VERSION 5.8 ;
BUSBITCHARS "[]" ;
DIVIDERCHAR "/" ;
UNITS
    DATABASE MICRONS 1000 ;
END UNITS

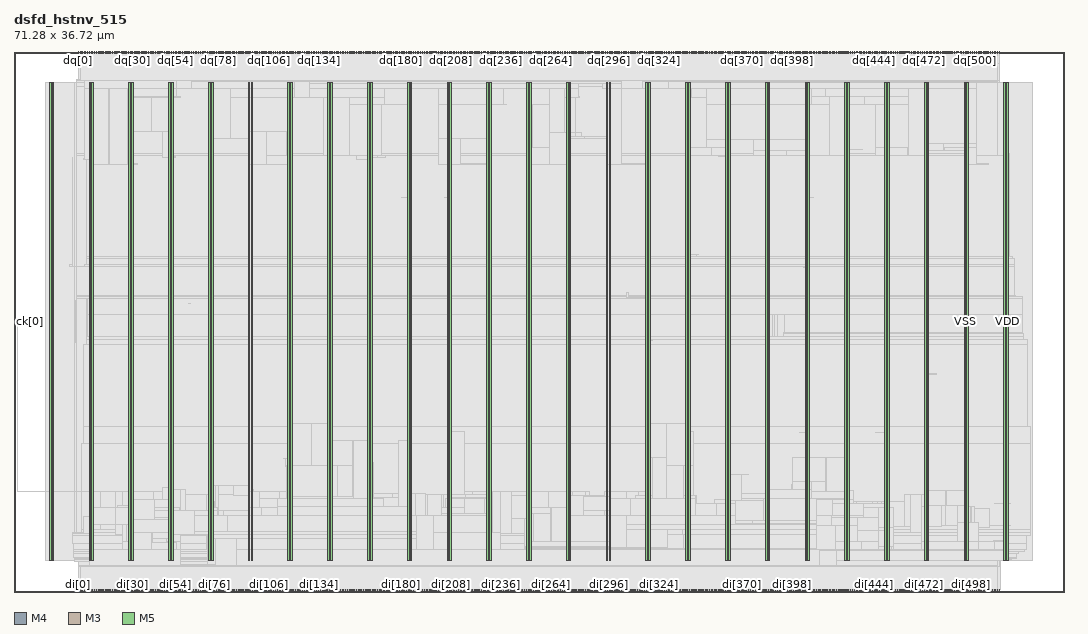
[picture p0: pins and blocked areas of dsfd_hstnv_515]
MACRO dsfd_hstnv_515
  FOREIGN dsfd_hstnv_515 0 0 ;
  CLASS BLOCK ;
  SIZE 71.28 BY 36.72 ;
  PIN ck[0]
    DIRECTION INPUT ;
    USE SIGNAL ;
    PORT
      LAYER M4 ;
        RECT  0 18.384 0.192 18.408 ;
    END
    PORT
      LAYER M4 ;
        RECT  0.156 18.384 0.275 18.408 ;
    END
  END ck[0]
  PIN di[0]
    DIRECTION INPUT ;
    USE SIGNAL ;
    PORT
      LAYER M3 ;
        RECT  4.356 0 4.374 0.144 ;
    END
  END di[0]
  PIN di[100]
    DIRECTION INPUT ;
    USE SIGNAL ;
    PORT
      LAYER M3 ;
        RECT  16.524 0 16.542 0.144 ;
    END
  END di[100]
  PIN di[101]
    DIRECTION INPUT ;
    USE SIGNAL ;
    PORT
      LAYER M5 ;
        RECT  16.656 0 16.68 0.192 ;
    END
  END di[101]
  PIN di[102]
    DIRECTION INPUT ;
    USE SIGNAL ;
    PORT
      LAYER M3 ;
        RECT  16.776 0 16.794 0.144 ;
    END
  END di[102]
  PIN di[103]
    DIRECTION INPUT ;
    USE SIGNAL ;
    PORT
      LAYER M5 ;
        RECT  16.896 0 16.92 0.192 ;
    END
  END di[103]
  PIN di[104]
    DIRECTION INPUT ;
    USE SIGNAL ;
    PORT
      LAYER M3 ;
        RECT  17.028 0 17.046 0.144 ;
    END
  END di[104]
  PIN di[105]
    DIRECTION INPUT ;
    USE SIGNAL ;
    PORT
      LAYER M5 ;
        RECT  17.136 0 17.16 0.192 ;
    END
  END di[105]
  PIN di[106]
    DIRECTION INPUT ;
    USE SIGNAL ;
    PORT
      LAYER M3 ;
        RECT  17.28 0 17.298 0.144 ;
    END
  END di[106]
  PIN di[107]
    DIRECTION INPUT ;
    USE SIGNAL ;
    PORT
      LAYER M5 ;
        RECT  17.376 0 17.4 0.192 ;
    END
  END di[107]
  PIN di[108]
    DIRECTION INPUT ;
    USE SIGNAL ;
    PORT
      LAYER M3 ;
        RECT  17.496 0 17.514 0.144 ;
    END
  END di[108]
  PIN di[109]
    DIRECTION INPUT ;
    USE SIGNAL ;
    PORT
      LAYER M5 ;
        RECT  17.616 0 17.64 0.192 ;
    END
  END di[109]
  PIN di[10]
    DIRECTION INPUT ;
    USE SIGNAL ;
    PORT
      LAYER M3 ;
        RECT  5.58 0 5.598 0.144 ;
    END
  END di[10]
  PIN di[110]
    DIRECTION INPUT ;
    USE SIGNAL ;
    PORT
      LAYER M3 ;
        RECT  17.748 0 17.766 0.144 ;
    END
  END di[110]
  PIN di[111]
    DIRECTION INPUT ;
    USE SIGNAL ;
    PORT
      LAYER M5 ;
        RECT  17.856 0 17.88 0.192 ;
    END
  END di[111]
  PIN di[112]
    DIRECTION INPUT ;
    USE SIGNAL ;
    PORT
      LAYER M3 ;
        RECT  18 0 18.018 0.144 ;
    END
  END di[112]
  PIN di[113]
    DIRECTION INPUT ;
    USE SIGNAL ;
    PORT
      LAYER M5 ;
        RECT  18.096 0 18.12 0.192 ;
    END
  END di[113]
  PIN di[114]
    DIRECTION INPUT ;
    USE SIGNAL ;
    PORT
      LAYER M3 ;
        RECT  18.252 0 18.27 0.144 ;
    END
  END di[114]
  PIN di[115]
    DIRECTION INPUT ;
    USE SIGNAL ;
    PORT
      LAYER M5 ;
        RECT  18.336 0 18.36 0.192 ;
    END
  END di[115]
  PIN di[116]
    DIRECTION INPUT ;
    USE SIGNAL ;
    PORT
      LAYER M3 ;
        RECT  18.468 0 18.486 0.144 ;
    END
  END di[116]
  PIN di[117]
    DIRECTION INPUT ;
    USE SIGNAL ;
    PORT
      LAYER M5 ;
        RECT  18.576 0 18.6 0.192 ;
    END
  END di[117]
  PIN di[118]
    DIRECTION INPUT ;
    USE SIGNAL ;
    PORT
      LAYER M3 ;
        RECT  18.72 0 18.738 0.144 ;
    END
  END di[118]
  PIN di[119]
    DIRECTION INPUT ;
    USE SIGNAL ;
    PORT
      LAYER M5 ;
        RECT  18.864 0 18.888 0.192 ;
    END
  END di[119]
  PIN di[11]
    DIRECTION INPUT ;
    USE SIGNAL ;
    PORT
      LAYER M5 ;
        RECT  5.712 0 5.736 0.192 ;
    END
  END di[11]
  PIN di[120]
    DIRECTION INPUT ;
    USE SIGNAL ;
    PORT
      LAYER M3 ;
        RECT  18.972 0 18.99 0.144 ;
    END
  END di[120]
  PIN di[121]
    DIRECTION INPUT ;
    USE SIGNAL ;
    PORT
      LAYER M5 ;
        RECT  19.104 0 19.128 0.192 ;
    END
  END di[121]
  PIN di[122]
    DIRECTION INPUT ;
    USE SIGNAL ;
    PORT
      LAYER M3 ;
        RECT  19.224 0 19.242 0.144 ;
    END
  END di[122]
  PIN di[123]
    DIRECTION INPUT ;
    USE SIGNAL ;
    PORT
      LAYER M5 ;
        RECT  19.344 0 19.368 0.192 ;
    END
  END di[123]
  PIN di[124]
    DIRECTION INPUT ;
    USE SIGNAL ;
    PORT
      LAYER M3 ;
        RECT  19.44 0 19.458 0.144 ;
    END
  END di[124]
  PIN di[125]
    DIRECTION INPUT ;
    USE SIGNAL ;
    PORT
      LAYER M5 ;
        RECT  19.584 0 19.608 0.192 ;
    END
  END di[125]
  PIN di[126]
    DIRECTION INPUT ;
    USE SIGNAL ;
    PORT
      LAYER M3 ;
        RECT  19.692 0 19.71 0.144 ;
    END
  END di[126]
  PIN di[127]
    DIRECTION INPUT ;
    USE SIGNAL ;
    PORT
      LAYER M5 ;
        RECT  19.824 0 19.848 0.192 ;
    END
  END di[127]
  PIN di[128]
    DIRECTION INPUT ;
    USE SIGNAL ;
    PORT
      LAYER M3 ;
        RECT  19.944 0 19.962 0.144 ;
    END
  END di[128]
  PIN di[129]
    DIRECTION INPUT ;
    USE SIGNAL ;
    PORT
      LAYER M5 ;
        RECT  20.064 0 20.088 0.192 ;
    END
  END di[129]
  PIN di[12]
    DIRECTION INPUT ;
    USE SIGNAL ;
    PORT
      LAYER M3 ;
        RECT  5.832 0 5.85 0.144 ;
    END
  END di[12]
  PIN di[130]
    DIRECTION INPUT ;
    USE SIGNAL ;
    PORT
      LAYER M3 ;
        RECT  20.196 0 20.214 0.144 ;
    END
  END di[130]
  PIN di[131]
    DIRECTION INPUT ;
    USE SIGNAL ;
    PORT
      LAYER M5 ;
        RECT  20.304 0 20.328 0.192 ;
    END
  END di[131]
  PIN di[132]
    DIRECTION INPUT ;
    USE SIGNAL ;
    PORT
      LAYER M3 ;
        RECT  20.412 0 20.43 0.144 ;
    END
  END di[132]
  PIN di[133]
    DIRECTION INPUT ;
    USE SIGNAL ;
    PORT
      LAYER M5 ;
        RECT  20.544 0 20.568 0.192 ;
    END
  END di[133]
  PIN di[134]
    DIRECTION INPUT ;
    USE SIGNAL ;
    PORT
      LAYER M3 ;
        RECT  20.664 0 20.682 0.144 ;
    END
  END di[134]
  PIN di[135]
    DIRECTION INPUT ;
    USE SIGNAL ;
    PORT
      LAYER M5 ;
        RECT  20.784 0 20.808 0.192 ;
    END
  END di[135]
  PIN di[136]
    DIRECTION INPUT ;
    USE SIGNAL ;
    PORT
      LAYER M3 ;
        RECT  20.916 0 20.934 0.144 ;
    END
  END di[136]
  PIN di[137]
    DIRECTION INPUT ;
    USE SIGNAL ;
    PORT
      LAYER M5 ;
        RECT  21.024 0 21.048 0.192 ;
    END
  END di[137]
  PIN di[138]
    DIRECTION INPUT ;
    USE SIGNAL ;
    PORT
      LAYER M3 ;
        RECT  21.168 0 21.186 0.144 ;
    END
  END di[138]
  PIN di[139]
    DIRECTION INPUT ;
    USE SIGNAL ;
    PORT
      LAYER M5 ;
        RECT  21.264 0 21.288 0.192 ;
    END
  END di[139]
  PIN di[13]
    DIRECTION INPUT ;
    USE SIGNAL ;
    PORT
      LAYER M5 ;
        RECT  5.952 0 5.976 0.192 ;
    END
  END di[13]
  PIN di[140]
    DIRECTION INPUT ;
    USE SIGNAL ;
    PORT
      LAYER M3 ;
        RECT  21.384 0 21.402 0.144 ;
    END
  END di[140]
  PIN di[141]
    DIRECTION INPUT ;
    USE SIGNAL ;
    PORT
      LAYER M5 ;
        RECT  21.504 0 21.528 0.192 ;
    END
  END di[141]
  PIN di[142]
    DIRECTION INPUT ;
    USE SIGNAL ;
    PORT
      LAYER M3 ;
        RECT  21.636 0 21.654 0.144 ;
    END
  END di[142]
  PIN di[143]
    DIRECTION INPUT ;
    USE SIGNAL ;
    PORT
      LAYER M5 ;
        RECT  21.744 0 21.768 0.192 ;
    END
  END di[143]
  PIN di[144]
    DIRECTION INPUT ;
    USE SIGNAL ;
    PORT
      LAYER M3 ;
        RECT  21.888 0 21.906 0.144 ;
    END
  END di[144]
  PIN di[145]
    DIRECTION INPUT ;
    USE SIGNAL ;
    PORT
      LAYER M5 ;
        RECT  21.984 0 22.008 0.192 ;
    END
  END di[145]
  PIN di[146]
    DIRECTION INPUT ;
    USE SIGNAL ;
    PORT
      LAYER M3 ;
        RECT  22.14 0 22.158 0.144 ;
    END
  END di[146]
  PIN di[147]
    DIRECTION INPUT ;
    USE SIGNAL ;
    PORT
      LAYER M5 ;
        RECT  22.272 0 22.296 0.192 ;
    END
  END di[147]
  PIN di[148]
    DIRECTION INPUT ;
    USE SIGNAL ;
    PORT
      LAYER M3 ;
        RECT  22.356 0 22.374 0.144 ;
    END
  END di[148]
  PIN di[149]
    DIRECTION INPUT ;
    USE SIGNAL ;
    PORT
      LAYER M5 ;
        RECT  22.512 0 22.536 0.192 ;
    END
  END di[149]
  PIN di[14]
    DIRECTION INPUT ;
    USE SIGNAL ;
    PORT
      LAYER M3 ;
        RECT  6.084 0 6.102 0.144 ;
    END
  END di[14]
  PIN di[150]
    DIRECTION INPUT ;
    USE SIGNAL ;
    PORT
      LAYER M3 ;
        RECT  22.608 0 22.626 0.144 ;
    END
  END di[150]
  PIN di[151]
    DIRECTION INPUT ;
    USE SIGNAL ;
    PORT
      LAYER M5 ;
        RECT  22.752 0 22.776 0.192 ;
    END
  END di[151]
  PIN di[152]
    DIRECTION INPUT ;
    USE SIGNAL ;
    PORT
      LAYER M3 ;
        RECT  22.86 0 22.878 0.144 ;
    END
  END di[152]
  PIN di[153]
    DIRECTION INPUT ;
    USE SIGNAL ;
    PORT
      LAYER M5 ;
        RECT  22.992 0 23.016 0.192 ;
    END
  END di[153]
  PIN di[154]
    DIRECTION INPUT ;
    USE SIGNAL ;
    PORT
      LAYER M3 ;
        RECT  23.112 0 23.13 0.144 ;
    END
  END di[154]
  PIN di[155]
    DIRECTION INPUT ;
    USE SIGNAL ;
    PORT
      LAYER M5 ;
        RECT  23.232 0 23.256 0.192 ;
    END
  END di[155]
  PIN di[156]
    DIRECTION INPUT ;
    USE SIGNAL ;
    PORT
      LAYER M3 ;
        RECT  23.364 0 23.382 0.144 ;
    END
  END di[156]
  PIN di[157]
    DIRECTION INPUT ;
    USE SIGNAL ;
    PORT
      LAYER M5 ;
        RECT  23.472 0 23.496 0.192 ;
    END
  END di[157]
  PIN di[158]
    DIRECTION INPUT ;
    USE SIGNAL ;
    PORT
      LAYER M3 ;
        RECT  23.58 0 23.598 0.144 ;
    END
  END di[158]
  PIN di[159]
    DIRECTION INPUT ;
    USE SIGNAL ;
    PORT
      LAYER M5 ;
        RECT  23.712 0 23.736 0.192 ;
    END
  END di[159]
  PIN di[15]
    DIRECTION INPUT ;
    USE SIGNAL ;
    PORT
      LAYER M5 ;
        RECT  6.192 0 6.216 0.192 ;
    END
  END di[15]
  PIN di[160]
    DIRECTION INPUT ;
    USE SIGNAL ;
    PORT
      LAYER M3 ;
        RECT  23.832 0 23.85 0.144 ;
    END
  END di[160]
  PIN di[161]
    DIRECTION INPUT ;
    USE SIGNAL ;
    PORT
      LAYER M5 ;
        RECT  23.952 0 23.976 0.192 ;
    END
  END di[161]
  PIN di[162]
    DIRECTION INPUT ;
    USE SIGNAL ;
    PORT
      LAYER M3 ;
        RECT  24.084 0 24.102 0.144 ;
    END
  END di[162]
  PIN di[163]
    DIRECTION INPUT ;
    USE SIGNAL ;
    PORT
      LAYER M5 ;
        RECT  24.192 0 24.216 0.192 ;
    END
  END di[163]
  PIN di[164]
    DIRECTION INPUT ;
    USE SIGNAL ;
    PORT
      LAYER M3 ;
        RECT  24.336 0 24.354 0.144 ;
    END
  END di[164]
  PIN di[165]
    DIRECTION INPUT ;
    USE SIGNAL ;
    PORT
      LAYER M5 ;
        RECT  24.432 0 24.456 0.192 ;
    END
  END di[165]
  PIN di[166]
    DIRECTION INPUT ;
    USE SIGNAL ;
    PORT
      LAYER M3 ;
        RECT  24.552 0 24.57 0.144 ;
    END
  END di[166]
  PIN di[167]
    DIRECTION INPUT ;
    USE SIGNAL ;
    PORT
      LAYER M5 ;
        RECT  24.672 0 24.696 0.192 ;
    END
  END di[167]
  PIN di[168]
    DIRECTION INPUT ;
    USE SIGNAL ;
    PORT
      LAYER M3 ;
        RECT  24.804 0 24.822 0.144 ;
    END
  END di[168]
  PIN di[169]
    DIRECTION INPUT ;
    USE SIGNAL ;
    PORT
      LAYER M5 ;
        RECT  24.912 0 24.936 0.192 ;
    END
  END di[169]
  PIN di[16]
    DIRECTION INPUT ;
    USE SIGNAL ;
    PORT
      LAYER M3 ;
        RECT  6.3 0 6.318 0.144 ;
    END
  END di[16]
  PIN di[170]
    DIRECTION INPUT ;
    USE SIGNAL ;
    PORT
      LAYER M3 ;
        RECT  25.056 0 25.074 0.144 ;
    END
  END di[170]
  PIN di[171]
    DIRECTION INPUT ;
    USE SIGNAL ;
    PORT
      LAYER M5 ;
        RECT  25.152 0 25.176 0.192 ;
    END
  END di[171]
  PIN di[172]
    DIRECTION INPUT ;
    USE SIGNAL ;
    PORT
      LAYER M3 ;
        RECT  25.308 0 25.326 0.144 ;
    END
  END di[172]
  PIN di[173]
    DIRECTION INPUT ;
    USE SIGNAL ;
    PORT
      LAYER M5 ;
        RECT  25.392 0 25.416 0.192 ;
    END
  END di[173]
  PIN di[174]
    DIRECTION INPUT ;
    USE SIGNAL ;
    PORT
      LAYER M3 ;
        RECT  25.524 0 25.542 0.144 ;
    END
  END di[174]
  PIN di[175]
    DIRECTION INPUT ;
    USE SIGNAL ;
    PORT
      LAYER M5 ;
        RECT  25.632 0 25.656 0.192 ;
    END
  END di[175]
  PIN di[176]
    DIRECTION INPUT ;
    USE SIGNAL ;
    PORT
      LAYER M3 ;
        RECT  25.776 0 25.794 0.144 ;
    END
  END di[176]
  PIN di[177]
    DIRECTION INPUT ;
    USE SIGNAL ;
    PORT
      LAYER M5 ;
        RECT  25.92 0 25.944 0.192 ;
    END
  END di[177]
  PIN di[178]
    DIRECTION INPUT ;
    USE SIGNAL ;
    PORT
      LAYER M3 ;
        RECT  26.028 0 26.046 0.144 ;
    END
  END di[178]
  PIN di[179]
    DIRECTION INPUT ;
    USE SIGNAL ;
    PORT
      LAYER M5 ;
        RECT  26.16 0 26.184 0.192 ;
    END
  END di[179]
  PIN di[17]
    DIRECTION INPUT ;
    USE SIGNAL ;
    PORT
      LAYER M5 ;
        RECT  6.432 0 6.456 0.192 ;
    END
  END di[17]
  PIN di[180]
    DIRECTION INPUT ;
    USE SIGNAL ;
    PORT
      LAYER M3 ;
        RECT  26.28 0 26.298 0.144 ;
    END
  END di[180]
  PIN di[181]
    DIRECTION INPUT ;
    USE SIGNAL ;
    PORT
      LAYER M5 ;
        RECT  26.4 0 26.424 0.192 ;
    END
  END di[181]
  PIN di[182]
    DIRECTION INPUT ;
    USE SIGNAL ;
    PORT
      LAYER M3 ;
        RECT  26.496 0 26.514 0.144 ;
    END
  END di[182]
  PIN di[183]
    DIRECTION INPUT ;
    USE SIGNAL ;
    PORT
      LAYER M5 ;
        RECT  26.64 0 26.664 0.192 ;
    END
  END di[183]
  PIN di[184]
    DIRECTION INPUT ;
    USE SIGNAL ;
    PORT
      LAYER M3 ;
        RECT  26.748 0 26.766 0.144 ;
    END
  END di[184]
  PIN di[185]
    DIRECTION INPUT ;
    USE SIGNAL ;
    PORT
      LAYER M5 ;
        RECT  26.88 0 26.904 0.192 ;
    END
  END di[185]
  PIN di[186]
    DIRECTION INPUT ;
    USE SIGNAL ;
    PORT
      LAYER M3 ;
        RECT  27 0 27.018 0.144 ;
    END
  END di[186]
  PIN di[187]
    DIRECTION INPUT ;
    USE SIGNAL ;
    PORT
      LAYER M5 ;
        RECT  27.12 0 27.144 0.192 ;
    END
  END di[187]
  PIN di[188]
    DIRECTION INPUT ;
    USE SIGNAL ;
    PORT
      LAYER M3 ;
        RECT  27.252 0 27.27 0.144 ;
    END
  END di[188]
  PIN di[189]
    DIRECTION INPUT ;
    USE SIGNAL ;
    PORT
      LAYER M5 ;
        RECT  27.36 0 27.384 0.192 ;
    END
  END di[189]
  PIN di[18]
    DIRECTION INPUT ;
    USE SIGNAL ;
    PORT
      LAYER M3 ;
        RECT  6.552 0 6.57 0.144 ;
    END
  END di[18]
  PIN di[190]
    DIRECTION INPUT ;
    USE SIGNAL ;
    PORT
      LAYER M3 ;
        RECT  27.468 0 27.486 0.144 ;
    END
  END di[190]
  PIN di[191]
    DIRECTION INPUT ;
    USE SIGNAL ;
    PORT
      LAYER M5 ;
        RECT  27.6 0 27.624 0.192 ;
    END
  END di[191]
  PIN di[192]
    DIRECTION INPUT ;
    USE SIGNAL ;
    PORT
      LAYER M3 ;
        RECT  27.72 0 27.738 0.144 ;
    END
  END di[192]
  PIN di[193]
    DIRECTION INPUT ;
    USE SIGNAL ;
    PORT
      LAYER M5 ;
        RECT  27.84 0 27.864 0.192 ;
    END
  END di[193]
  PIN di[194]
    DIRECTION INPUT ;
    USE SIGNAL ;
    PORT
      LAYER M3 ;
        RECT  27.972 0 27.99 0.144 ;
    END
  END di[194]
  PIN di[195]
    DIRECTION INPUT ;
    USE SIGNAL ;
    PORT
      LAYER M5 ;
        RECT  28.08 0 28.104 0.192 ;
    END
  END di[195]
  PIN di[196]
    DIRECTION INPUT ;
    USE SIGNAL ;
    PORT
      LAYER M3 ;
        RECT  28.224 0 28.242 0.144 ;
    END
  END di[196]
  PIN di[197]
    DIRECTION INPUT ;
    USE SIGNAL ;
    PORT
      LAYER M5 ;
        RECT  28.32 0 28.344 0.192 ;
    END
  END di[197]
  PIN di[198]
    DIRECTION INPUT ;
    USE SIGNAL ;
    PORT
      LAYER M3 ;
        RECT  28.44 0 28.458 0.144 ;
    END
  END di[198]
  PIN di[199]
    DIRECTION INPUT ;
    USE SIGNAL ;
    PORT
      LAYER M5 ;
        RECT  28.56 0 28.584 0.192 ;
    END
  END di[199]
  PIN di[19]
    DIRECTION INPUT ;
    USE SIGNAL ;
    PORT
      LAYER M5 ;
        RECT  6.672 0 6.696 0.192 ;
    END
  END di[19]
  PIN di[1]
    DIRECTION INPUT ;
    USE SIGNAL ;
    PORT
      LAYER M5 ;
        RECT  4.512 0 4.536 0.192 ;
    END
  END di[1]
  PIN di[200]
    DIRECTION INPUT ;
    USE SIGNAL ;
    PORT
      LAYER M3 ;
        RECT  28.692 0 28.71 0.144 ;
    END
  END di[200]
  PIN di[201]
    DIRECTION INPUT ;
    USE SIGNAL ;
    PORT
      LAYER M5 ;
        RECT  28.8 0 28.824 0.192 ;
    END
  END di[201]
  PIN di[202]
    DIRECTION INPUT ;
    USE SIGNAL ;
    PORT
      LAYER M3 ;
        RECT  28.944 0 28.962 0.144 ;
    END
  END di[202]
  PIN di[203]
    DIRECTION INPUT ;
    USE SIGNAL ;
    PORT
      LAYER M5 ;
        RECT  29.04 0 29.064 0.192 ;
    END
  END di[203]
  PIN di[204]
    DIRECTION INPUT ;
    USE SIGNAL ;
    PORT
      LAYER M3 ;
        RECT  29.196 0 29.214 0.144 ;
    END
  END di[204]
  PIN di[205]
    DIRECTION INPUT ;
    USE SIGNAL ;
    PORT
      LAYER M5 ;
        RECT  29.28 0 29.304 0.192 ;
    END
  END di[205]
  PIN di[206]
    DIRECTION INPUT ;
    USE SIGNAL ;
    PORT
      LAYER M3 ;
        RECT  29.412 0 29.43 0.144 ;
    END
  END di[206]
  PIN di[207]
    DIRECTION INPUT ;
    USE SIGNAL ;
    PORT
      LAYER M5 ;
        RECT  29.568 0 29.592 0.192 ;
    END
  END di[207]
  PIN di[208]
    DIRECTION INPUT ;
    USE SIGNAL ;
    PORT
      LAYER M3 ;
        RECT  29.664 0 29.682 0.144 ;
    END
  END di[208]
  PIN di[209]
    DIRECTION INPUT ;
    USE SIGNAL ;
    PORT
      LAYER M5 ;
        RECT  29.808 0 29.832 0.192 ;
    END
  END di[209]
  PIN di[20]
    DIRECTION INPUT ;
    USE SIGNAL ;
    PORT
      LAYER M3 ;
        RECT  6.804 0 6.822 0.144 ;
    END
  END di[20]
  PIN di[210]
    DIRECTION INPUT ;
    USE SIGNAL ;
    PORT
      LAYER M3 ;
        RECT  29.916 0 29.934 0.144 ;
    END
  END di[210]
  PIN di[211]
    DIRECTION INPUT ;
    USE SIGNAL ;
    PORT
      LAYER M5 ;
        RECT  30.048 0 30.072 0.192 ;
    END
  END di[211]
  PIN di[212]
    DIRECTION INPUT ;
    USE SIGNAL ;
    PORT
      LAYER M3 ;
        RECT  30.168 0 30.186 0.144 ;
    END
  END di[212]
  PIN di[213]
    DIRECTION INPUT ;
    USE SIGNAL ;
    PORT
      LAYER M5 ;
        RECT  30.288 0 30.312 0.192 ;
    END
  END di[213]
  PIN di[214]
    DIRECTION INPUT ;
    USE SIGNAL ;
    PORT
      LAYER M3 ;
        RECT  30.384 0 30.402 0.144 ;
    END
  END di[214]
  PIN di[215]
    DIRECTION INPUT ;
    USE SIGNAL ;
    PORT
      LAYER M5 ;
        RECT  30.528 0 30.552 0.192 ;
    END
  END di[215]
  PIN di[216]
    DIRECTION INPUT ;
    USE SIGNAL ;
    PORT
      LAYER M3 ;
        RECT  30.636 0 30.654 0.144 ;
    END
  END di[216]
  PIN di[217]
    DIRECTION INPUT ;
    USE SIGNAL ;
    PORT
      LAYER M5 ;
        RECT  30.768 0 30.792 0.192 ;
    END
  END di[217]
  PIN di[218]
    DIRECTION INPUT ;
    USE SIGNAL ;
    PORT
      LAYER M3 ;
        RECT  30.888 0 30.906 0.144 ;
    END
  END di[218]
  PIN di[219]
    DIRECTION INPUT ;
    USE SIGNAL ;
    PORT
      LAYER M5 ;
        RECT  31.008 0 31.032 0.192 ;
    END
  END di[219]
  PIN di[21]
    DIRECTION INPUT ;
    USE SIGNAL ;
    PORT
      LAYER M5 ;
        RECT  6.912 0 6.936 0.192 ;
    END
  END di[21]
  PIN di[220]
    DIRECTION INPUT ;
    USE SIGNAL ;
    PORT
      LAYER M3 ;
        RECT  31.14 0 31.158 0.144 ;
    END
  END di[220]
  PIN di[221]
    DIRECTION INPUT ;
    USE SIGNAL ;
    PORT
      LAYER M5 ;
        RECT  31.248 0 31.272 0.192 ;
    END
  END di[221]
  PIN di[222]
    DIRECTION INPUT ;
    USE SIGNAL ;
    PORT
      LAYER M3 ;
        RECT  31.356 0 31.374 0.144 ;
    END
  END di[222]
  PIN di[223]
    DIRECTION INPUT ;
    USE SIGNAL ;
    PORT
      LAYER M5 ;
        RECT  31.488 0 31.512 0.192 ;
    END
  END di[223]
  PIN di[224]
    DIRECTION INPUT ;
    USE SIGNAL ;
    PORT
      LAYER M3 ;
        RECT  31.608 0 31.626 0.144 ;
    END
  END di[224]
  PIN di[225]
    DIRECTION INPUT ;
    USE SIGNAL ;
    PORT
      LAYER M5 ;
        RECT  31.728 0 31.752 0.192 ;
    END
  END di[225]
  PIN di[226]
    DIRECTION INPUT ;
    USE SIGNAL ;
    PORT
      LAYER M3 ;
        RECT  31.86 0 31.878 0.144 ;
    END
  END di[226]
  PIN di[227]
    DIRECTION INPUT ;
    USE SIGNAL ;
    PORT
      LAYER M5 ;
        RECT  31.968 0 31.992 0.192 ;
    END
  END di[227]
  PIN di[228]
    DIRECTION INPUT ;
    USE SIGNAL ;
    PORT
      LAYER M3 ;
        RECT  32.112 0 32.13 0.144 ;
    END
  END di[228]
  PIN di[229]
    DIRECTION INPUT ;
    USE SIGNAL ;
    PORT
      LAYER M5 ;
        RECT  32.208 0 32.232 0.192 ;
    END
  END di[229]
  PIN di[22]
    DIRECTION INPUT ;
    USE SIGNAL ;
    PORT
      LAYER M3 ;
        RECT  7.056 0 7.074 0.144 ;
    END
  END di[22]
  PIN di[230]
    DIRECTION INPUT ;
    USE SIGNAL ;
    PORT
      LAYER M3 ;
        RECT  32.364 0 32.382 0.144 ;
    END
  END di[230]
  PIN di[231]
    DIRECTION INPUT ;
    USE SIGNAL ;
    PORT
      LAYER M5 ;
        RECT  32.448 0 32.472 0.192 ;
    END
  END di[231]
  PIN di[232]
    DIRECTION INPUT ;
    USE SIGNAL ;
    PORT
      LAYER M3 ;
        RECT  32.58 0 32.598 0.144 ;
    END
  END di[232]
  PIN di[233]
    DIRECTION INPUT ;
    USE SIGNAL ;
    PORT
      LAYER M5 ;
        RECT  32.688 0 32.712 0.192 ;
    END
  END di[233]
  PIN di[234]
    DIRECTION INPUT ;
    USE SIGNAL ;
    PORT
      LAYER M3 ;
        RECT  32.832 0 32.85 0.144 ;
    END
  END di[234]
  PIN di[235]
    DIRECTION INPUT ;
    USE SIGNAL ;
    PORT
      LAYER M5 ;
        RECT  32.976 0 33 0.192 ;
    END
  END di[235]
  PIN di[236]
    DIRECTION INPUT ;
    USE SIGNAL ;
    PORT
      LAYER M3 ;
        RECT  33.084 0 33.102 0.144 ;
    END
  END di[236]
  PIN di[237]
    DIRECTION INPUT ;
    USE SIGNAL ;
    PORT
      LAYER M5 ;
        RECT  33.216 0 33.24 0.192 ;
    END
  END di[237]
  PIN di[238]
    DIRECTION INPUT ;
    USE SIGNAL ;
    PORT
      LAYER M3 ;
        RECT  33.336 0 33.354 0.144 ;
    END
  END di[238]
  PIN di[239]
    DIRECTION INPUT ;
    USE SIGNAL ;
    PORT
      LAYER M5 ;
        RECT  33.456 0 33.48 0.192 ;
    END
  END di[239]
  PIN di[23]
    DIRECTION INPUT ;
    USE SIGNAL ;
    PORT
      LAYER M5 ;
        RECT  7.152 0 7.176 0.192 ;
    END
  END di[23]
  PIN di[240]
    DIRECTION INPUT ;
    USE SIGNAL ;
    PORT
      LAYER M3 ;
        RECT  33.552 0 33.57 0.144 ;
    END
  END di[240]
  PIN di[241]
    DIRECTION INPUT ;
    USE SIGNAL ;
    PORT
      LAYER M5 ;
        RECT  33.696 0 33.72 0.192 ;
    END
  END di[241]
  PIN di[242]
    DIRECTION INPUT ;
    USE SIGNAL ;
    PORT
      LAYER M3 ;
        RECT  33.804 0 33.822 0.144 ;
    END
  END di[242]
  PIN di[243]
    DIRECTION INPUT ;
    USE SIGNAL ;
    PORT
      LAYER M5 ;
        RECT  33.936 0 33.96 0.192 ;
    END
  END di[243]
  PIN di[244]
    DIRECTION INPUT ;
    USE SIGNAL ;
    PORT
      LAYER M3 ;
        RECT  34.056 0 34.074 0.144 ;
    END
  END di[244]
  PIN di[245]
    DIRECTION INPUT ;
    USE SIGNAL ;
    PORT
      LAYER M5 ;
        RECT  34.176 0 34.2 0.192 ;
    END
  END di[245]
  PIN di[246]
    DIRECTION INPUT ;
    USE SIGNAL ;
    PORT
      LAYER M3 ;
        RECT  34.308 0 34.326 0.144 ;
    END
  END di[246]
  PIN di[247]
    DIRECTION INPUT ;
    USE SIGNAL ;
    PORT
      LAYER M5 ;
        RECT  34.416 0 34.44 0.192 ;
    END
  END di[247]
  PIN di[248]
    DIRECTION INPUT ;
    USE SIGNAL ;
    PORT
      LAYER M3 ;
        RECT  34.524 0 34.542 0.144 ;
    END
  END di[248]
  PIN di[249]
    DIRECTION INPUT ;
    USE SIGNAL ;
    PORT
      LAYER M5 ;
        RECT  34.656 0 34.68 0.192 ;
    END
  END di[249]
  PIN di[24]
    DIRECTION INPUT ;
    USE SIGNAL ;
    PORT
      LAYER M3 ;
        RECT  7.308 0 7.326 0.144 ;
    END
  END di[24]
  PIN di[250]
    DIRECTION INPUT ;
    USE SIGNAL ;
    PORT
      LAYER M3 ;
        RECT  34.776 0 34.794 0.144 ;
    END
  END di[250]
  PIN di[251]
    DIRECTION INPUT ;
    USE SIGNAL ;
    PORT
      LAYER M5 ;
        RECT  34.896 0 34.92 0.192 ;
    END
  END di[251]
  PIN di[252]
    DIRECTION INPUT ;
    USE SIGNAL ;
    PORT
      LAYER M3 ;
        RECT  35.028 0 35.046 0.144 ;
    END
  END di[252]
  PIN di[253]
    DIRECTION INPUT ;
    USE SIGNAL ;
    PORT
      LAYER M5 ;
        RECT  35.136 0 35.16 0.192 ;
    END
  END di[253]
  PIN di[254]
    DIRECTION INPUT ;
    USE SIGNAL ;
    PORT
      LAYER M3 ;
        RECT  35.28 0 35.298 0.144 ;
    END
  END di[254]
  PIN di[255]
    DIRECTION INPUT ;
    USE SIGNAL ;
    PORT
      LAYER M5 ;
        RECT  35.376 0 35.4 0.192 ;
    END
  END di[255]
  PIN di[256]
    DIRECTION INPUT ;
    USE SIGNAL ;
    PORT
      LAYER M3 ;
        RECT  35.496 0 35.514 0.144 ;
    END
  END di[256]
  PIN di[257]
    DIRECTION INPUT ;
    USE SIGNAL ;
    PORT
      LAYER M5 ;
        RECT  35.616 0 35.64 0.192 ;
    END
  END di[257]
  PIN di[258]
    DIRECTION INPUT ;
    USE SIGNAL ;
    PORT
      LAYER M3 ;
        RECT  35.748 0 35.766 0.144 ;
    END
  END di[258]
  PIN di[259]
    DIRECTION INPUT ;
    USE SIGNAL ;
    PORT
      LAYER M5 ;
        RECT  35.856 0 35.88 0.192 ;
    END
  END di[259]
  PIN di[25]
    DIRECTION INPUT ;
    USE SIGNAL ;
    PORT
      LAYER M5 ;
        RECT  7.392 0 7.416 0.192 ;
    END
  END di[25]
  PIN di[260]
    DIRECTION INPUT ;
    USE SIGNAL ;
    PORT
      LAYER M3 ;
        RECT  36 0 36.018 0.144 ;
    END
  END di[260]
  PIN di[261]
    DIRECTION INPUT ;
    USE SIGNAL ;
    PORT
      LAYER M5 ;
        RECT  36.096 0 36.12 0.192 ;
    END
  END di[261]
  PIN di[262]
    DIRECTION INPUT ;
    USE SIGNAL ;
    PORT
      LAYER M3 ;
        RECT  36.252 0 36.27 0.144 ;
    END
  END di[262]
  PIN di[263]
    DIRECTION INPUT ;
    USE SIGNAL ;
    PORT
      LAYER M5 ;
        RECT  36.336 0 36.36 0.192 ;
    END
  END di[263]
  PIN di[264]
    DIRECTION INPUT ;
    USE SIGNAL ;
    PORT
      LAYER M3 ;
        RECT  36.468 0 36.486 0.144 ;
    END
  END di[264]
  PIN di[265]
    DIRECTION INPUT ;
    USE SIGNAL ;
    PORT
      LAYER M5 ;
        RECT  36.624 0 36.648 0.192 ;
    END
  END di[265]
  PIN di[266]
    DIRECTION INPUT ;
    USE SIGNAL ;
    PORT
      LAYER M3 ;
        RECT  36.72 0 36.738 0.144 ;
    END
  END di[266]
  PIN di[267]
    DIRECTION INPUT ;
    USE SIGNAL ;
    PORT
      LAYER M5 ;
        RECT  36.864 0 36.888 0.192 ;
    END
  END di[267]
  PIN di[268]
    DIRECTION INPUT ;
    USE SIGNAL ;
    PORT
      LAYER M3 ;
        RECT  36.972 0 36.99 0.144 ;
    END
  END di[268]
  PIN di[269]
    DIRECTION INPUT ;
    USE SIGNAL ;
    PORT
      LAYER M5 ;
        RECT  37.104 0 37.128 0.192 ;
    END
  END di[269]
  PIN di[26]
    DIRECTION INPUT ;
    USE SIGNAL ;
    PORT
      LAYER M3 ;
        RECT  7.524 0 7.542 0.144 ;
    END
  END di[26]
  PIN di[270]
    DIRECTION INPUT ;
    USE SIGNAL ;
    PORT
      LAYER M3 ;
        RECT  37.224 0 37.242 0.144 ;
    END
  END di[270]
  PIN di[271]
    DIRECTION INPUT ;
    USE SIGNAL ;
    PORT
      LAYER M5 ;
        RECT  37.344 0 37.368 0.192 ;
    END
  END di[271]
  PIN di[272]
    DIRECTION INPUT ;
    USE SIGNAL ;
    PORT
      LAYER M3 ;
        RECT  37.44 0 37.458 0.144 ;
    END
  END di[272]
  PIN di[273]
    DIRECTION INPUT ;
    USE SIGNAL ;
    PORT
      LAYER M5 ;
        RECT  37.584 0 37.608 0.192 ;
    END
  END di[273]
  PIN di[274]
    DIRECTION INPUT ;
    USE SIGNAL ;
    PORT
      LAYER M3 ;
        RECT  37.692 0 37.71 0.144 ;
    END
  END di[274]
  PIN di[275]
    DIRECTION INPUT ;
    USE SIGNAL ;
    PORT
      LAYER M5 ;
        RECT  37.824 0 37.848 0.192 ;
    END
  END di[275]
  PIN di[276]
    DIRECTION INPUT ;
    USE SIGNAL ;
    PORT
      LAYER M3 ;
        RECT  37.944 0 37.962 0.144 ;
    END
  END di[276]
  PIN di[277]
    DIRECTION INPUT ;
    USE SIGNAL ;
    PORT
      LAYER M5 ;
        RECT  38.064 0 38.088 0.192 ;
    END
  END di[277]
  PIN di[278]
    DIRECTION INPUT ;
    USE SIGNAL ;
    PORT
      LAYER M3 ;
        RECT  38.196 0 38.214 0.144 ;
    END
  END di[278]
  PIN di[279]
    DIRECTION INPUT ;
    USE SIGNAL ;
    PORT
      LAYER M5 ;
        RECT  38.304 0 38.328 0.192 ;
    END
  END di[279]
  PIN di[27]
    DIRECTION INPUT ;
    USE SIGNAL ;
    PORT
      LAYER M5 ;
        RECT  7.632 0 7.656 0.192 ;
    END
  END di[27]
  PIN di[280]
    DIRECTION INPUT ;
    USE SIGNAL ;
    PORT
      LAYER M3 ;
        RECT  38.412 0 38.43 0.144 ;
    END
  END di[280]
  PIN di[281]
    DIRECTION INPUT ;
    USE SIGNAL ;
    PORT
      LAYER M5 ;
        RECT  38.544 0 38.568 0.192 ;
    END
  END di[281]
  PIN di[282]
    DIRECTION INPUT ;
    USE SIGNAL ;
    PORT
      LAYER M3 ;
        RECT  38.664 0 38.682 0.144 ;
    END
  END di[282]
  PIN di[283]
    DIRECTION INPUT ;
    USE SIGNAL ;
    PORT
      LAYER M5 ;
        RECT  38.784 0 38.808 0.192 ;
    END
  END di[283]
  PIN di[284]
    DIRECTION INPUT ;
    USE SIGNAL ;
    PORT
      LAYER M3 ;
        RECT  38.916 0 38.934 0.144 ;
    END
  END di[284]
  PIN di[285]
    DIRECTION INPUT ;
    USE SIGNAL ;
    PORT
      LAYER M5 ;
        RECT  39.024 0 39.048 0.192 ;
    END
  END di[285]
  PIN di[286]
    DIRECTION INPUT ;
    USE SIGNAL ;
    PORT
      LAYER M3 ;
        RECT  39.168 0 39.186 0.144 ;
    END
  END di[286]
  PIN di[287]
    DIRECTION INPUT ;
    USE SIGNAL ;
    PORT
      LAYER M5 ;
        RECT  39.264 0 39.288 0.192 ;
    END
  END di[287]
  PIN di[288]
    DIRECTION INPUT ;
    USE SIGNAL ;
    PORT
      LAYER M3 ;
        RECT  39.384 0 39.402 0.144 ;
    END
  END di[288]
  PIN di[289]
    DIRECTION INPUT ;
    USE SIGNAL ;
    PORT
      LAYER M5 ;
        RECT  39.504 0 39.528 0.192 ;
    END
  END di[289]
  PIN di[28]
    DIRECTION INPUT ;
    USE SIGNAL ;
    PORT
      LAYER M3 ;
        RECT  7.776 0 7.794 0.144 ;
    END
  END di[28]
  PIN di[290]
    DIRECTION INPUT ;
    USE SIGNAL ;
    PORT
      LAYER M3 ;
        RECT  39.636 0 39.654 0.144 ;
    END
  END di[290]
  PIN di[291]
    DIRECTION INPUT ;
    USE SIGNAL ;
    PORT
      LAYER M5 ;
        RECT  39.744 0 39.768 0.192 ;
    END
  END di[291]
  PIN di[292]
    DIRECTION INPUT ;
    USE SIGNAL ;
    PORT
      LAYER M3 ;
        RECT  39.888 0 39.906 0.144 ;
    END
  END di[292]
  PIN di[293]
    DIRECTION INPUT ;
    USE SIGNAL ;
    PORT
      LAYER M5 ;
        RECT  39.984 0 40.008 0.192 ;
    END
  END di[293]
  PIN di[294]
    DIRECTION INPUT ;
    USE SIGNAL ;
    PORT
      LAYER M3 ;
        RECT  40.14 0 40.158 0.144 ;
    END
  END di[294]
  PIN di[295]
    DIRECTION INPUT ;
    USE SIGNAL ;
    PORT
      LAYER M5 ;
        RECT  40.272 0 40.296 0.192 ;
    END
  END di[295]
  PIN di[296]
    DIRECTION INPUT ;
    USE SIGNAL ;
    PORT
      LAYER M3 ;
        RECT  40.392 0 40.41 0.144 ;
    END
  END di[296]
  PIN di[297]
    DIRECTION INPUT ;
    USE SIGNAL ;
    PORT
      LAYER M5 ;
        RECT  40.512 0 40.536 0.192 ;
    END
  END di[297]
  PIN di[298]
    DIRECTION INPUT ;
    USE SIGNAL ;
    PORT
      LAYER M3 ;
        RECT  40.608 0 40.626 0.144 ;
    END
  END di[298]
  PIN di[299]
    DIRECTION INPUT ;
    USE SIGNAL ;
    PORT
      LAYER M5 ;
        RECT  40.752 0 40.776 0.192 ;
    END
  END di[299]
  PIN di[29]
    DIRECTION INPUT ;
    USE SIGNAL ;
    PORT
      LAYER M5 ;
        RECT  7.92 0 7.944 0.192 ;
    END
  END di[29]
  PIN di[2]
    DIRECTION INPUT ;
    USE SIGNAL ;
    PORT
      LAYER M3 ;
        RECT  4.608 0 4.626 0.144 ;
    END
  END di[2]
  PIN di[300]
    DIRECTION INPUT ;
    USE SIGNAL ;
    PORT
      LAYER M3 ;
        RECT  40.86 0 40.878 0.144 ;
    END
  END di[300]
  PIN di[301]
    DIRECTION INPUT ;
    USE SIGNAL ;
    PORT
      LAYER M5 ;
        RECT  40.992 0 41.016 0.192 ;
    END
  END di[301]
  PIN di[302]
    DIRECTION INPUT ;
    USE SIGNAL ;
    PORT
      LAYER M3 ;
        RECT  41.112 0 41.13 0.144 ;
    END
  END di[302]
  PIN di[303]
    DIRECTION INPUT ;
    USE SIGNAL ;
    PORT
      LAYER M5 ;
        RECT  41.232 0 41.256 0.192 ;
    END
  END di[303]
  PIN di[304]
    DIRECTION INPUT ;
    USE SIGNAL ;
    PORT
      LAYER M3 ;
        RECT  41.364 0 41.382 0.144 ;
    END
  END di[304]
  PIN di[305]
    DIRECTION INPUT ;
    USE SIGNAL ;
    PORT
      LAYER M5 ;
        RECT  41.472 0 41.496 0.192 ;
    END
  END di[305]
  PIN di[306]
    DIRECTION INPUT ;
    USE SIGNAL ;
    PORT
      LAYER M3 ;
        RECT  41.58 0 41.598 0.144 ;
    END
  END di[306]
  PIN di[307]
    DIRECTION INPUT ;
    USE SIGNAL ;
    PORT
      LAYER M5 ;
        RECT  41.712 0 41.736 0.192 ;
    END
  END di[307]
  PIN di[308]
    DIRECTION INPUT ;
    USE SIGNAL ;
    PORT
      LAYER M3 ;
        RECT  41.832 0 41.85 0.144 ;
    END
  END di[308]
  PIN di[309]
    DIRECTION INPUT ;
    USE SIGNAL ;
    PORT
      LAYER M5 ;
        RECT  41.952 0 41.976 0.192 ;
    END
  END di[309]
  PIN di[30]
    DIRECTION INPUT ;
    USE SIGNAL ;
    PORT
      LAYER M3 ;
        RECT  8.028 0 8.046 0.144 ;
    END
  END di[30]
  PIN di[310]
    DIRECTION INPUT ;
    USE SIGNAL ;
    PORT
      LAYER M3 ;
        RECT  42.084 0 42.102 0.144 ;
    END
  END di[310]
  PIN di[311]
    DIRECTION INPUT ;
    USE SIGNAL ;
    PORT
      LAYER M5 ;
        RECT  42.192 0 42.216 0.192 ;
    END
  END di[311]
  PIN di[312]
    DIRECTION INPUT ;
    USE SIGNAL ;
    PORT
      LAYER M3 ;
        RECT  42.336 0 42.354 0.144 ;
    END
  END di[312]
  PIN di[313]
    DIRECTION INPUT ;
    USE SIGNAL ;
    PORT
      LAYER M5 ;
        RECT  42.432 0 42.456 0.192 ;
    END
  END di[313]
  PIN di[314]
    DIRECTION INPUT ;
    USE SIGNAL ;
    PORT
      LAYER M3 ;
        RECT  42.552 0 42.57 0.144 ;
    END
  END di[314]
  PIN di[315]
    DIRECTION INPUT ;
    USE SIGNAL ;
    PORT
      LAYER M5 ;
        RECT  42.672 0 42.696 0.192 ;
    END
  END di[315]
  PIN di[316]
    DIRECTION INPUT ;
    USE SIGNAL ;
    PORT
      LAYER M3 ;
        RECT  42.804 0 42.822 0.144 ;
    END
  END di[316]
  PIN di[317]
    DIRECTION INPUT ;
    USE SIGNAL ;
    PORT
      LAYER M5 ;
        RECT  42.912 0 42.936 0.192 ;
    END
  END di[317]
  PIN di[318]
    DIRECTION INPUT ;
    USE SIGNAL ;
    PORT
      LAYER M3 ;
        RECT  43.056 0 43.074 0.144 ;
    END
  END di[318]
  PIN di[319]
    DIRECTION INPUT ;
    USE SIGNAL ;
    PORT
      LAYER M5 ;
        RECT  43.152 0 43.176 0.192 ;
    END
  END di[319]
  PIN di[31]
    DIRECTION INPUT ;
    USE SIGNAL ;
    PORT
      LAYER M5 ;
        RECT  8.16 0 8.184 0.192 ;
    END
  END di[31]
  PIN di[320]
    DIRECTION INPUT ;
    USE SIGNAL ;
    PORT
      LAYER M3 ;
        RECT  43.308 0 43.326 0.144 ;
    END
  END di[320]
  PIN di[321]
    DIRECTION INPUT ;
    USE SIGNAL ;
    PORT
      LAYER M5 ;
        RECT  43.392 0 43.416 0.192 ;
    END
  END di[321]
  PIN di[322]
    DIRECTION INPUT ;
    USE SIGNAL ;
    PORT
      LAYER M3 ;
        RECT  43.524 0 43.542 0.144 ;
    END
  END di[322]
  PIN di[323]
    DIRECTION INPUT ;
    USE SIGNAL ;
    PORT
      LAYER M5 ;
        RECT  43.632 0 43.656 0.192 ;
    END
  END di[323]
  PIN di[324]
    DIRECTION INPUT ;
    USE SIGNAL ;
    PORT
      LAYER M3 ;
        RECT  43.776 0 43.794 0.144 ;
    END
  END di[324]
  PIN di[325]
    DIRECTION INPUT ;
    USE SIGNAL ;
    PORT
      LAYER M5 ;
        RECT  43.92 0 43.944 0.192 ;
    END
  END di[325]
  PIN di[326]
    DIRECTION INPUT ;
    USE SIGNAL ;
    PORT
      LAYER M3 ;
        RECT  44.028 0 44.046 0.144 ;
    END
  END di[326]
  PIN di[327]
    DIRECTION INPUT ;
    USE SIGNAL ;
    PORT
      LAYER M5 ;
        RECT  44.16 0 44.184 0.192 ;
    END
  END di[327]
  PIN di[328]
    DIRECTION INPUT ;
    USE SIGNAL ;
    PORT
      LAYER M3 ;
        RECT  44.28 0 44.298 0.144 ;
    END
  END di[328]
  PIN di[329]
    DIRECTION INPUT ;
    USE SIGNAL ;
    PORT
      LAYER M5 ;
        RECT  44.4 0 44.424 0.192 ;
    END
  END di[329]
  PIN di[32]
    DIRECTION INPUT ;
    USE SIGNAL ;
    PORT
      LAYER M3 ;
        RECT  8.28 0 8.298 0.144 ;
    END
  END di[32]
  PIN di[330]
    DIRECTION INPUT ;
    USE SIGNAL ;
    PORT
      LAYER M3 ;
        RECT  44.496 0 44.514 0.144 ;
    END
  END di[330]
  PIN di[331]
    DIRECTION INPUT ;
    USE SIGNAL ;
    PORT
      LAYER M5 ;
        RECT  44.64 0 44.664 0.192 ;
    END
  END di[331]
  PIN di[332]
    DIRECTION INPUT ;
    USE SIGNAL ;
    PORT
      LAYER M3 ;
        RECT  44.748 0 44.766 0.144 ;
    END
  END di[332]
  PIN di[333]
    DIRECTION INPUT ;
    USE SIGNAL ;
    PORT
      LAYER M5 ;
        RECT  44.88 0 44.904 0.192 ;
    END
  END di[333]
  PIN di[334]
    DIRECTION INPUT ;
    USE SIGNAL ;
    PORT
      LAYER M3 ;
        RECT  45 0 45.018 0.144 ;
    END
  END di[334]
  PIN di[335]
    DIRECTION INPUT ;
    USE SIGNAL ;
    PORT
      LAYER M5 ;
        RECT  45.12 0 45.144 0.192 ;
    END
  END di[335]
  PIN di[336]
    DIRECTION INPUT ;
    USE SIGNAL ;
    PORT
      LAYER M3 ;
        RECT  45.252 0 45.27 0.144 ;
    END
  END di[336]
  PIN di[337]
    DIRECTION INPUT ;
    USE SIGNAL ;
    PORT
      LAYER M5 ;
        RECT  45.36 0 45.384 0.192 ;
    END
  END di[337]
  PIN di[338]
    DIRECTION INPUT ;
    USE SIGNAL ;
    PORT
      LAYER M3 ;
        RECT  45.468 0 45.486 0.144 ;
    END
  END di[338]
  PIN di[339]
    DIRECTION INPUT ;
    USE SIGNAL ;
    PORT
      LAYER M5 ;
        RECT  45.6 0 45.624 0.192 ;
    END
  END di[339]
  PIN di[33]
    DIRECTION INPUT ;
    USE SIGNAL ;
    PORT
      LAYER M5 ;
        RECT  8.4 0 8.424 0.192 ;
    END
  END di[33]
  PIN di[340]
    DIRECTION INPUT ;
    USE SIGNAL ;
    PORT
      LAYER M3 ;
        RECT  45.72 0 45.738 0.144 ;
    END
  END di[340]
  PIN di[341]
    DIRECTION INPUT ;
    USE SIGNAL ;
    PORT
      LAYER M5 ;
        RECT  45.84 0 45.864 0.192 ;
    END
  END di[341]
  PIN di[342]
    DIRECTION INPUT ;
    USE SIGNAL ;
    PORT
      LAYER M3 ;
        RECT  45.972 0 45.99 0.144 ;
    END
  END di[342]
  PIN di[343]
    DIRECTION INPUT ;
    USE SIGNAL ;
    PORT
      LAYER M5 ;
        RECT  46.08 0 46.104 0.192 ;
    END
  END di[343]
  PIN di[344]
    DIRECTION INPUT ;
    USE SIGNAL ;
    PORT
      LAYER M3 ;
        RECT  46.224 0 46.242 0.144 ;
    END
  END di[344]
  PIN di[345]
    DIRECTION INPUT ;
    USE SIGNAL ;
    PORT
      LAYER M5 ;
        RECT  46.32 0 46.344 0.192 ;
    END
  END di[345]
  PIN di[346]
    DIRECTION INPUT ;
    USE SIGNAL ;
    PORT
      LAYER M3 ;
        RECT  46.44 0 46.458 0.144 ;
    END
  END di[346]
  PIN di[347]
    DIRECTION INPUT ;
    USE SIGNAL ;
    PORT
      LAYER M5 ;
        RECT  46.56 0 46.584 0.192 ;
    END
  END di[347]
  PIN di[348]
    DIRECTION INPUT ;
    USE SIGNAL ;
    PORT
      LAYER M3 ;
        RECT  46.692 0 46.71 0.144 ;
    END
  END di[348]
  PIN di[349]
    DIRECTION INPUT ;
    USE SIGNAL ;
    PORT
      LAYER M5 ;
        RECT  46.8 0 46.824 0.192 ;
    END
  END di[349]
  PIN di[34]
    DIRECTION INPUT ;
    USE SIGNAL ;
    PORT
      LAYER M3 ;
        RECT  8.496 0 8.514 0.144 ;
    END
  END di[34]
  PIN di[350]
    DIRECTION INPUT ;
    USE SIGNAL ;
    PORT
      LAYER M3 ;
        RECT  46.944 0 46.962 0.144 ;
    END
  END di[350]
  PIN di[351]
    DIRECTION INPUT ;
    USE SIGNAL ;
    PORT
      LAYER M5 ;
        RECT  47.04 0 47.064 0.192 ;
    END
  END di[351]
  PIN di[352]
    DIRECTION INPUT ;
    USE SIGNAL ;
    PORT
      LAYER M3 ;
        RECT  47.196 0 47.214 0.144 ;
    END
  END di[352]
  PIN di[353]
    DIRECTION INPUT ;
    USE SIGNAL ;
    PORT
      LAYER M5 ;
        RECT  47.328 0 47.352 0.192 ;
    END
  END di[353]
  PIN di[354]
    DIRECTION INPUT ;
    USE SIGNAL ;
    PORT
      LAYER M3 ;
        RECT  47.412 0 47.43 0.144 ;
    END
  END di[354]
  PIN di[355]
    DIRECTION INPUT ;
    USE SIGNAL ;
    PORT
      LAYER M5 ;
        RECT  47.568 0 47.592 0.192 ;
    END
  END di[355]
  PIN di[356]
    DIRECTION INPUT ;
    USE SIGNAL ;
    PORT
      LAYER M3 ;
        RECT  47.664 0 47.682 0.144 ;
    END
  END di[356]
  PIN di[357]
    DIRECTION INPUT ;
    USE SIGNAL ;
    PORT
      LAYER M5 ;
        RECT  47.808 0 47.832 0.192 ;
    END
  END di[357]
  PIN di[358]
    DIRECTION INPUT ;
    USE SIGNAL ;
    PORT
      LAYER M3 ;
        RECT  47.916 0 47.934 0.144 ;
    END
  END di[358]
  PIN di[359]
    DIRECTION INPUT ;
    USE SIGNAL ;
    PORT
      LAYER M5 ;
        RECT  48.048 0 48.072 0.192 ;
    END
  END di[359]
  PIN di[35]
    DIRECTION INPUT ;
    USE SIGNAL ;
    PORT
      LAYER M5 ;
        RECT  8.64 0 8.664 0.192 ;
    END
  END di[35]
  PIN di[360]
    DIRECTION INPUT ;
    USE SIGNAL ;
    PORT
      LAYER M3 ;
        RECT  48.168 0 48.186 0.144 ;
    END
  END di[360]
  PIN di[361]
    DIRECTION INPUT ;
    USE SIGNAL ;
    PORT
      LAYER M5 ;
        RECT  48.288 0 48.312 0.192 ;
    END
  END di[361]
  PIN di[362]
    DIRECTION INPUT ;
    USE SIGNAL ;
    PORT
      LAYER M3 ;
        RECT  48.42 0 48.438 0.144 ;
    END
  END di[362]
  PIN di[363]
    DIRECTION INPUT ;
    USE SIGNAL ;
    PORT
      LAYER M5 ;
        RECT  48.528 0 48.552 0.192 ;
    END
  END di[363]
  PIN di[364]
    DIRECTION INPUT ;
    USE SIGNAL ;
    PORT
      LAYER M3 ;
        RECT  48.636 0 48.654 0.144 ;
    END
  END di[364]
  PIN di[365]
    DIRECTION INPUT ;
    USE SIGNAL ;
    PORT
      LAYER M5 ;
        RECT  48.768 0 48.792 0.192 ;
    END
  END di[365]
  PIN di[366]
    DIRECTION INPUT ;
    USE SIGNAL ;
    PORT
      LAYER M3 ;
        RECT  48.888 0 48.906 0.144 ;
    END
  END di[366]
  PIN di[367]
    DIRECTION INPUT ;
    USE SIGNAL ;
    PORT
      LAYER M5 ;
        RECT  49.008 0 49.032 0.192 ;
    END
  END di[367]
  PIN di[368]
    DIRECTION INPUT ;
    USE SIGNAL ;
    PORT
      LAYER M3 ;
        RECT  49.14 0 49.158 0.144 ;
    END
  END di[368]
  PIN di[369]
    DIRECTION INPUT ;
    USE SIGNAL ;
    PORT
      LAYER M5 ;
        RECT  49.248 0 49.272 0.192 ;
    END
  END di[369]
  PIN di[36]
    DIRECTION INPUT ;
    USE SIGNAL ;
    PORT
      LAYER M3 ;
        RECT  8.748 0 8.766 0.144 ;
    END
  END di[36]
  PIN di[370]
    DIRECTION INPUT ;
    USE SIGNAL ;
    PORT
      LAYER M3 ;
        RECT  49.392 0 49.41 0.144 ;
    END
  END di[370]
  PIN di[371]
    DIRECTION INPUT ;
    USE SIGNAL ;
    PORT
      LAYER M5 ;
        RECT  49.488 0 49.512 0.192 ;
    END
  END di[371]
  PIN di[372]
    DIRECTION INPUT ;
    USE SIGNAL ;
    PORT
      LAYER M3 ;
        RECT  49.608 0 49.626 0.144 ;
    END
  END di[372]
  PIN di[373]
    DIRECTION INPUT ;
    USE SIGNAL ;
    PORT
      LAYER M5 ;
        RECT  49.728 0 49.752 0.192 ;
    END
  END di[373]
  PIN di[374]
    DIRECTION INPUT ;
    USE SIGNAL ;
    PORT
      LAYER M3 ;
        RECT  49.86 0 49.878 0.144 ;
    END
  END di[374]
  PIN di[375]
    DIRECTION INPUT ;
    USE SIGNAL ;
    PORT
      LAYER M5 ;
        RECT  49.968 0 49.992 0.192 ;
    END
  END di[375]
  PIN di[376]
    DIRECTION INPUT ;
    USE SIGNAL ;
    PORT
      LAYER M3 ;
        RECT  50.112 0 50.13 0.144 ;
    END
  END di[376]
  PIN di[377]
    DIRECTION INPUT ;
    USE SIGNAL ;
    PORT
      LAYER M5 ;
        RECT  50.208 0 50.232 0.192 ;
    END
  END di[377]
  PIN di[378]
    DIRECTION INPUT ;
    USE SIGNAL ;
    PORT
      LAYER M3 ;
        RECT  50.364 0 50.382 0.144 ;
    END
  END di[378]
  PIN di[379]
    DIRECTION INPUT ;
    USE SIGNAL ;
    PORT
      LAYER M5 ;
        RECT  50.448 0 50.472 0.192 ;
    END
  END di[379]
  PIN di[37]
    DIRECTION INPUT ;
    USE SIGNAL ;
    PORT
      LAYER M5 ;
        RECT  8.88 0 8.904 0.192 ;
    END
  END di[37]
  PIN di[380]
    DIRECTION INPUT ;
    USE SIGNAL ;
    PORT
      LAYER M3 ;
        RECT  50.58 0 50.598 0.144 ;
    END
  END di[380]
  PIN di[381]
    DIRECTION INPUT ;
    USE SIGNAL ;
    PORT
      LAYER M5 ;
        RECT  50.688 0 50.712 0.192 ;
    END
  END di[381]
  PIN di[382]
    DIRECTION INPUT ;
    USE SIGNAL ;
    PORT
      LAYER M3 ;
        RECT  50.832 0 50.85 0.144 ;
    END
  END di[382]
  PIN di[383]
    DIRECTION INPUT ;
    USE SIGNAL ;
    PORT
      LAYER M5 ;
        RECT  50.976 0 51 0.192 ;
    END
  END di[383]
  PIN di[384]
    DIRECTION INPUT ;
    USE SIGNAL ;
    PORT
      LAYER M3 ;
        RECT  51.084 0 51.102 0.144 ;
    END
  END di[384]
  PIN di[385]
    DIRECTION INPUT ;
    USE SIGNAL ;
    PORT
      LAYER M5 ;
        RECT  51.216 0 51.24 0.192 ;
    END
  END di[385]
  PIN di[386]
    DIRECTION INPUT ;
    USE SIGNAL ;
    PORT
      LAYER M3 ;
        RECT  51.336 0 51.354 0.144 ;
    END
  END di[386]
  PIN di[387]
    DIRECTION INPUT ;
    USE SIGNAL ;
    PORT
      LAYER M5 ;
        RECT  51.456 0 51.48 0.192 ;
    END
  END di[387]
  PIN di[388]
    DIRECTION INPUT ;
    USE SIGNAL ;
    PORT
      LAYER M3 ;
        RECT  51.552 0 51.57 0.144 ;
    END
  END di[388]
  PIN di[389]
    DIRECTION INPUT ;
    USE SIGNAL ;
    PORT
      LAYER M5 ;
        RECT  51.696 0 51.72 0.192 ;
    END
  END di[389]
  PIN di[38]
    DIRECTION INPUT ;
    USE SIGNAL ;
    PORT
      LAYER M3 ;
        RECT  9 0 9.018 0.144 ;
    END
  END di[38]
  PIN di[390]
    DIRECTION INPUT ;
    USE SIGNAL ;
    PORT
      LAYER M3 ;
        RECT  51.804 0 51.822 0.144 ;
    END
  END di[390]
  PIN di[391]
    DIRECTION INPUT ;
    USE SIGNAL ;
    PORT
      LAYER M5 ;
        RECT  51.936 0 51.96 0.192 ;
    END
  END di[391]
  PIN di[392]
    DIRECTION INPUT ;
    USE SIGNAL ;
    PORT
      LAYER M3 ;
        RECT  52.056 0 52.074 0.144 ;
    END
  END di[392]
  PIN di[393]
    DIRECTION INPUT ;
    USE SIGNAL ;
    PORT
      LAYER M5 ;
        RECT  52.176 0 52.2 0.192 ;
    END
  END di[393]
  PIN di[394]
    DIRECTION INPUT ;
    USE SIGNAL ;
    PORT
      LAYER M3 ;
        RECT  52.308 0 52.326 0.144 ;
    END
  END di[394]
  PIN di[395]
    DIRECTION INPUT ;
    USE SIGNAL ;
    PORT
      LAYER M5 ;
        RECT  52.416 0 52.44 0.192 ;
    END
  END di[395]
  PIN di[396]
    DIRECTION INPUT ;
    USE SIGNAL ;
    PORT
      LAYER M3 ;
        RECT  52.524 0 52.542 0.144 ;
    END
  END di[396]
  PIN di[397]
    DIRECTION INPUT ;
    USE SIGNAL ;
    PORT
      LAYER M5 ;
        RECT  52.656 0 52.68 0.192 ;
    END
  END di[397]
  PIN di[398]
    DIRECTION INPUT ;
    USE SIGNAL ;
    PORT
      LAYER M3 ;
        RECT  52.776 0 52.794 0.144 ;
    END
  END di[398]
  PIN di[399]
    DIRECTION INPUT ;
    USE SIGNAL ;
    PORT
      LAYER M5 ;
        RECT  52.896 0 52.92 0.192 ;
    END
  END di[399]
  PIN di[39]
    DIRECTION INPUT ;
    USE SIGNAL ;
    PORT
      LAYER M5 ;
        RECT  9.12 0 9.144 0.192 ;
    END
  END di[39]
  PIN di[3]
    DIRECTION INPUT ;
    USE SIGNAL ;
    PORT
      LAYER M5 ;
        RECT  4.752 0 4.776 0.192 ;
    END
  END di[3]
  PIN di[400]
    DIRECTION INPUT ;
    USE SIGNAL ;
    PORT
      LAYER M3 ;
        RECT  53.028 0 53.046 0.144 ;
    END
  END di[400]
  PIN di[401]
    DIRECTION INPUT ;
    USE SIGNAL ;
    PORT
      LAYER M5 ;
        RECT  53.136 0 53.16 0.192 ;
    END
  END di[401]
  PIN di[402]
    DIRECTION INPUT ;
    USE SIGNAL ;
    PORT
      LAYER M3 ;
        RECT  53.28 0 53.298 0.144 ;
    END
  END di[402]
  PIN di[403]
    DIRECTION INPUT ;
    USE SIGNAL ;
    PORT
      LAYER M5 ;
        RECT  53.376 0 53.4 0.192 ;
    END
  END di[403]
  PIN di[404]
    DIRECTION INPUT ;
    USE SIGNAL ;
    PORT
      LAYER M3 ;
        RECT  53.496 0 53.514 0.144 ;
    END
  END di[404]
  PIN di[405]
    DIRECTION INPUT ;
    USE SIGNAL ;
    PORT
      LAYER M5 ;
        RECT  53.616 0 53.64 0.192 ;
    END
  END di[405]
  PIN di[406]
    DIRECTION INPUT ;
    USE SIGNAL ;
    PORT
      LAYER M3 ;
        RECT  53.748 0 53.766 0.144 ;
    END
  END di[406]
  PIN di[407]
    DIRECTION INPUT ;
    USE SIGNAL ;
    PORT
      LAYER M5 ;
        RECT  53.856 0 53.88 0.192 ;
    END
  END di[407]
  PIN di[408]
    DIRECTION INPUT ;
    USE SIGNAL ;
    PORT
      LAYER M3 ;
        RECT  54 0 54.018 0.144 ;
    END
  END di[408]
  PIN di[409]
    DIRECTION INPUT ;
    USE SIGNAL ;
    PORT
      LAYER M5 ;
        RECT  54.096 0 54.12 0.192 ;
    END
  END di[409]
  PIN di[40]
    DIRECTION INPUT ;
    USE SIGNAL ;
    PORT
      LAYER M3 ;
        RECT  9.252 0 9.27 0.144 ;
    END
  END di[40]
  PIN di[410]
    DIRECTION INPUT ;
    USE SIGNAL ;
    PORT
      LAYER M3 ;
        RECT  54.252 0 54.27 0.144 ;
    END
  END di[410]
  PIN di[411]
    DIRECTION INPUT ;
    USE SIGNAL ;
    PORT
      LAYER M5 ;
        RECT  54.336 0 54.36 0.192 ;
    END
  END di[411]
  PIN di[412]
    DIRECTION INPUT ;
    USE SIGNAL ;
    PORT
      LAYER M3 ;
        RECT  54.468 0 54.486 0.144 ;
    END
  END di[412]
  PIN di[413]
    DIRECTION INPUT ;
    USE SIGNAL ;
    PORT
      LAYER M5 ;
        RECT  54.624 0 54.648 0.192 ;
    END
  END di[413]
  PIN di[414]
    DIRECTION INPUT ;
    USE SIGNAL ;
    PORT
      LAYER M3 ;
        RECT  54.72 0 54.738 0.144 ;
    END
  END di[414]
  PIN di[415]
    DIRECTION INPUT ;
    USE SIGNAL ;
    PORT
      LAYER M5 ;
        RECT  54.864 0 54.888 0.192 ;
    END
  END di[415]
  PIN di[416]
    DIRECTION INPUT ;
    USE SIGNAL ;
    PORT
      LAYER M3 ;
        RECT  54.972 0 54.99 0.144 ;
    END
  END di[416]
  PIN di[417]
    DIRECTION INPUT ;
    USE SIGNAL ;
    PORT
      LAYER M5 ;
        RECT  55.104 0 55.128 0.192 ;
    END
  END di[417]
  PIN di[418]
    DIRECTION INPUT ;
    USE SIGNAL ;
    PORT
      LAYER M3 ;
        RECT  55.224 0 55.242 0.144 ;
    END
  END di[418]
  PIN di[419]
    DIRECTION INPUT ;
    USE SIGNAL ;
    PORT
      LAYER M5 ;
        RECT  55.344 0 55.368 0.192 ;
    END
  END di[419]
  PIN di[41]
    DIRECTION INPUT ;
    USE SIGNAL ;
    PORT
      LAYER M5 ;
        RECT  9.36 0 9.384 0.192 ;
    END
  END di[41]
  PIN di[420]
    DIRECTION INPUT ;
    USE SIGNAL ;
    PORT
      LAYER M3 ;
        RECT  55.44 0 55.458 0.144 ;
    END
  END di[420]
  PIN di[421]
    DIRECTION INPUT ;
    USE SIGNAL ;
    PORT
      LAYER M5 ;
        RECT  55.584 0 55.608 0.192 ;
    END
  END di[421]
  PIN di[422]
    DIRECTION INPUT ;
    USE SIGNAL ;
    PORT
      LAYER M3 ;
        RECT  55.692 0 55.71 0.144 ;
    END
  END di[422]
  PIN di[423]
    DIRECTION INPUT ;
    USE SIGNAL ;
    PORT
      LAYER M5 ;
        RECT  55.824 0 55.848 0.192 ;
    END
  END di[423]
  PIN di[424]
    DIRECTION INPUT ;
    USE SIGNAL ;
    PORT
      LAYER M3 ;
        RECT  55.944 0 55.962 0.144 ;
    END
  END di[424]
  PIN di[425]
    DIRECTION INPUT ;
    USE SIGNAL ;
    PORT
      LAYER M5 ;
        RECT  56.064 0 56.088 0.192 ;
    END
  END di[425]
  PIN di[426]
    DIRECTION INPUT ;
    USE SIGNAL ;
    PORT
      LAYER M3 ;
        RECT  56.196 0 56.214 0.144 ;
    END
  END di[426]
  PIN di[427]
    DIRECTION INPUT ;
    USE SIGNAL ;
    PORT
      LAYER M5 ;
        RECT  56.304 0 56.328 0.192 ;
    END
  END di[427]
  PIN di[428]
    DIRECTION INPUT ;
    USE SIGNAL ;
    PORT
      LAYER M3 ;
        RECT  56.412 0 56.43 0.144 ;
    END
  END di[428]
  PIN di[429]
    DIRECTION INPUT ;
    USE SIGNAL ;
    PORT
      LAYER M5 ;
        RECT  56.544 0 56.568 0.192 ;
    END
  END di[429]
  PIN di[42]
    DIRECTION INPUT ;
    USE SIGNAL ;
    PORT
      LAYER M3 ;
        RECT  9.468 0 9.486 0.144 ;
    END
  END di[42]
  PIN di[430]
    DIRECTION INPUT ;
    USE SIGNAL ;
    PORT
      LAYER M3 ;
        RECT  56.664 0 56.682 0.144 ;
    END
  END di[430]
  PIN di[431]
    DIRECTION INPUT ;
    USE SIGNAL ;
    PORT
      LAYER M5 ;
        RECT  56.784 0 56.808 0.192 ;
    END
  END di[431]
  PIN di[432]
    DIRECTION INPUT ;
    USE SIGNAL ;
    PORT
      LAYER M3 ;
        RECT  56.916 0 56.934 0.144 ;
    END
  END di[432]
  PIN di[433]
    DIRECTION INPUT ;
    USE SIGNAL ;
    PORT
      LAYER M5 ;
        RECT  57.024 0 57.048 0.192 ;
    END
  END di[433]
  PIN di[434]
    DIRECTION INPUT ;
    USE SIGNAL ;
    PORT
      LAYER M3 ;
        RECT  57.168 0 57.186 0.144 ;
    END
  END di[434]
  PIN di[435]
    DIRECTION INPUT ;
    USE SIGNAL ;
    PORT
      LAYER M5 ;
        RECT  57.264 0 57.288 0.192 ;
    END
  END di[435]
  PIN di[436]
    DIRECTION INPUT ;
    USE SIGNAL ;
    PORT
      LAYER M3 ;
        RECT  57.42 0 57.438 0.144 ;
    END
  END di[436]
  PIN di[437]
    DIRECTION INPUT ;
    USE SIGNAL ;
    PORT
      LAYER M5 ;
        RECT  57.504 0 57.528 0.192 ;
    END
  END di[437]
  PIN di[438]
    DIRECTION INPUT ;
    USE SIGNAL ;
    PORT
      LAYER M3 ;
        RECT  57.636 0 57.654 0.144 ;
    END
  END di[438]
  PIN di[439]
    DIRECTION INPUT ;
    USE SIGNAL ;
    PORT
      LAYER M5 ;
        RECT  57.744 0 57.768 0.192 ;
    END
  END di[439]
  PIN di[43]
    DIRECTION INPUT ;
    USE SIGNAL ;
    PORT
      LAYER M5 ;
        RECT  9.6 0 9.624 0.192 ;
    END
  END di[43]
  PIN di[440]
    DIRECTION INPUT ;
    USE SIGNAL ;
    PORT
      LAYER M3 ;
        RECT  57.888 0 57.906 0.144 ;
    END
  END di[440]
  PIN di[441]
    DIRECTION INPUT ;
    USE SIGNAL ;
    PORT
      LAYER M5 ;
        RECT  58.032 0 58.056 0.192 ;
    END
  END di[441]
  PIN di[442]
    DIRECTION INPUT ;
    USE SIGNAL ;
    PORT
      LAYER M3 ;
        RECT  58.14 0 58.158 0.144 ;
    END
  END di[442]
  PIN di[443]
    DIRECTION INPUT ;
    USE SIGNAL ;
    PORT
      LAYER M5 ;
        RECT  58.272 0 58.296 0.192 ;
    END
  END di[443]
  PIN di[444]
    DIRECTION INPUT ;
    USE SIGNAL ;
    PORT
      LAYER M3 ;
        RECT  58.392 0 58.41 0.144 ;
    END
  END di[444]
  PIN di[445]
    DIRECTION INPUT ;
    USE SIGNAL ;
    PORT
      LAYER M5 ;
        RECT  58.512 0 58.536 0.192 ;
    END
  END di[445]
  PIN di[446]
    DIRECTION INPUT ;
    USE SIGNAL ;
    PORT
      LAYER M3 ;
        RECT  58.608 0 58.626 0.144 ;
    END
  END di[446]
  PIN di[447]
    DIRECTION INPUT ;
    USE SIGNAL ;
    PORT
      LAYER M5 ;
        RECT  58.752 0 58.776 0.192 ;
    END
  END di[447]
  PIN di[448]
    DIRECTION INPUT ;
    USE SIGNAL ;
    PORT
      LAYER M3 ;
        RECT  58.86 0 58.878 0.144 ;
    END
  END di[448]
  PIN di[449]
    DIRECTION INPUT ;
    USE SIGNAL ;
    PORT
      LAYER M5 ;
        RECT  58.992 0 59.016 0.192 ;
    END
  END di[449]
  PIN di[44]
    DIRECTION INPUT ;
    USE SIGNAL ;
    PORT
      LAYER M3 ;
        RECT  9.72 0 9.738 0.144 ;
    END
  END di[44]
  PIN di[450]
    DIRECTION INPUT ;
    USE SIGNAL ;
    PORT
      LAYER M3 ;
        RECT  59.112 0 59.13 0.144 ;
    END
  END di[450]
  PIN di[451]
    DIRECTION INPUT ;
    USE SIGNAL ;
    PORT
      LAYER M5 ;
        RECT  59.232 0 59.256 0.192 ;
    END
  END di[451]
  PIN di[452]
    DIRECTION INPUT ;
    USE SIGNAL ;
    PORT
      LAYER M3 ;
        RECT  59.364 0 59.382 0.144 ;
    END
  END di[452]
  PIN di[453]
    DIRECTION INPUT ;
    USE SIGNAL ;
    PORT
      LAYER M5 ;
        RECT  59.472 0 59.496 0.192 ;
    END
  END di[453]
  PIN di[454]
    DIRECTION INPUT ;
    USE SIGNAL ;
    PORT
      LAYER M3 ;
        RECT  59.58 0 59.598 0.144 ;
    END
  END di[454]
  PIN di[455]
    DIRECTION INPUT ;
    USE SIGNAL ;
    PORT
      LAYER M5 ;
        RECT  59.712 0 59.736 0.192 ;
    END
  END di[455]
  PIN di[456]
    DIRECTION INPUT ;
    USE SIGNAL ;
    PORT
      LAYER M3 ;
        RECT  59.832 0 59.85 0.144 ;
    END
  END di[456]
  PIN di[457]
    DIRECTION INPUT ;
    USE SIGNAL ;
    PORT
      LAYER M5 ;
        RECT  59.952 0 59.976 0.192 ;
    END
  END di[457]
  PIN di[458]
    DIRECTION INPUT ;
    USE SIGNAL ;
    PORT
      LAYER M3 ;
        RECT  60.084 0 60.102 0.144 ;
    END
  END di[458]
  PIN di[459]
    DIRECTION INPUT ;
    USE SIGNAL ;
    PORT
      LAYER M5 ;
        RECT  60.192 0 60.216 0.192 ;
    END
  END di[459]
  PIN di[45]
    DIRECTION INPUT ;
    USE SIGNAL ;
    PORT
      LAYER M5 ;
        RECT  9.84 0 9.864 0.192 ;
    END
  END di[45]
  PIN di[460]
    DIRECTION INPUT ;
    USE SIGNAL ;
    PORT
      LAYER M3 ;
        RECT  60.336 0 60.354 0.144 ;
    END
  END di[460]
  PIN di[461]
    DIRECTION INPUT ;
    USE SIGNAL ;
    PORT
      LAYER M5 ;
        RECT  60.432 0 60.456 0.192 ;
    END
  END di[461]
  PIN di[462]
    DIRECTION INPUT ;
    USE SIGNAL ;
    PORT
      LAYER M3 ;
        RECT  60.552 0 60.57 0.144 ;
    END
  END di[462]
  PIN di[463]
    DIRECTION INPUT ;
    USE SIGNAL ;
    PORT
      LAYER M5 ;
        RECT  60.672 0 60.696 0.192 ;
    END
  END di[463]
  PIN di[464]
    DIRECTION INPUT ;
    USE SIGNAL ;
    PORT
      LAYER M3 ;
        RECT  60.804 0 60.822 0.144 ;
    END
  END di[464]
  PIN di[465]
    DIRECTION INPUT ;
    USE SIGNAL ;
    PORT
      LAYER M5 ;
        RECT  60.912 0 60.936 0.192 ;
    END
  END di[465]
  PIN di[466]
    DIRECTION INPUT ;
    USE SIGNAL ;
    PORT
      LAYER M3 ;
        RECT  61.056 0 61.074 0.144 ;
    END
  END di[466]
  PIN di[467]
    DIRECTION INPUT ;
    USE SIGNAL ;
    PORT
      LAYER M5 ;
        RECT  61.152 0 61.176 0.192 ;
    END
  END di[467]
  PIN di[468]
    DIRECTION INPUT ;
    USE SIGNAL ;
    PORT
      LAYER M3 ;
        RECT  61.308 0 61.326 0.144 ;
    END
  END di[468]
  PIN di[469]
    DIRECTION INPUT ;
    USE SIGNAL ;
    PORT
      LAYER M5 ;
        RECT  61.392 0 61.416 0.192 ;
    END
  END di[469]
  PIN di[46]
    DIRECTION INPUT ;
    USE SIGNAL ;
    PORT
      LAYER M3 ;
        RECT  9.972 0 9.99 0.144 ;
    END
  END di[46]
  PIN di[470]
    DIRECTION INPUT ;
    USE SIGNAL ;
    PORT
      LAYER M3 ;
        RECT  61.524 0 61.542 0.144 ;
    END
  END di[470]
  PIN di[471]
    DIRECTION INPUT ;
    USE SIGNAL ;
    PORT
      LAYER M5 ;
        RECT  61.68 0 61.704 0.192 ;
    END
  END di[471]
  PIN di[472]
    DIRECTION INPUT ;
    USE SIGNAL ;
    PORT
      LAYER M3 ;
        RECT  61.776 0 61.794 0.144 ;
    END
  END di[472]
  PIN di[473]
    DIRECTION INPUT ;
    USE SIGNAL ;
    PORT
      LAYER M5 ;
        RECT  61.92 0 61.944 0.192 ;
    END
  END di[473]
  PIN di[474]
    DIRECTION INPUT ;
    USE SIGNAL ;
    PORT
      LAYER M3 ;
        RECT  62.028 0 62.046 0.144 ;
    END
  END di[474]
  PIN di[475]
    DIRECTION INPUT ;
    USE SIGNAL ;
    PORT
      LAYER M5 ;
        RECT  62.16 0 62.184 0.192 ;
    END
  END di[475]
  PIN di[476]
    DIRECTION INPUT ;
    USE SIGNAL ;
    PORT
      LAYER M3 ;
        RECT  62.28 0 62.298 0.144 ;
    END
  END di[476]
  PIN di[477]
    DIRECTION INPUT ;
    USE SIGNAL ;
    PORT
      LAYER M5 ;
        RECT  62.4 0 62.424 0.192 ;
    END
  END di[477]
  PIN di[478]
    DIRECTION INPUT ;
    USE SIGNAL ;
    PORT
      LAYER M3 ;
        RECT  62.496 0 62.514 0.144 ;
    END
  END di[478]
  PIN di[479]
    DIRECTION INPUT ;
    USE SIGNAL ;
    PORT
      LAYER M5 ;
        RECT  62.64 0 62.664 0.192 ;
    END
  END di[479]
  PIN di[47]
    DIRECTION INPUT ;
    USE SIGNAL ;
    PORT
      LAYER M5 ;
        RECT  10.08 0 10.104 0.192 ;
    END
  END di[47]
  PIN di[480]
    DIRECTION INPUT ;
    USE SIGNAL ;
    PORT
      LAYER M3 ;
        RECT  62.748 0 62.766 0.144 ;
    END
  END di[480]
  PIN di[481]
    DIRECTION INPUT ;
    USE SIGNAL ;
    PORT
      LAYER M5 ;
        RECT  62.88 0 62.904 0.192 ;
    END
  END di[481]
  PIN di[482]
    DIRECTION INPUT ;
    USE SIGNAL ;
    PORT
      LAYER M3 ;
        RECT  63 0 63.018 0.144 ;
    END
  END di[482]
  PIN di[483]
    DIRECTION INPUT ;
    USE SIGNAL ;
    PORT
      LAYER M5 ;
        RECT  63.12 0 63.144 0.192 ;
    END
  END di[483]
  PIN di[484]
    DIRECTION INPUT ;
    USE SIGNAL ;
    PORT
      LAYER M3 ;
        RECT  63.252 0 63.27 0.144 ;
    END
  END di[484]
  PIN di[485]
    DIRECTION INPUT ;
    USE SIGNAL ;
    PORT
      LAYER M5 ;
        RECT  63.36 0 63.384 0.192 ;
    END
  END di[485]
  PIN di[486]
    DIRECTION INPUT ;
    USE SIGNAL ;
    PORT
      LAYER M3 ;
        RECT  63.468 0 63.486 0.144 ;
    END
  END di[486]
  PIN di[487]
    DIRECTION INPUT ;
    USE SIGNAL ;
    PORT
      LAYER M5 ;
        RECT  63.6 0 63.624 0.192 ;
    END
  END di[487]
  PIN di[488]
    DIRECTION INPUT ;
    USE SIGNAL ;
    PORT
      LAYER M3 ;
        RECT  63.72 0 63.738 0.144 ;
    END
  END di[488]
  PIN di[489]
    DIRECTION INPUT ;
    USE SIGNAL ;
    PORT
      LAYER M5 ;
        RECT  63.84 0 63.864 0.192 ;
    END
  END di[489]
  PIN di[48]
    DIRECTION INPUT ;
    USE SIGNAL ;
    PORT
      LAYER M3 ;
        RECT  10.224 0 10.242 0.144 ;
    END
  END di[48]
  PIN di[490]
    DIRECTION INPUT ;
    USE SIGNAL ;
    PORT
      LAYER M3 ;
        RECT  63.972 0 63.99 0.144 ;
    END
  END di[490]
  PIN di[491]
    DIRECTION INPUT ;
    USE SIGNAL ;
    PORT
      LAYER M5 ;
        RECT  64.08 0 64.104 0.192 ;
    END
  END di[491]
  PIN di[492]
    DIRECTION INPUT ;
    USE SIGNAL ;
    PORT
      LAYER M3 ;
        RECT  64.224 0 64.242 0.144 ;
    END
  END di[492]
  PIN di[493]
    DIRECTION INPUT ;
    USE SIGNAL ;
    PORT
      LAYER M5 ;
        RECT  64.32 0 64.344 0.192 ;
    END
  END di[493]
  PIN di[494]
    DIRECTION INPUT ;
    USE SIGNAL ;
    PORT
      LAYER M3 ;
        RECT  64.44 0 64.458 0.144 ;
    END
  END di[494]
  PIN di[495]
    DIRECTION INPUT ;
    USE SIGNAL ;
    PORT
      LAYER M5 ;
        RECT  64.56 0 64.584 0.192 ;
    END
  END di[495]
  PIN di[496]
    DIRECTION INPUT ;
    USE SIGNAL ;
    PORT
      LAYER M3 ;
        RECT  64.692 0 64.71 0.144 ;
    END
  END di[496]
  PIN di[497]
    DIRECTION INPUT ;
    USE SIGNAL ;
    PORT
      LAYER M5 ;
        RECT  64.8 0 64.824 0.192 ;
    END
  END di[497]
  PIN di[498]
    DIRECTION INPUT ;
    USE SIGNAL ;
    PORT
      LAYER M3 ;
        RECT  64.944 0 64.962 0.144 ;
    END
  END di[498]
  PIN di[499]
    DIRECTION INPUT ;
    USE SIGNAL ;
    PORT
      LAYER M5 ;
        RECT  65.04 0 65.064 0.192 ;
    END
  END di[499]
  PIN di[49]
    DIRECTION INPUT ;
    USE SIGNAL ;
    PORT
      LAYER M5 ;
        RECT  10.32 0 10.344 0.192 ;
    END
  END di[49]
  PIN di[4]
    DIRECTION INPUT ;
    USE SIGNAL ;
    PORT
      LAYER M3 ;
        RECT  4.86 0 4.878 0.144 ;
    END
  END di[4]
  PIN di[500]
    DIRECTION INPUT ;
    USE SIGNAL ;
    PORT
      LAYER M3 ;
        RECT  65.196 0 65.214 0.144 ;
    END
  END di[500]
  PIN di[501]
    DIRECTION INPUT ;
    USE SIGNAL ;
    PORT
      LAYER M5 ;
        RECT  65.328 0 65.352 0.192 ;
    END
  END di[501]
  PIN di[502]
    DIRECTION INPUT ;
    USE SIGNAL ;
    PORT
      LAYER M3 ;
        RECT  65.448 0 65.466 0.144 ;
    END
  END di[502]
  PIN di[503]
    DIRECTION INPUT ;
    USE SIGNAL ;
    PORT
      LAYER M5 ;
        RECT  65.568 0 65.592 0.192 ;
    END
  END di[503]
  PIN di[504]
    DIRECTION INPUT ;
    USE SIGNAL ;
    PORT
      LAYER M3 ;
        RECT  65.664 0 65.682 0.144 ;
    END
  END di[504]
  PIN di[505]
    DIRECTION INPUT ;
    USE SIGNAL ;
    PORT
      LAYER M5 ;
        RECT  65.808 0 65.832 0.192 ;
    END
  END di[505]
  PIN di[506]
    DIRECTION INPUT ;
    USE SIGNAL ;
    PORT
      LAYER M3 ;
        RECT  65.916 0 65.934 0.144 ;
    END
  END di[506]
  PIN di[507]
    DIRECTION INPUT ;
    USE SIGNAL ;
    PORT
      LAYER M5 ;
        RECT  66.048 0 66.072 0.192 ;
    END
  END di[507]
  PIN di[508]
    DIRECTION INPUT ;
    USE SIGNAL ;
    PORT
      LAYER M3 ;
        RECT  66.168 0 66.186 0.144 ;
    END
  END di[508]
  PIN di[509]
    DIRECTION INPUT ;
    USE SIGNAL ;
    PORT
      LAYER M5 ;
        RECT  66.288 0 66.312 0.192 ;
    END
  END di[509]
  PIN di[50]
    DIRECTION INPUT ;
    USE SIGNAL ;
    PORT
      LAYER M3 ;
        RECT  10.44 0 10.458 0.144 ;
    END
  END di[50]
  PIN di[510]
    DIRECTION INPUT ;
    USE SIGNAL ;
    PORT
      LAYER M3 ;
        RECT  66.42 0 66.438 0.144 ;
    END
  END di[510]
  PIN di[511]
    DIRECTION INPUT ;
    USE SIGNAL ;
    PORT
      LAYER M5 ;
        RECT  66.528 0 66.552 0.192 ;
    END
  END di[511]
  PIN di[512]
    DIRECTION INPUT ;
    USE SIGNAL ;
    PORT
      LAYER M3 ;
        RECT  66.636 0 66.654 0.144 ;
    END
  END di[512]
  PIN di[513]
    DIRECTION INPUT ;
    USE SIGNAL ;
    PORT
      LAYER M5 ;
        RECT  66.768 0 66.792 0.192 ;
    END
  END di[513]
  PIN di[514]
    DIRECTION INPUT ;
    USE SIGNAL ;
    PORT
      LAYER M3 ;
        RECT  66.888 0 66.906 0.144 ;
    END
  END di[514]
  PIN di[51]
    DIRECTION INPUT ;
    USE SIGNAL ;
    PORT
      LAYER M5 ;
        RECT  10.56 0 10.584 0.192 ;
    END
  END di[51]
  PIN di[52]
    DIRECTION INPUT ;
    USE SIGNAL ;
    PORT
      LAYER M3 ;
        RECT  10.692 0 10.71 0.144 ;
    END
  END di[52]
  PIN di[53]
    DIRECTION INPUT ;
    USE SIGNAL ;
    PORT
      LAYER M5 ;
        RECT  10.8 0 10.824 0.192 ;
    END
  END di[53]
  PIN di[54]
    DIRECTION INPUT ;
    USE SIGNAL ;
    PORT
      LAYER M3 ;
        RECT  10.944 0 10.962 0.144 ;
    END
  END di[54]
  PIN di[55]
    DIRECTION INPUT ;
    USE SIGNAL ;
    PORT
      LAYER M5 ;
        RECT  11.04 0 11.064 0.192 ;
    END
  END di[55]
  PIN di[56]
    DIRECTION INPUT ;
    USE SIGNAL ;
    PORT
      LAYER M3 ;
        RECT  11.196 0 11.214 0.144 ;
    END
  END di[56]
  PIN di[57]
    DIRECTION INPUT ;
    USE SIGNAL ;
    PORT
      LAYER M5 ;
        RECT  11.28 0 11.304 0.192 ;
    END
  END di[57]
  PIN di[58]
    DIRECTION INPUT ;
    USE SIGNAL ;
    PORT
      LAYER M3 ;
        RECT  11.412 0 11.43 0.144 ;
    END
  END di[58]
  PIN di[59]
    DIRECTION INPUT ;
    USE SIGNAL ;
    PORT
      LAYER M5 ;
        RECT  11.568 0 11.592 0.192 ;
    END
  END di[59]
  PIN di[5]
    DIRECTION INPUT ;
    USE SIGNAL ;
    PORT
      LAYER M5 ;
        RECT  4.992 0 5.016 0.192 ;
    END
  END di[5]
  PIN di[60]
    DIRECTION INPUT ;
    USE SIGNAL ;
    PORT
      LAYER M3 ;
        RECT  11.664 0 11.682 0.144 ;
    END
  END di[60]
  PIN di[61]
    DIRECTION INPUT ;
    USE SIGNAL ;
    PORT
      LAYER M5 ;
        RECT  11.808 0 11.832 0.192 ;
    END
  END di[61]
  PIN di[62]
    DIRECTION INPUT ;
    USE SIGNAL ;
    PORT
      LAYER M3 ;
        RECT  11.916 0 11.934 0.144 ;
    END
  END di[62]
  PIN di[63]
    DIRECTION INPUT ;
    USE SIGNAL ;
    PORT
      LAYER M5 ;
        RECT  12.048 0 12.072 0.192 ;
    END
  END di[63]
  PIN di[64]
    DIRECTION INPUT ;
    USE SIGNAL ;
    PORT
      LAYER M3 ;
        RECT  12.168 0 12.186 0.144 ;
    END
  END di[64]
  PIN di[65]
    DIRECTION INPUT ;
    USE SIGNAL ;
    PORT
      LAYER M5 ;
        RECT  12.288 0 12.312 0.192 ;
    END
  END di[65]
  PIN di[66]
    DIRECTION INPUT ;
    USE SIGNAL ;
    PORT
      LAYER M3 ;
        RECT  12.384 0 12.402 0.144 ;
    END
  END di[66]
  PIN di[67]
    DIRECTION INPUT ;
    USE SIGNAL ;
    PORT
      LAYER M5 ;
        RECT  12.528 0 12.552 0.192 ;
    END
  END di[67]
  PIN di[68]
    DIRECTION INPUT ;
    USE SIGNAL ;
    PORT
      LAYER M3 ;
        RECT  12.636 0 12.654 0.144 ;
    END
  END di[68]
  PIN di[69]
    DIRECTION INPUT ;
    USE SIGNAL ;
    PORT
      LAYER M5 ;
        RECT  12.768 0 12.792 0.192 ;
    END
  END di[69]
  PIN di[6]
    DIRECTION INPUT ;
    USE SIGNAL ;
    PORT
      LAYER M3 ;
        RECT  5.112 0 5.13 0.144 ;
    END
  END di[6]
  PIN di[70]
    DIRECTION INPUT ;
    USE SIGNAL ;
    PORT
      LAYER M3 ;
        RECT  12.888 0 12.906 0.144 ;
    END
  END di[70]
  PIN di[71]
    DIRECTION INPUT ;
    USE SIGNAL ;
    PORT
      LAYER M5 ;
        RECT  13.008 0 13.032 0.192 ;
    END
  END di[71]
  PIN di[72]
    DIRECTION INPUT ;
    USE SIGNAL ;
    PORT
      LAYER M3 ;
        RECT  13.14 0 13.158 0.144 ;
    END
  END di[72]
  PIN di[73]
    DIRECTION INPUT ;
    USE SIGNAL ;
    PORT
      LAYER M5 ;
        RECT  13.248 0 13.272 0.192 ;
    END
  END di[73]
  PIN di[74]
    DIRECTION INPUT ;
    USE SIGNAL ;
    PORT
      LAYER M3 ;
        RECT  13.356 0 13.374 0.144 ;
    END
  END di[74]
  PIN di[75]
    DIRECTION INPUT ;
    USE SIGNAL ;
    PORT
      LAYER M5 ;
        RECT  13.488 0 13.512 0.192 ;
    END
  END di[75]
  PIN di[76]
    DIRECTION INPUT ;
    USE SIGNAL ;
    PORT
      LAYER M3 ;
        RECT  13.608 0 13.626 0.144 ;
    END
  END di[76]
  PIN di[77]
    DIRECTION INPUT ;
    USE SIGNAL ;
    PORT
      LAYER M5 ;
        RECT  13.728 0 13.752 0.192 ;
    END
  END di[77]
  PIN di[78]
    DIRECTION INPUT ;
    USE SIGNAL ;
    PORT
      LAYER M3 ;
        RECT  13.86 0 13.878 0.144 ;
    END
  END di[78]
  PIN di[79]
    DIRECTION INPUT ;
    USE SIGNAL ;
    PORT
      LAYER M5 ;
        RECT  13.968 0 13.992 0.192 ;
    END
  END di[79]
  PIN di[7]
    DIRECTION INPUT ;
    USE SIGNAL ;
    PORT
      LAYER M5 ;
        RECT  5.232 0 5.256 0.192 ;
    END
  END di[7]
  PIN di[80]
    DIRECTION INPUT ;
    USE SIGNAL ;
    PORT
      LAYER M3 ;
        RECT  14.112 0 14.13 0.144 ;
    END
  END di[80]
  PIN di[81]
    DIRECTION INPUT ;
    USE SIGNAL ;
    PORT
      LAYER M5 ;
        RECT  14.208 0 14.232 0.192 ;
    END
  END di[81]
  PIN di[82]
    DIRECTION INPUT ;
    USE SIGNAL ;
    PORT
      LAYER M3 ;
        RECT  14.328 0 14.346 0.144 ;
    END
  END di[82]
  PIN di[83]
    DIRECTION INPUT ;
    USE SIGNAL ;
    PORT
      LAYER M5 ;
        RECT  14.448 0 14.472 0.192 ;
    END
  END di[83]
  PIN di[84]
    DIRECTION INPUT ;
    USE SIGNAL ;
    PORT
      LAYER M3 ;
        RECT  14.58 0 14.598 0.144 ;
    END
  END di[84]
  PIN di[85]
    DIRECTION INPUT ;
    USE SIGNAL ;
    PORT
      LAYER M5 ;
        RECT  14.688 0 14.712 0.192 ;
    END
  END di[85]
  PIN di[86]
    DIRECTION INPUT ;
    USE SIGNAL ;
    PORT
      LAYER M3 ;
        RECT  14.832 0 14.85 0.144 ;
    END
  END di[86]
  PIN di[87]
    DIRECTION INPUT ;
    USE SIGNAL ;
    PORT
      LAYER M5 ;
        RECT  14.928 0 14.952 0.192 ;
    END
  END di[87]
  PIN di[88]
    DIRECTION INPUT ;
    USE SIGNAL ;
    PORT
      LAYER M3 ;
        RECT  15.084 0 15.102 0.144 ;
    END
  END di[88]
  PIN di[89]
    DIRECTION INPUT ;
    USE SIGNAL ;
    PORT
      LAYER M5 ;
        RECT  15.216 0 15.24 0.192 ;
    END
  END di[89]
  PIN di[8]
    DIRECTION INPUT ;
    USE SIGNAL ;
    PORT
      LAYER M3 ;
        RECT  5.328 0 5.346 0.144 ;
    END
  END di[8]
  PIN di[90]
    DIRECTION INPUT ;
    USE SIGNAL ;
    PORT
      LAYER M3 ;
        RECT  15.336 0 15.354 0.144 ;
    END
  END di[90]
  PIN di[91]
    DIRECTION INPUT ;
    USE SIGNAL ;
    PORT
      LAYER M5 ;
        RECT  15.456 0 15.48 0.192 ;
    END
  END di[91]
  PIN di[92]
    DIRECTION INPUT ;
    USE SIGNAL ;
    PORT
      LAYER M3 ;
        RECT  15.552 0 15.57 0.144 ;
    END
  END di[92]
  PIN di[93]
    DIRECTION INPUT ;
    USE SIGNAL ;
    PORT
      LAYER M5 ;
        RECT  15.696 0 15.72 0.192 ;
    END
  END di[93]
  PIN di[94]
    DIRECTION INPUT ;
    USE SIGNAL ;
    PORT
      LAYER M3 ;
        RECT  15.804 0 15.822 0.144 ;
    END
  END di[94]
  PIN di[95]
    DIRECTION INPUT ;
    USE SIGNAL ;
    PORT
      LAYER M5 ;
        RECT  15.936 0 15.96 0.192 ;
    END
  END di[95]
  PIN di[96]
    DIRECTION INPUT ;
    USE SIGNAL ;
    PORT
      LAYER M3 ;
        RECT  16.056 0 16.074 0.144 ;
    END
  END di[96]
  PIN di[97]
    DIRECTION INPUT ;
    USE SIGNAL ;
    PORT
      LAYER M5 ;
        RECT  16.176 0 16.2 0.192 ;
    END
  END di[97]
  PIN di[98]
    DIRECTION INPUT ;
    USE SIGNAL ;
    PORT
      LAYER M3 ;
        RECT  16.308 0 16.326 0.144 ;
    END
  END di[98]
  PIN di[99]
    DIRECTION INPUT ;
    USE SIGNAL ;
    PORT
      LAYER M5 ;
        RECT  16.416 0 16.44 0.192 ;
    END
  END di[99]
  PIN di[9]
    DIRECTION INPUT ;
    USE SIGNAL ;
    PORT
      LAYER M5 ;
        RECT  5.472 0 5.496 0.192 ;
    END
  END di[9]
  PIN dq[0]
    DIRECTION OUTPUT ;
    USE SIGNAL ;
    PORT
      LAYER M3 ;
        RECT  4.356 36.576 4.374 36.72 ;
    END
  END dq[0]
  PIN dq[100]
    DIRECTION OUTPUT ;
    USE SIGNAL ;
    PORT
      LAYER M3 ;
        RECT  16.524 36.576 16.542 36.72 ;
    END
  END dq[100]
  PIN dq[101]
    DIRECTION OUTPUT ;
    USE SIGNAL ;
    PORT
      LAYER M5 ;
        RECT  16.656 36.528 16.68 36.72 ;
    END
  END dq[101]
  PIN dq[102]
    DIRECTION OUTPUT ;
    USE SIGNAL ;
    PORT
      LAYER M3 ;
        RECT  16.776 36.576 16.794 36.72 ;
    END
  END dq[102]
  PIN dq[103]
    DIRECTION OUTPUT ;
    USE SIGNAL ;
    PORT
      LAYER M5 ;
        RECT  16.896 36.528 16.92 36.72 ;
    END
  END dq[103]
  PIN dq[104]
    DIRECTION OUTPUT ;
    USE SIGNAL ;
    PORT
      LAYER M3 ;
        RECT  17.028 36.576 17.046 36.72 ;
    END
  END dq[104]
  PIN dq[105]
    DIRECTION OUTPUT ;
    USE SIGNAL ;
    PORT
      LAYER M5 ;
        RECT  17.136 36.528 17.16 36.72 ;
    END
  END dq[105]
  PIN dq[106]
    DIRECTION OUTPUT ;
    USE SIGNAL ;
    PORT
      LAYER M3 ;
        RECT  17.28 36.576 17.298 36.72 ;
    END
  END dq[106]
  PIN dq[107]
    DIRECTION OUTPUT ;
    USE SIGNAL ;
    PORT
      LAYER M5 ;
        RECT  17.376 36.528 17.4 36.72 ;
    END
  END dq[107]
  PIN dq[108]
    DIRECTION OUTPUT ;
    USE SIGNAL ;
    PORT
      LAYER M3 ;
        RECT  17.496 36.576 17.514 36.72 ;
    END
  END dq[108]
  PIN dq[109]
    DIRECTION OUTPUT ;
    USE SIGNAL ;
    PORT
      LAYER M5 ;
        RECT  17.616 36.528 17.64 36.72 ;
    END
  END dq[109]
  PIN dq[10]
    DIRECTION OUTPUT ;
    USE SIGNAL ;
    PORT
      LAYER M3 ;
        RECT  5.58 36.576 5.598 36.72 ;
    END
  END dq[10]
  PIN dq[110]
    DIRECTION OUTPUT ;
    USE SIGNAL ;
    PORT
      LAYER M3 ;
        RECT  17.748 36.576 17.766 36.72 ;
    END
  END dq[110]
  PIN dq[111]
    DIRECTION OUTPUT ;
    USE SIGNAL ;
    PORT
      LAYER M5 ;
        RECT  17.856 36.528 17.88 36.72 ;
    END
  END dq[111]
  PIN dq[112]
    DIRECTION OUTPUT ;
    USE SIGNAL ;
    PORT
      LAYER M3 ;
        RECT  18 36.576 18.018 36.72 ;
    END
  END dq[112]
  PIN dq[113]
    DIRECTION OUTPUT ;
    USE SIGNAL ;
    PORT
      LAYER M5 ;
        RECT  18.096 36.528 18.12 36.72 ;
    END
  END dq[113]
  PIN dq[114]
    DIRECTION OUTPUT ;
    USE SIGNAL ;
    PORT
      LAYER M3 ;
        RECT  18.252 36.576 18.27 36.72 ;
    END
  END dq[114]
  PIN dq[115]
    DIRECTION OUTPUT ;
    USE SIGNAL ;
    PORT
      LAYER M5 ;
        RECT  18.336 36.528 18.36 36.72 ;
    END
  END dq[115]
  PIN dq[116]
    DIRECTION OUTPUT ;
    USE SIGNAL ;
    PORT
      LAYER M3 ;
        RECT  18.468 36.576 18.486 36.72 ;
    END
  END dq[116]
  PIN dq[117]
    DIRECTION OUTPUT ;
    USE SIGNAL ;
    PORT
      LAYER M5 ;
        RECT  18.576 36.528 18.6 36.72 ;
    END
  END dq[117]
  PIN dq[118]
    DIRECTION OUTPUT ;
    USE SIGNAL ;
    PORT
      LAYER M3 ;
        RECT  18.72 36.576 18.738 36.72 ;
    END
    PORT
      LAYER M3 ;
        RECT  18.648 36.588 18.774 36.653 ;
    END
  END dq[118]
  PIN dq[119]
    DIRECTION OUTPUT ;
    USE SIGNAL ;
    PORT
      LAYER M5 ;
        RECT  18.864 36.528 18.888 36.72 ;
    END
  END dq[119]
  PIN dq[11]
    DIRECTION OUTPUT ;
    USE SIGNAL ;
    PORT
      LAYER M5 ;
        RECT  5.712 36.528 5.736 36.72 ;
    END
  END dq[11]
  PIN dq[120]
    DIRECTION OUTPUT ;
    USE SIGNAL ;
    PORT
      LAYER M3 ;
        RECT  18.972 36.576 18.99 36.72 ;
    END
  END dq[120]
  PIN dq[121]
    DIRECTION OUTPUT ;
    USE SIGNAL ;
    PORT
      LAYER M5 ;
        RECT  19.104 36.528 19.128 36.72 ;
    END
  END dq[121]
  PIN dq[122]
    DIRECTION OUTPUT ;
    USE SIGNAL ;
    PORT
      LAYER M3 ;
        RECT  19.224 36.576 19.242 36.72 ;
    END
  END dq[122]
  PIN dq[123]
    DIRECTION OUTPUT ;
    USE SIGNAL ;
    PORT
      LAYER M5 ;
        RECT  19.344 36.528 19.368 36.72 ;
    END
  END dq[123]
  PIN dq[124]
    DIRECTION OUTPUT ;
    USE SIGNAL ;
    PORT
      LAYER M3 ;
        RECT  19.44 36.576 19.458 36.72 ;
    END
  END dq[124]
  PIN dq[125]
    DIRECTION OUTPUT ;
    USE SIGNAL ;
    PORT
      LAYER M5 ;
        RECT  19.584 36.528 19.608 36.72 ;
    END
  END dq[125]
  PIN dq[126]
    DIRECTION OUTPUT ;
    USE SIGNAL ;
    PORT
      LAYER M3 ;
        RECT  19.692 36.576 19.71 36.72 ;
    END
  END dq[126]
  PIN dq[127]
    DIRECTION OUTPUT ;
    USE SIGNAL ;
    PORT
      LAYER M5 ;
        RECT  19.824 36.528 19.848 36.72 ;
    END
  END dq[127]
  PIN dq[128]
    DIRECTION OUTPUT ;
    USE SIGNAL ;
    PORT
      LAYER M3 ;
        RECT  19.944 36.576 19.962 36.72 ;
    END
  END dq[128]
  PIN dq[129]
    DIRECTION OUTPUT ;
    USE SIGNAL ;
    PORT
      LAYER M5 ;
        RECT  20.064 36.528 20.088 36.72 ;
    END
  END dq[129]
  PIN dq[12]
    DIRECTION OUTPUT ;
    USE SIGNAL ;
    PORT
      LAYER M3 ;
        RECT  5.832 36.576 5.85 36.72 ;
    END
  END dq[12]
  PIN dq[130]
    DIRECTION OUTPUT ;
    USE SIGNAL ;
    PORT
      LAYER M3 ;
        RECT  20.196 36.576 20.214 36.72 ;
    END
  END dq[130]
  PIN dq[131]
    DIRECTION OUTPUT ;
    USE SIGNAL ;
    PORT
      LAYER M5 ;
        RECT  20.304 36.528 20.328 36.72 ;
    END
  END dq[131]
  PIN dq[132]
    DIRECTION OUTPUT ;
    USE SIGNAL ;
    PORT
      LAYER M3 ;
        RECT  20.412 36.576 20.43 36.72 ;
    END
  END dq[132]
  PIN dq[133]
    DIRECTION OUTPUT ;
    USE SIGNAL ;
    PORT
      LAYER M5 ;
        RECT  20.544 36.528 20.568 36.72 ;
    END
  END dq[133]
  PIN dq[134]
    DIRECTION OUTPUT ;
    USE SIGNAL ;
    PORT
      LAYER M3 ;
        RECT  20.664 36.576 20.682 36.72 ;
    END
  END dq[134]
  PIN dq[135]
    DIRECTION OUTPUT ;
    USE SIGNAL ;
    PORT
      LAYER M5 ;
        RECT  20.784 36.528 20.808 36.72 ;
    END
  END dq[135]
  PIN dq[136]
    DIRECTION OUTPUT ;
    USE SIGNAL ;
    PORT
      LAYER M3 ;
        RECT  20.916 36.576 20.934 36.72 ;
    END
  END dq[136]
  PIN dq[137]
    DIRECTION OUTPUT ;
    USE SIGNAL ;
    PORT
      LAYER M5 ;
        RECT  21.024 36.528 21.048 36.72 ;
    END
  END dq[137]
  PIN dq[138]
    DIRECTION OUTPUT ;
    USE SIGNAL ;
    PORT
      LAYER M3 ;
        RECT  21.168 36.576 21.186 36.72 ;
    END
  END dq[138]
  PIN dq[139]
    DIRECTION OUTPUT ;
    USE SIGNAL ;
    PORT
      LAYER M5 ;
        RECT  21.264 36.528 21.288 36.72 ;
    END
  END dq[139]
  PIN dq[13]
    DIRECTION OUTPUT ;
    USE SIGNAL ;
    PORT
      LAYER M5 ;
        RECT  5.952 36.528 5.976 36.72 ;
    END
  END dq[13]
  PIN dq[140]
    DIRECTION OUTPUT ;
    USE SIGNAL ;
    PORT
      LAYER M3 ;
        RECT  21.384 36.576 21.402 36.72 ;
    END
  END dq[140]
  PIN dq[141]
    DIRECTION OUTPUT ;
    USE SIGNAL ;
    PORT
      LAYER M5 ;
        RECT  21.504 36.528 21.528 36.72 ;
    END
  END dq[141]
  PIN dq[142]
    DIRECTION OUTPUT ;
    USE SIGNAL ;
    PORT
      LAYER M3 ;
        RECT  21.636 36.576 21.654 36.72 ;
    END
  END dq[142]
  PIN dq[143]
    DIRECTION OUTPUT ;
    USE SIGNAL ;
    PORT
      LAYER M5 ;
        RECT  21.744 36.528 21.768 36.72 ;
    END
  END dq[143]
  PIN dq[144]
    DIRECTION OUTPUT ;
    USE SIGNAL ;
    PORT
      LAYER M3 ;
        RECT  21.888 36.576 21.906 36.72 ;
    END
  END dq[144]
  PIN dq[145]
    DIRECTION OUTPUT ;
    USE SIGNAL ;
    PORT
      LAYER M5 ;
        RECT  21.984 36.528 22.008 36.72 ;
    END
  END dq[145]
  PIN dq[146]
    DIRECTION OUTPUT ;
    USE SIGNAL ;
    PORT
      LAYER M3 ;
        RECT  22.14 36.576 22.158 36.72 ;
    END
  END dq[146]
  PIN dq[147]
    DIRECTION OUTPUT ;
    USE SIGNAL ;
    PORT
      LAYER M5 ;
        RECT  22.272 36.528 22.296 36.72 ;
    END
  END dq[147]
  PIN dq[148]
    DIRECTION OUTPUT ;
    USE SIGNAL ;
    PORT
      LAYER M3 ;
        RECT  22.356 36.576 22.374 36.72 ;
    END
  END dq[148]
  PIN dq[149]
    DIRECTION OUTPUT ;
    USE SIGNAL ;
    PORT
      LAYER M5 ;
        RECT  22.512 36.528 22.536 36.72 ;
    END
  END dq[149]
  PIN dq[14]
    DIRECTION OUTPUT ;
    USE SIGNAL ;
    PORT
      LAYER M3 ;
        RECT  6.084 36.576 6.102 36.72 ;
    END
  END dq[14]
  PIN dq[150]
    DIRECTION OUTPUT ;
    USE SIGNAL ;
    PORT
      LAYER M3 ;
        RECT  22.608 36.576 22.626 36.72 ;
    END
  END dq[150]
  PIN dq[151]
    DIRECTION OUTPUT ;
    USE SIGNAL ;
    PORT
      LAYER M5 ;
        RECT  22.752 36.528 22.776 36.72 ;
    END
  END dq[151]
  PIN dq[152]
    DIRECTION OUTPUT ;
    USE SIGNAL ;
    PORT
      LAYER M3 ;
        RECT  22.86 36.576 22.878 36.72 ;
    END
  END dq[152]
  PIN dq[153]
    DIRECTION OUTPUT ;
    USE SIGNAL ;
    PORT
      LAYER M5 ;
        RECT  22.992 36.528 23.016 36.72 ;
    END
  END dq[153]
  PIN dq[154]
    DIRECTION OUTPUT ;
    USE SIGNAL ;
    PORT
      LAYER M3 ;
        RECT  23.112 36.576 23.13 36.72 ;
    END
  END dq[154]
  PIN dq[155]
    DIRECTION OUTPUT ;
    USE SIGNAL ;
    PORT
      LAYER M5 ;
        RECT  23.232 36.528 23.256 36.72 ;
    END
  END dq[155]
  PIN dq[156]
    DIRECTION OUTPUT ;
    USE SIGNAL ;
    PORT
      LAYER M3 ;
        RECT  23.364 36.576 23.382 36.72 ;
    END
  END dq[156]
  PIN dq[157]
    DIRECTION OUTPUT ;
    USE SIGNAL ;
    PORT
      LAYER M5 ;
        RECT  23.472 36.528 23.496 36.72 ;
    END
  END dq[157]
  PIN dq[158]
    DIRECTION OUTPUT ;
    USE SIGNAL ;
    PORT
      LAYER M3 ;
        RECT  23.58 36.576 23.598 36.72 ;
    END
  END dq[158]
  PIN dq[159]
    DIRECTION OUTPUT ;
    USE SIGNAL ;
    PORT
      LAYER M5 ;
        RECT  23.712 36.528 23.736 36.72 ;
    END
  END dq[159]
  PIN dq[15]
    DIRECTION OUTPUT ;
    USE SIGNAL ;
    PORT
      LAYER M5 ;
        RECT  6.192 36.528 6.216 36.72 ;
    END
  END dq[15]
  PIN dq[160]
    DIRECTION OUTPUT ;
    USE SIGNAL ;
    PORT
      LAYER M3 ;
        RECT  23.832 36.576 23.85 36.72 ;
    END
  END dq[160]
  PIN dq[161]
    DIRECTION OUTPUT ;
    USE SIGNAL ;
    PORT
      LAYER M5 ;
        RECT  23.952 36.528 23.976 36.72 ;
    END
  END dq[161]
  PIN dq[162]
    DIRECTION OUTPUT ;
    USE SIGNAL ;
    PORT
      LAYER M3 ;
        RECT  24.084 36.576 24.102 36.72 ;
    END
  END dq[162]
  PIN dq[163]
    DIRECTION OUTPUT ;
    USE SIGNAL ;
    PORT
      LAYER M5 ;
        RECT  24.192 36.528 24.216 36.72 ;
    END
  END dq[163]
  PIN dq[164]
    DIRECTION OUTPUT ;
    USE SIGNAL ;
    PORT
      LAYER M3 ;
        RECT  24.336 36.576 24.354 36.72 ;
    END
  END dq[164]
  PIN dq[165]
    DIRECTION OUTPUT ;
    USE SIGNAL ;
    PORT
      LAYER M5 ;
        RECT  24.432 36.528 24.456 36.72 ;
    END
  END dq[165]
  PIN dq[166]
    DIRECTION OUTPUT ;
    USE SIGNAL ;
    PORT
      LAYER M3 ;
        RECT  24.552 36.576 24.57 36.72 ;
    END
  END dq[166]
  PIN dq[167]
    DIRECTION OUTPUT ;
    USE SIGNAL ;
    PORT
      LAYER M5 ;
        RECT  24.672 36.528 24.696 36.72 ;
    END
  END dq[167]
  PIN dq[168]
    DIRECTION OUTPUT ;
    USE SIGNAL ;
    PORT
      LAYER M3 ;
        RECT  24.804 36.576 24.822 36.72 ;
    END
  END dq[168]
  PIN dq[169]
    DIRECTION OUTPUT ;
    USE SIGNAL ;
    PORT
      LAYER M5 ;
        RECT  24.912 36.528 24.936 36.72 ;
    END
  END dq[169]
  PIN dq[16]
    DIRECTION OUTPUT ;
    USE SIGNAL ;
    PORT
      LAYER M3 ;
        RECT  6.3 36.576 6.318 36.72 ;
    END
  END dq[16]
  PIN dq[170]
    DIRECTION OUTPUT ;
    USE SIGNAL ;
    PORT
      LAYER M3 ;
        RECT  25.056 36.576 25.074 36.72 ;
    END
  END dq[170]
  PIN dq[171]
    DIRECTION OUTPUT ;
    USE SIGNAL ;
    PORT
      LAYER M5 ;
        RECT  25.152 36.528 25.176 36.72 ;
    END
  END dq[171]
  PIN dq[172]
    DIRECTION OUTPUT ;
    USE SIGNAL ;
    PORT
      LAYER M3 ;
        RECT  25.308 36.576 25.326 36.72 ;
    END
  END dq[172]
  PIN dq[173]
    DIRECTION OUTPUT ;
    USE SIGNAL ;
    PORT
      LAYER M5 ;
        RECT  25.392 36.528 25.416 36.72 ;
    END
  END dq[173]
  PIN dq[174]
    DIRECTION OUTPUT ;
    USE SIGNAL ;
    PORT
      LAYER M3 ;
        RECT  25.524 36.576 25.542 36.72 ;
    END
  END dq[174]
  PIN dq[175]
    DIRECTION OUTPUT ;
    USE SIGNAL ;
    PORT
      LAYER M5 ;
        RECT  25.632 36.528 25.656 36.72 ;
    END
  END dq[175]
  PIN dq[176]
    DIRECTION OUTPUT ;
    USE SIGNAL ;
    PORT
      LAYER M3 ;
        RECT  25.776 36.576 25.794 36.72 ;
    END
  END dq[176]
  PIN dq[177]
    DIRECTION OUTPUT ;
    USE SIGNAL ;
    PORT
      LAYER M5 ;
        RECT  25.92 36.528 25.944 36.72 ;
    END
  END dq[177]
  PIN dq[178]
    DIRECTION OUTPUT ;
    USE SIGNAL ;
    PORT
      LAYER M3 ;
        RECT  26.028 36.576 26.046 36.72 ;
    END
  END dq[178]
  PIN dq[179]
    DIRECTION OUTPUT ;
    USE SIGNAL ;
    PORT
      LAYER M5 ;
        RECT  26.16 36.528 26.184 36.72 ;
    END
  END dq[179]
  PIN dq[17]
    DIRECTION OUTPUT ;
    USE SIGNAL ;
    PORT
      LAYER M5 ;
        RECT  6.432 36.528 6.456 36.72 ;
    END
  END dq[17]
  PIN dq[180]
    DIRECTION OUTPUT ;
    USE SIGNAL ;
    PORT
      LAYER M3 ;
        RECT  26.28 36.576 26.298 36.72 ;
    END
  END dq[180]
  PIN dq[181]
    DIRECTION OUTPUT ;
    USE SIGNAL ;
    PORT
      LAYER M5 ;
        RECT  26.4 36.528 26.424 36.72 ;
    END
  END dq[181]
  PIN dq[182]
    DIRECTION OUTPUT ;
    USE SIGNAL ;
    PORT
      LAYER M3 ;
        RECT  26.496 36.576 26.514 36.72 ;
    END
  END dq[182]
  PIN dq[183]
    DIRECTION OUTPUT ;
    USE SIGNAL ;
    PORT
      LAYER M5 ;
        RECT  26.64 36.528 26.664 36.72 ;
    END
  END dq[183]
  PIN dq[184]
    DIRECTION OUTPUT ;
    USE SIGNAL ;
    PORT
      LAYER M3 ;
        RECT  26.748 36.576 26.766 36.72 ;
    END
  END dq[184]
  PIN dq[185]
    DIRECTION OUTPUT ;
    USE SIGNAL ;
    PORT
      LAYER M5 ;
        RECT  26.88 36.528 26.904 36.72 ;
    END
  END dq[185]
  PIN dq[186]
    DIRECTION OUTPUT ;
    USE SIGNAL ;
    PORT
      LAYER M3 ;
        RECT  27 36.576 27.018 36.72 ;
    END
  END dq[186]
  PIN dq[187]
    DIRECTION OUTPUT ;
    USE SIGNAL ;
    PORT
      LAYER M5 ;
        RECT  27.12 36.528 27.144 36.72 ;
    END
  END dq[187]
  PIN dq[188]
    DIRECTION OUTPUT ;
    USE SIGNAL ;
    PORT
      LAYER M3 ;
        RECT  27.252 36.576 27.27 36.72 ;
    END
  END dq[188]
  PIN dq[189]
    DIRECTION OUTPUT ;
    USE SIGNAL ;
    PORT
      LAYER M5 ;
        RECT  27.36 36.528 27.384 36.72 ;
    END
  END dq[189]
  PIN dq[18]
    DIRECTION OUTPUT ;
    USE SIGNAL ;
    PORT
      LAYER M3 ;
        RECT  6.552 36.576 6.57 36.72 ;
    END
  END dq[18]
  PIN dq[190]
    DIRECTION OUTPUT ;
    USE SIGNAL ;
    PORT
      LAYER M3 ;
        RECT  27.468 36.576 27.486 36.72 ;
    END
  END dq[190]
  PIN dq[191]
    DIRECTION OUTPUT ;
    USE SIGNAL ;
    PORT
      LAYER M5 ;
        RECT  27.6 36.528 27.624 36.72 ;
    END
  END dq[191]
  PIN dq[192]
    DIRECTION OUTPUT ;
    USE SIGNAL ;
    PORT
      LAYER M3 ;
        RECT  27.72 36.576 27.738 36.72 ;
    END
  END dq[192]
  PIN dq[193]
    DIRECTION OUTPUT ;
    USE SIGNAL ;
    PORT
      LAYER M5 ;
        RECT  27.84 36.528 27.864 36.72 ;
    END
  END dq[193]
  PIN dq[194]
    DIRECTION OUTPUT ;
    USE SIGNAL ;
    PORT
      LAYER M3 ;
        RECT  27.972 36.576 27.99 36.72 ;
    END
  END dq[194]
  PIN dq[195]
    DIRECTION OUTPUT ;
    USE SIGNAL ;
    PORT
      LAYER M5 ;
        RECT  28.08 36.528 28.104 36.72 ;
    END
  END dq[195]
  PIN dq[196]
    DIRECTION OUTPUT ;
    USE SIGNAL ;
    PORT
      LAYER M3 ;
        RECT  28.224 36.576 28.242 36.72 ;
    END
  END dq[196]
  PIN dq[197]
    DIRECTION OUTPUT ;
    USE SIGNAL ;
    PORT
      LAYER M5 ;
        RECT  28.32 36.528 28.344 36.72 ;
    END
  END dq[197]
  PIN dq[198]
    DIRECTION OUTPUT ;
    USE SIGNAL ;
    PORT
      LAYER M3 ;
        RECT  28.44 36.576 28.458 36.72 ;
    END
  END dq[198]
  PIN dq[199]
    DIRECTION OUTPUT ;
    USE SIGNAL ;
    PORT
      LAYER M5 ;
        RECT  28.56 36.528 28.584 36.72 ;
    END
  END dq[199]
  PIN dq[19]
    DIRECTION OUTPUT ;
    USE SIGNAL ;
    PORT
      LAYER M5 ;
        RECT  6.672 36.528 6.696 36.72 ;
    END
  END dq[19]
  PIN dq[1]
    DIRECTION OUTPUT ;
    USE SIGNAL ;
    PORT
      LAYER M5 ;
        RECT  4.512 36.528 4.536 36.72 ;
    END
  END dq[1]
  PIN dq[200]
    DIRECTION OUTPUT ;
    USE SIGNAL ;
    PORT
      LAYER M3 ;
        RECT  28.692 36.576 28.71 36.72 ;
    END
  END dq[200]
  PIN dq[201]
    DIRECTION OUTPUT ;
    USE SIGNAL ;
    PORT
      LAYER M5 ;
        RECT  28.8 36.528 28.824 36.72 ;
    END
  END dq[201]
  PIN dq[202]
    DIRECTION OUTPUT ;
    USE SIGNAL ;
    PORT
      LAYER M3 ;
        RECT  28.944 36.576 28.962 36.72 ;
    END
  END dq[202]
  PIN dq[203]
    DIRECTION OUTPUT ;
    USE SIGNAL ;
    PORT
      LAYER M5 ;
        RECT  29.04 36.528 29.064 36.72 ;
    END
  END dq[203]
  PIN dq[204]
    DIRECTION OUTPUT ;
    USE SIGNAL ;
    PORT
      LAYER M3 ;
        RECT  29.196 36.576 29.214 36.72 ;
    END
  END dq[204]
  PIN dq[205]
    DIRECTION OUTPUT ;
    USE SIGNAL ;
    PORT
      LAYER M5 ;
        RECT  29.28 36.528 29.304 36.72 ;
    END
  END dq[205]
  PIN dq[206]
    DIRECTION OUTPUT ;
    USE SIGNAL ;
    PORT
      LAYER M3 ;
        RECT  29.412 36.576 29.43 36.72 ;
    END
  END dq[206]
  PIN dq[207]
    DIRECTION OUTPUT ;
    USE SIGNAL ;
    PORT
      LAYER M5 ;
        RECT  29.568 36.528 29.592 36.72 ;
    END
  END dq[207]
  PIN dq[208]
    DIRECTION OUTPUT ;
    USE SIGNAL ;
    PORT
      LAYER M3 ;
        RECT  29.664 36.576 29.682 36.72 ;
    END
  END dq[208]
  PIN dq[209]
    DIRECTION OUTPUT ;
    USE SIGNAL ;
    PORT
      LAYER M5 ;
        RECT  29.808 36.528 29.832 36.72 ;
    END
  END dq[209]
  PIN dq[20]
    DIRECTION OUTPUT ;
    USE SIGNAL ;
    PORT
      LAYER M3 ;
        RECT  6.804 36.576 6.822 36.72 ;
    END
  END dq[20]
  PIN dq[210]
    DIRECTION OUTPUT ;
    USE SIGNAL ;
    PORT
      LAYER M3 ;
        RECT  29.916 36.576 29.934 36.72 ;
    END
  END dq[210]
  PIN dq[211]
    DIRECTION OUTPUT ;
    USE SIGNAL ;
    PORT
      LAYER M5 ;
        RECT  30.048 36.528 30.072 36.72 ;
    END
  END dq[211]
  PIN dq[212]
    DIRECTION OUTPUT ;
    USE SIGNAL ;
    PORT
      LAYER M3 ;
        RECT  30.168 36.576 30.186 36.72 ;
    END
  END dq[212]
  PIN dq[213]
    DIRECTION OUTPUT ;
    USE SIGNAL ;
    PORT
      LAYER M5 ;
        RECT  30.288 36.528 30.312 36.72 ;
    END
  END dq[213]
  PIN dq[214]
    DIRECTION OUTPUT ;
    USE SIGNAL ;
    PORT
      LAYER M3 ;
        RECT  30.384 36.576 30.402 36.72 ;
    END
  END dq[214]
  PIN dq[215]
    DIRECTION OUTPUT ;
    USE SIGNAL ;
    PORT
      LAYER M5 ;
        RECT  30.528 36.528 30.552 36.72 ;
    END
  END dq[215]
  PIN dq[216]
    DIRECTION OUTPUT ;
    USE SIGNAL ;
    PORT
      LAYER M3 ;
        RECT  30.636 36.576 30.654 36.72 ;
    END
  END dq[216]
  PIN dq[217]
    DIRECTION OUTPUT ;
    USE SIGNAL ;
    PORT
      LAYER M5 ;
        RECT  30.768 36.528 30.792 36.72 ;
    END
  END dq[217]
  PIN dq[218]
    DIRECTION OUTPUT ;
    USE SIGNAL ;
    PORT
      LAYER M3 ;
        RECT  30.888 36.576 30.906 36.72 ;
    END
  END dq[218]
  PIN dq[219]
    DIRECTION OUTPUT ;
    USE SIGNAL ;
    PORT
      LAYER M5 ;
        RECT  31.008 36.528 31.032 36.72 ;
    END
  END dq[219]
  PIN dq[21]
    DIRECTION OUTPUT ;
    USE SIGNAL ;
    PORT
      LAYER M5 ;
        RECT  6.912 36.528 6.936 36.72 ;
    END
  END dq[21]
  PIN dq[220]
    DIRECTION OUTPUT ;
    USE SIGNAL ;
    PORT
      LAYER M3 ;
        RECT  31.14 36.576 31.158 36.72 ;
    END
  END dq[220]
  PIN dq[221]
    DIRECTION OUTPUT ;
    USE SIGNAL ;
    PORT
      LAYER M5 ;
        RECT  31.248 36.528 31.272 36.72 ;
    END
  END dq[221]
  PIN dq[222]
    DIRECTION OUTPUT ;
    USE SIGNAL ;
    PORT
      LAYER M3 ;
        RECT  31.356 36.576 31.374 36.72 ;
    END
  END dq[222]
  PIN dq[223]
    DIRECTION OUTPUT ;
    USE SIGNAL ;
    PORT
      LAYER M5 ;
        RECT  31.488 36.528 31.512 36.72 ;
    END
  END dq[223]
  PIN dq[224]
    DIRECTION OUTPUT ;
    USE SIGNAL ;
    PORT
      LAYER M3 ;
        RECT  31.608 36.576 31.626 36.72 ;
    END
  END dq[224]
  PIN dq[225]
    DIRECTION OUTPUT ;
    USE SIGNAL ;
    PORT
      LAYER M5 ;
        RECT  31.728 36.528 31.752 36.72 ;
    END
  END dq[225]
  PIN dq[226]
    DIRECTION OUTPUT ;
    USE SIGNAL ;
    PORT
      LAYER M3 ;
        RECT  31.86 36.576 31.878 36.72 ;
    END
  END dq[226]
  PIN dq[227]
    DIRECTION OUTPUT ;
    USE SIGNAL ;
    PORT
      LAYER M5 ;
        RECT  31.968 36.528 31.992 36.72 ;
    END
  END dq[227]
  PIN dq[228]
    DIRECTION OUTPUT ;
    USE SIGNAL ;
    PORT
      LAYER M3 ;
        RECT  32.112 36.576 32.13 36.72 ;
    END
  END dq[228]
  PIN dq[229]
    DIRECTION OUTPUT ;
    USE SIGNAL ;
    PORT
      LAYER M5 ;
        RECT  32.208 36.528 32.232 36.72 ;
    END
  END dq[229]
  PIN dq[22]
    DIRECTION OUTPUT ;
    USE SIGNAL ;
    PORT
      LAYER M3 ;
        RECT  7.056 36.576 7.074 36.72 ;
    END
  END dq[22]
  PIN dq[230]
    DIRECTION OUTPUT ;
    USE SIGNAL ;
    PORT
      LAYER M3 ;
        RECT  32.364 36.576 32.382 36.72 ;
    END
  END dq[230]
  PIN dq[231]
    DIRECTION OUTPUT ;
    USE SIGNAL ;
    PORT
      LAYER M5 ;
        RECT  32.448 36.528 32.472 36.72 ;
    END
  END dq[231]
  PIN dq[232]
    DIRECTION OUTPUT ;
    USE SIGNAL ;
    PORT
      LAYER M3 ;
        RECT  32.58 36.576 32.598 36.72 ;
    END
  END dq[232]
  PIN dq[233]
    DIRECTION OUTPUT ;
    USE SIGNAL ;
    PORT
      LAYER M5 ;
        RECT  32.688 36.528 32.712 36.72 ;
    END
  END dq[233]
  PIN dq[234]
    DIRECTION OUTPUT ;
    USE SIGNAL ;
    PORT
      LAYER M3 ;
        RECT  32.832 36.576 32.85 36.72 ;
    END
  END dq[234]
  PIN dq[235]
    DIRECTION OUTPUT ;
    USE SIGNAL ;
    PORT
      LAYER M5 ;
        RECT  32.976 36.528 33 36.72 ;
    END
  END dq[235]
  PIN dq[236]
    DIRECTION OUTPUT ;
    USE SIGNAL ;
    PORT
      LAYER M3 ;
        RECT  33.084 36.576 33.102 36.72 ;
    END
  END dq[236]
  PIN dq[237]
    DIRECTION OUTPUT ;
    USE SIGNAL ;
    PORT
      LAYER M5 ;
        RECT  33.216 36.528 33.24 36.72 ;
    END
  END dq[237]
  PIN dq[238]
    DIRECTION OUTPUT ;
    USE SIGNAL ;
    PORT
      LAYER M3 ;
        RECT  33.336 36.576 33.354 36.72 ;
    END
  END dq[238]
  PIN dq[239]
    DIRECTION OUTPUT ;
    USE SIGNAL ;
    PORT
      LAYER M5 ;
        RECT  33.456 36.528 33.48 36.72 ;
    END
  END dq[239]
  PIN dq[23]
    DIRECTION OUTPUT ;
    USE SIGNAL ;
    PORT
      LAYER M5 ;
        RECT  7.152 36.528 7.176 36.72 ;
    END
  END dq[23]
  PIN dq[240]
    DIRECTION OUTPUT ;
    USE SIGNAL ;
    PORT
      LAYER M3 ;
        RECT  33.552 36.576 33.57 36.72 ;
    END
  END dq[240]
  PIN dq[241]
    DIRECTION OUTPUT ;
    USE SIGNAL ;
    PORT
      LAYER M5 ;
        RECT  33.696 36.528 33.72 36.72 ;
    END
  END dq[241]
  PIN dq[242]
    DIRECTION OUTPUT ;
    USE SIGNAL ;
    PORT
      LAYER M3 ;
        RECT  33.804 36.576 33.822 36.72 ;
    END
  END dq[242]
  PIN dq[243]
    DIRECTION OUTPUT ;
    USE SIGNAL ;
    PORT
      LAYER M5 ;
        RECT  33.936 36.528 33.96 36.72 ;
    END
  END dq[243]
  PIN dq[244]
    DIRECTION OUTPUT ;
    USE SIGNAL ;
    PORT
      LAYER M3 ;
        RECT  34.056 36.576 34.074 36.72 ;
    END
  END dq[244]
  PIN dq[245]
    DIRECTION OUTPUT ;
    USE SIGNAL ;
    PORT
      LAYER M5 ;
        RECT  34.176 36.528 34.2 36.72 ;
    END
  END dq[245]
  PIN dq[246]
    DIRECTION OUTPUT ;
    USE SIGNAL ;
    PORT
      LAYER M3 ;
        RECT  34.308 36.576 34.326 36.72 ;
    END
  END dq[246]
  PIN dq[247]
    DIRECTION OUTPUT ;
    USE SIGNAL ;
    PORT
      LAYER M5 ;
        RECT  34.416 36.528 34.44 36.72 ;
    END
  END dq[247]
  PIN dq[248]
    DIRECTION OUTPUT ;
    USE SIGNAL ;
    PORT
      LAYER M3 ;
        RECT  34.524 36.576 34.542 36.72 ;
    END
  END dq[248]
  PIN dq[249]
    DIRECTION OUTPUT ;
    USE SIGNAL ;
    PORT
      LAYER M5 ;
        RECT  34.656 36.528 34.68 36.72 ;
    END
  END dq[249]
  PIN dq[24]
    DIRECTION OUTPUT ;
    USE SIGNAL ;
    PORT
      LAYER M3 ;
        RECT  7.308 36.576 7.326 36.72 ;
    END
  END dq[24]
  PIN dq[250]
    DIRECTION OUTPUT ;
    USE SIGNAL ;
    PORT
      LAYER M3 ;
        RECT  34.776 36.576 34.794 36.72 ;
    END
  END dq[250]
  PIN dq[251]
    DIRECTION OUTPUT ;
    USE SIGNAL ;
    PORT
      LAYER M5 ;
        RECT  34.896 36.528 34.92 36.72 ;
    END
  END dq[251]
  PIN dq[252]
    DIRECTION OUTPUT ;
    USE SIGNAL ;
    PORT
      LAYER M3 ;
        RECT  35.028 36.576 35.046 36.72 ;
    END
  END dq[252]
  PIN dq[253]
    DIRECTION OUTPUT ;
    USE SIGNAL ;
    PORT
      LAYER M5 ;
        RECT  35.136 36.528 35.16 36.72 ;
    END
  END dq[253]
  PIN dq[254]
    DIRECTION OUTPUT ;
    USE SIGNAL ;
    PORT
      LAYER M3 ;
        RECT  35.28 36.576 35.298 36.72 ;
    END
  END dq[254]
  PIN dq[255]
    DIRECTION OUTPUT ;
    USE SIGNAL ;
    PORT
      LAYER M5 ;
        RECT  35.376 36.528 35.4 36.72 ;
    END
  END dq[255]
  PIN dq[256]
    DIRECTION OUTPUT ;
    USE SIGNAL ;
    PORT
      LAYER M3 ;
        RECT  35.496 36.576 35.514 36.72 ;
    END
  END dq[256]
  PIN dq[257]
    DIRECTION OUTPUT ;
    USE SIGNAL ;
    PORT
      LAYER M5 ;
        RECT  35.616 36.528 35.64 36.72 ;
    END
  END dq[257]
  PIN dq[258]
    DIRECTION OUTPUT ;
    USE SIGNAL ;
    PORT
      LAYER M3 ;
        RECT  35.748 36.576 35.766 36.72 ;
    END
  END dq[258]
  PIN dq[259]
    DIRECTION OUTPUT ;
    USE SIGNAL ;
    PORT
      LAYER M5 ;
        RECT  35.856 36.528 35.88 36.72 ;
    END
  END dq[259]
  PIN dq[25]
    DIRECTION OUTPUT ;
    USE SIGNAL ;
    PORT
      LAYER M5 ;
        RECT  7.392 36.528 7.416 36.72 ;
    END
  END dq[25]
  PIN dq[260]
    DIRECTION OUTPUT ;
    USE SIGNAL ;
    PORT
      LAYER M3 ;
        RECT  36 36.576 36.018 36.72 ;
    END
  END dq[260]
  PIN dq[261]
    DIRECTION OUTPUT ;
    USE SIGNAL ;
    PORT
      LAYER M5 ;
        RECT  36.096 36.528 36.12 36.72 ;
    END
  END dq[261]
  PIN dq[262]
    DIRECTION OUTPUT ;
    USE SIGNAL ;
    PORT
      LAYER M3 ;
        RECT  36.252 36.576 36.27 36.72 ;
    END
  END dq[262]
  PIN dq[263]
    DIRECTION OUTPUT ;
    USE SIGNAL ;
    PORT
      LAYER M5 ;
        RECT  36.336 36.528 36.36 36.72 ;
    END
  END dq[263]
  PIN dq[264]
    DIRECTION OUTPUT ;
    USE SIGNAL ;
    PORT
      LAYER M3 ;
        RECT  36.468 36.576 36.486 36.72 ;
    END
  END dq[264]
  PIN dq[265]
    DIRECTION OUTPUT ;
    USE SIGNAL ;
    PORT
      LAYER M5 ;
        RECT  36.624 36.528 36.648 36.72 ;
    END
  END dq[265]
  PIN dq[266]
    DIRECTION OUTPUT ;
    USE SIGNAL ;
    PORT
      LAYER M3 ;
        RECT  36.72 36.576 36.738 36.72 ;
    END
  END dq[266]
  PIN dq[267]
    DIRECTION OUTPUT ;
    USE SIGNAL ;
    PORT
      LAYER M5 ;
        RECT  36.864 36.528 36.888 36.72 ;
    END
  END dq[267]
  PIN dq[268]
    DIRECTION OUTPUT ;
    USE SIGNAL ;
    PORT
      LAYER M3 ;
        RECT  36.972 36.576 36.99 36.72 ;
    END
  END dq[268]
  PIN dq[269]
    DIRECTION OUTPUT ;
    USE SIGNAL ;
    PORT
      LAYER M5 ;
        RECT  37.104 36.528 37.128 36.72 ;
    END
  END dq[269]
  PIN dq[26]
    DIRECTION OUTPUT ;
    USE SIGNAL ;
    PORT
      LAYER M3 ;
        RECT  7.524 36.576 7.542 36.72 ;
    END
  END dq[26]
  PIN dq[270]
    DIRECTION OUTPUT ;
    USE SIGNAL ;
    PORT
      LAYER M3 ;
        RECT  37.224 36.576 37.242 36.72 ;
    END
  END dq[270]
  PIN dq[271]
    DIRECTION OUTPUT ;
    USE SIGNAL ;
    PORT
      LAYER M5 ;
        RECT  37.344 36.528 37.368 36.72 ;
    END
  END dq[271]
  PIN dq[272]
    DIRECTION OUTPUT ;
    USE SIGNAL ;
    PORT
      LAYER M3 ;
        RECT  37.44 36.576 37.458 36.72 ;
    END
  END dq[272]
  PIN dq[273]
    DIRECTION OUTPUT ;
    USE SIGNAL ;
    PORT
      LAYER M5 ;
        RECT  37.584 36.528 37.608 36.72 ;
    END
  END dq[273]
  PIN dq[274]
    DIRECTION OUTPUT ;
    USE SIGNAL ;
    PORT
      LAYER M3 ;
        RECT  37.692 36.576 37.71 36.72 ;
    END
  END dq[274]
  PIN dq[275]
    DIRECTION OUTPUT ;
    USE SIGNAL ;
    PORT
      LAYER M5 ;
        RECT  37.824 36.528 37.848 36.72 ;
    END
  END dq[275]
  PIN dq[276]
    DIRECTION OUTPUT ;
    USE SIGNAL ;
    PORT
      LAYER M3 ;
        RECT  37.944 36.576 37.962 36.72 ;
    END
  END dq[276]
  PIN dq[277]
    DIRECTION OUTPUT ;
    USE SIGNAL ;
    PORT
      LAYER M5 ;
        RECT  38.064 36.528 38.088 36.72 ;
    END
  END dq[277]
  PIN dq[278]
    DIRECTION OUTPUT ;
    USE SIGNAL ;
    PORT
      LAYER M3 ;
        RECT  38.196 36.576 38.214 36.72 ;
    END
  END dq[278]
  PIN dq[279]
    DIRECTION OUTPUT ;
    USE SIGNAL ;
    PORT
      LAYER M5 ;
        RECT  38.304 36.528 38.328 36.72 ;
    END
  END dq[279]
  PIN dq[27]
    DIRECTION OUTPUT ;
    USE SIGNAL ;
    PORT
      LAYER M5 ;
        RECT  7.632 36.528 7.656 36.72 ;
    END
  END dq[27]
  PIN dq[280]
    DIRECTION OUTPUT ;
    USE SIGNAL ;
    PORT
      LAYER M3 ;
        RECT  38.412 36.576 38.43 36.72 ;
    END
  END dq[280]
  PIN dq[281]
    DIRECTION OUTPUT ;
    USE SIGNAL ;
    PORT
      LAYER M5 ;
        RECT  38.544 36.528 38.568 36.72 ;
    END
  END dq[281]
  PIN dq[282]
    DIRECTION OUTPUT ;
    USE SIGNAL ;
    PORT
      LAYER M3 ;
        RECT  38.664 36.576 38.682 36.72 ;
    END
  END dq[282]
  PIN dq[283]
    DIRECTION OUTPUT ;
    USE SIGNAL ;
    PORT
      LAYER M5 ;
        RECT  38.784 36.528 38.808 36.72 ;
    END
  END dq[283]
  PIN dq[284]
    DIRECTION OUTPUT ;
    USE SIGNAL ;
    PORT
      LAYER M3 ;
        RECT  38.916 36.576 38.934 36.72 ;
    END
  END dq[284]
  PIN dq[285]
    DIRECTION OUTPUT ;
    USE SIGNAL ;
    PORT
      LAYER M5 ;
        RECT  39.024 36.528 39.048 36.72 ;
    END
  END dq[285]
  PIN dq[286]
    DIRECTION OUTPUT ;
    USE SIGNAL ;
    PORT
      LAYER M3 ;
        RECT  39.168 36.576 39.186 36.72 ;
    END
  END dq[286]
  PIN dq[287]
    DIRECTION OUTPUT ;
    USE SIGNAL ;
    PORT
      LAYER M5 ;
        RECT  39.264 36.528 39.288 36.72 ;
    END
  END dq[287]
  PIN dq[288]
    DIRECTION OUTPUT ;
    USE SIGNAL ;
    PORT
      LAYER M3 ;
        RECT  39.384 36.576 39.402 36.72 ;
    END
  END dq[288]
  PIN dq[289]
    DIRECTION OUTPUT ;
    USE SIGNAL ;
    PORT
      LAYER M5 ;
        RECT  39.504 36.528 39.528 36.72 ;
    END
  END dq[289]
  PIN dq[28]
    DIRECTION OUTPUT ;
    USE SIGNAL ;
    PORT
      LAYER M3 ;
        RECT  7.776 36.576 7.794 36.72 ;
    END
  END dq[28]
  PIN dq[290]
    DIRECTION OUTPUT ;
    USE SIGNAL ;
    PORT
      LAYER M3 ;
        RECT  39.636 36.576 39.654 36.72 ;
    END
  END dq[290]
  PIN dq[291]
    DIRECTION OUTPUT ;
    USE SIGNAL ;
    PORT
      LAYER M5 ;
        RECT  39.744 36.528 39.768 36.72 ;
    END
  END dq[291]
  PIN dq[292]
    DIRECTION OUTPUT ;
    USE SIGNAL ;
    PORT
      LAYER M3 ;
        RECT  39.888 36.576 39.906 36.72 ;
    END
  END dq[292]
  PIN dq[293]
    DIRECTION OUTPUT ;
    USE SIGNAL ;
    PORT
      LAYER M5 ;
        RECT  39.984 36.528 40.008 36.72 ;
    END
  END dq[293]
  PIN dq[294]
    DIRECTION OUTPUT ;
    USE SIGNAL ;
    PORT
      LAYER M3 ;
        RECT  40.14 36.576 40.158 36.72 ;
    END
  END dq[294]
  PIN dq[295]
    DIRECTION OUTPUT ;
    USE SIGNAL ;
    PORT
      LAYER M5 ;
        RECT  40.272 36.528 40.296 36.72 ;
    END
  END dq[295]
  PIN dq[296]
    DIRECTION OUTPUT ;
    USE SIGNAL ;
    PORT
      LAYER M3 ;
        RECT  40.392 36.576 40.41 36.72 ;
    END
  END dq[296]
  PIN dq[297]
    DIRECTION OUTPUT ;
    USE SIGNAL ;
    PORT
      LAYER M5 ;
        RECT  40.512 36.528 40.536 36.72 ;
    END
  END dq[297]
  PIN dq[298]
    DIRECTION OUTPUT ;
    USE SIGNAL ;
    PORT
      LAYER M3 ;
        RECT  40.608 36.576 40.626 36.72 ;
    END
  END dq[298]
  PIN dq[299]
    DIRECTION OUTPUT ;
    USE SIGNAL ;
    PORT
      LAYER M5 ;
        RECT  40.752 36.528 40.776 36.72 ;
    END
  END dq[299]
  PIN dq[29]
    DIRECTION OUTPUT ;
    USE SIGNAL ;
    PORT
      LAYER M5 ;
        RECT  7.92 36.528 7.944 36.72 ;
    END
  END dq[29]
  PIN dq[2]
    DIRECTION OUTPUT ;
    USE SIGNAL ;
    PORT
      LAYER M3 ;
        RECT  4.608 36.576 4.626 36.72 ;
    END
  END dq[2]
  PIN dq[300]
    DIRECTION OUTPUT ;
    USE SIGNAL ;
    PORT
      LAYER M3 ;
        RECT  40.86 36.576 40.878 36.72 ;
    END
  END dq[300]
  PIN dq[301]
    DIRECTION OUTPUT ;
    USE SIGNAL ;
    PORT
      LAYER M5 ;
        RECT  40.992 36.528 41.016 36.72 ;
    END
  END dq[301]
  PIN dq[302]
    DIRECTION OUTPUT ;
    USE SIGNAL ;
    PORT
      LAYER M3 ;
        RECT  41.112 36.576 41.13 36.72 ;
    END
  END dq[302]
  PIN dq[303]
    DIRECTION OUTPUT ;
    USE SIGNAL ;
    PORT
      LAYER M5 ;
        RECT  41.232 36.528 41.256 36.72 ;
    END
  END dq[303]
  PIN dq[304]
    DIRECTION OUTPUT ;
    USE SIGNAL ;
    PORT
      LAYER M3 ;
        RECT  41.364 36.576 41.382 36.72 ;
    END
  END dq[304]
  PIN dq[305]
    DIRECTION OUTPUT ;
    USE SIGNAL ;
    PORT
      LAYER M5 ;
        RECT  41.472 36.528 41.496 36.72 ;
    END
  END dq[305]
  PIN dq[306]
    DIRECTION OUTPUT ;
    USE SIGNAL ;
    PORT
      LAYER M3 ;
        RECT  41.58 36.576 41.598 36.72 ;
    END
  END dq[306]
  PIN dq[307]
    DIRECTION OUTPUT ;
    USE SIGNAL ;
    PORT
      LAYER M5 ;
        RECT  41.712 36.528 41.736 36.72 ;
    END
  END dq[307]
  PIN dq[308]
    DIRECTION OUTPUT ;
    USE SIGNAL ;
    PORT
      LAYER M3 ;
        RECT  41.832 36.576 41.85 36.72 ;
    END
  END dq[308]
  PIN dq[309]
    DIRECTION OUTPUT ;
    USE SIGNAL ;
    PORT
      LAYER M5 ;
        RECT  41.952 36.528 41.976 36.72 ;
    END
  END dq[309]
  PIN dq[30]
    DIRECTION OUTPUT ;
    USE SIGNAL ;
    PORT
      LAYER M3 ;
        RECT  8.028 36.576 8.046 36.72 ;
    END
  END dq[30]
  PIN dq[310]
    DIRECTION OUTPUT ;
    USE SIGNAL ;
    PORT
      LAYER M3 ;
        RECT  42.084 36.576 42.102 36.72 ;
    END
  END dq[310]
  PIN dq[311]
    DIRECTION OUTPUT ;
    USE SIGNAL ;
    PORT
      LAYER M5 ;
        RECT  42.192 36.528 42.216 36.72 ;
    END
  END dq[311]
  PIN dq[312]
    DIRECTION OUTPUT ;
    USE SIGNAL ;
    PORT
      LAYER M3 ;
        RECT  42.336 36.576 42.354 36.72 ;
    END
  END dq[312]
  PIN dq[313]
    DIRECTION OUTPUT ;
    USE SIGNAL ;
    PORT
      LAYER M5 ;
        RECT  42.432 36.528 42.456 36.72 ;
    END
  END dq[313]
  PIN dq[314]
    DIRECTION OUTPUT ;
    USE SIGNAL ;
    PORT
      LAYER M3 ;
        RECT  42.552 36.576 42.57 36.72 ;
    END
  END dq[314]
  PIN dq[315]
    DIRECTION OUTPUT ;
    USE SIGNAL ;
    PORT
      LAYER M5 ;
        RECT  42.672 36.528 42.696 36.72 ;
    END
  END dq[315]
  PIN dq[316]
    DIRECTION OUTPUT ;
    USE SIGNAL ;
    PORT
      LAYER M3 ;
        RECT  42.804 36.576 42.822 36.72 ;
    END
  END dq[316]
  PIN dq[317]
    DIRECTION OUTPUT ;
    USE SIGNAL ;
    PORT
      LAYER M5 ;
        RECT  42.912 36.528 42.936 36.72 ;
    END
  END dq[317]
  PIN dq[318]
    DIRECTION OUTPUT ;
    USE SIGNAL ;
    PORT
      LAYER M3 ;
        RECT  43.056 36.576 43.074 36.72 ;
    END
  END dq[318]
  PIN dq[319]
    DIRECTION OUTPUT ;
    USE SIGNAL ;
    PORT
      LAYER M5 ;
        RECT  43.152 36.528 43.176 36.72 ;
    END
  END dq[319]
  PIN dq[31]
    DIRECTION OUTPUT ;
    USE SIGNAL ;
    PORT
      LAYER M5 ;
        RECT  8.16 36.528 8.184 36.72 ;
    END
  END dq[31]
  PIN dq[320]
    DIRECTION OUTPUT ;
    USE SIGNAL ;
    PORT
      LAYER M3 ;
        RECT  43.308 36.576 43.326 36.72 ;
    END
  END dq[320]
  PIN dq[321]
    DIRECTION OUTPUT ;
    USE SIGNAL ;
    PORT
      LAYER M5 ;
        RECT  43.392 36.528 43.416 36.72 ;
    END
  END dq[321]
  PIN dq[322]
    DIRECTION OUTPUT ;
    USE SIGNAL ;
    PORT
      LAYER M3 ;
        RECT  43.524 36.576 43.542 36.72 ;
    END
  END dq[322]
  PIN dq[323]
    DIRECTION OUTPUT ;
    USE SIGNAL ;
    PORT
      LAYER M5 ;
        RECT  43.632 36.528 43.656 36.72 ;
    END
  END dq[323]
  PIN dq[324]
    DIRECTION OUTPUT ;
    USE SIGNAL ;
    PORT
      LAYER M3 ;
        RECT  43.776 36.576 43.794 36.72 ;
    END
  END dq[324]
  PIN dq[325]
    DIRECTION OUTPUT ;
    USE SIGNAL ;
    PORT
      LAYER M5 ;
        RECT  43.92 36.528 43.944 36.72 ;
    END
  END dq[325]
  PIN dq[326]
    DIRECTION OUTPUT ;
    USE SIGNAL ;
    PORT
      LAYER M3 ;
        RECT  44.028 36.576 44.046 36.72 ;
    END
  END dq[326]
  PIN dq[327]
    DIRECTION OUTPUT ;
    USE SIGNAL ;
    PORT
      LAYER M5 ;
        RECT  44.16 36.528 44.184 36.72 ;
    END
  END dq[327]
  PIN dq[328]
    DIRECTION OUTPUT ;
    USE SIGNAL ;
    PORT
      LAYER M3 ;
        RECT  44.28 36.576 44.298 36.72 ;
    END
  END dq[328]
  PIN dq[329]
    DIRECTION OUTPUT ;
    USE SIGNAL ;
    PORT
      LAYER M5 ;
        RECT  44.4 36.528 44.424 36.72 ;
    END
  END dq[329]
  PIN dq[32]
    DIRECTION OUTPUT ;
    USE SIGNAL ;
    PORT
      LAYER M3 ;
        RECT  8.28 36.576 8.298 36.72 ;
    END
  END dq[32]
  PIN dq[330]
    DIRECTION OUTPUT ;
    USE SIGNAL ;
    PORT
      LAYER M3 ;
        RECT  44.496 36.576 44.514 36.72 ;
    END
  END dq[330]
  PIN dq[331]
    DIRECTION OUTPUT ;
    USE SIGNAL ;
    PORT
      LAYER M5 ;
        RECT  44.64 36.528 44.664 36.72 ;
    END
  END dq[331]
  PIN dq[332]
    DIRECTION OUTPUT ;
    USE SIGNAL ;
    PORT
      LAYER M3 ;
        RECT  44.748 36.576 44.766 36.72 ;
    END
  END dq[332]
  PIN dq[333]
    DIRECTION OUTPUT ;
    USE SIGNAL ;
    PORT
      LAYER M5 ;
        RECT  44.88 36.528 44.904 36.72 ;
    END
  END dq[333]
  PIN dq[334]
    DIRECTION OUTPUT ;
    USE SIGNAL ;
    PORT
      LAYER M3 ;
        RECT  45 36.576 45.018 36.72 ;
    END
  END dq[334]
  PIN dq[335]
    DIRECTION OUTPUT ;
    USE SIGNAL ;
    PORT
      LAYER M5 ;
        RECT  45.12 36.528 45.144 36.72 ;
    END
  END dq[335]
  PIN dq[336]
    DIRECTION OUTPUT ;
    USE SIGNAL ;
    PORT
      LAYER M3 ;
        RECT  45.252 36.576 45.27 36.72 ;
    END
  END dq[336]
  PIN dq[337]
    DIRECTION OUTPUT ;
    USE SIGNAL ;
    PORT
      LAYER M5 ;
        RECT  45.36 36.528 45.384 36.72 ;
    END
  END dq[337]
  PIN dq[338]
    DIRECTION OUTPUT ;
    USE SIGNAL ;
    PORT
      LAYER M3 ;
        RECT  45.468 36.576 45.486 36.72 ;
    END
  END dq[338]
  PIN dq[339]
    DIRECTION OUTPUT ;
    USE SIGNAL ;
    PORT
      LAYER M5 ;
        RECT  45.6 36.528 45.624 36.72 ;
    END
  END dq[339]
  PIN dq[33]
    DIRECTION OUTPUT ;
    USE SIGNAL ;
    PORT
      LAYER M5 ;
        RECT  8.4 36.528 8.424 36.72 ;
    END
  END dq[33]
  PIN dq[340]
    DIRECTION OUTPUT ;
    USE SIGNAL ;
    PORT
      LAYER M3 ;
        RECT  45.72 36.576 45.738 36.72 ;
    END
  END dq[340]
  PIN dq[341]
    DIRECTION OUTPUT ;
    USE SIGNAL ;
    PORT
      LAYER M5 ;
        RECT  45.84 36.528 45.864 36.72 ;
    END
  END dq[341]
  PIN dq[342]
    DIRECTION OUTPUT ;
    USE SIGNAL ;
    PORT
      LAYER M3 ;
        RECT  45.972 36.576 45.99 36.72 ;
    END
  END dq[342]
  PIN dq[343]
    DIRECTION OUTPUT ;
    USE SIGNAL ;
    PORT
      LAYER M5 ;
        RECT  46.08 36.528 46.104 36.72 ;
    END
  END dq[343]
  PIN dq[344]
    DIRECTION OUTPUT ;
    USE SIGNAL ;
    PORT
      LAYER M3 ;
        RECT  46.224 36.576 46.242 36.72 ;
    END
  END dq[344]
  PIN dq[345]
    DIRECTION OUTPUT ;
    USE SIGNAL ;
    PORT
      LAYER M5 ;
        RECT  46.32 36.528 46.344 36.72 ;
    END
  END dq[345]
  PIN dq[346]
    DIRECTION OUTPUT ;
    USE SIGNAL ;
    PORT
      LAYER M3 ;
        RECT  46.44 36.576 46.458 36.72 ;
    END
  END dq[346]
  PIN dq[347]
    DIRECTION OUTPUT ;
    USE SIGNAL ;
    PORT
      LAYER M5 ;
        RECT  46.56 36.528 46.584 36.72 ;
    END
  END dq[347]
  PIN dq[348]
    DIRECTION OUTPUT ;
    USE SIGNAL ;
    PORT
      LAYER M3 ;
        RECT  46.692 36.576 46.71 36.72 ;
    END
  END dq[348]
  PIN dq[349]
    DIRECTION OUTPUT ;
    USE SIGNAL ;
    PORT
      LAYER M5 ;
        RECT  46.8 36.528 46.824 36.72 ;
    END
  END dq[349]
  PIN dq[34]
    DIRECTION OUTPUT ;
    USE SIGNAL ;
    PORT
      LAYER M3 ;
        RECT  8.496 36.576 8.514 36.72 ;
    END
  END dq[34]
  PIN dq[350]
    DIRECTION OUTPUT ;
    USE SIGNAL ;
    PORT
      LAYER M3 ;
        RECT  46.944 36.576 46.962 36.72 ;
    END
  END dq[350]
  PIN dq[351]
    DIRECTION OUTPUT ;
    USE SIGNAL ;
    PORT
      LAYER M5 ;
        RECT  47.04 36.528 47.064 36.72 ;
    END
  END dq[351]
  PIN dq[352]
    DIRECTION OUTPUT ;
    USE SIGNAL ;
    PORT
      LAYER M3 ;
        RECT  47.196 36.576 47.214 36.72 ;
    END
  END dq[352]
  PIN dq[353]
    DIRECTION OUTPUT ;
    USE SIGNAL ;
    PORT
      LAYER M5 ;
        RECT  47.328 36.528 47.352 36.72 ;
    END
  END dq[353]
  PIN dq[354]
    DIRECTION OUTPUT ;
    USE SIGNAL ;
    PORT
      LAYER M3 ;
        RECT  47.412 36.576 47.43 36.72 ;
    END
  END dq[354]
  PIN dq[355]
    DIRECTION OUTPUT ;
    USE SIGNAL ;
    PORT
      LAYER M5 ;
        RECT  47.568 36.528 47.592 36.72 ;
    END
  END dq[355]
  PIN dq[356]
    DIRECTION OUTPUT ;
    USE SIGNAL ;
    PORT
      LAYER M3 ;
        RECT  47.664 36.576 47.682 36.72 ;
    END
  END dq[356]
  PIN dq[357]
    DIRECTION OUTPUT ;
    USE SIGNAL ;
    PORT
      LAYER M5 ;
        RECT  47.808 36.528 47.832 36.72 ;
    END
  END dq[357]
  PIN dq[358]
    DIRECTION OUTPUT ;
    USE SIGNAL ;
    PORT
      LAYER M3 ;
        RECT  47.916 36.576 47.934 36.72 ;
    END
  END dq[358]
  PIN dq[359]
    DIRECTION OUTPUT ;
    USE SIGNAL ;
    PORT
      LAYER M5 ;
        RECT  48.048 36.528 48.072 36.72 ;
    END
  END dq[359]
  PIN dq[35]
    DIRECTION OUTPUT ;
    USE SIGNAL ;
    PORT
      LAYER M5 ;
        RECT  8.64 36.528 8.664 36.72 ;
    END
  END dq[35]
  PIN dq[360]
    DIRECTION OUTPUT ;
    USE SIGNAL ;
    PORT
      LAYER M3 ;
        RECT  48.168 36.576 48.186 36.72 ;
    END
  END dq[360]
  PIN dq[361]
    DIRECTION OUTPUT ;
    USE SIGNAL ;
    PORT
      LAYER M5 ;
        RECT  48.288 36.528 48.312 36.72 ;
    END
  END dq[361]
  PIN dq[362]
    DIRECTION OUTPUT ;
    USE SIGNAL ;
    PORT
      LAYER M3 ;
        RECT  48.42 36.576 48.438 36.72 ;
    END
  END dq[362]
  PIN dq[363]
    DIRECTION OUTPUT ;
    USE SIGNAL ;
    PORT
      LAYER M5 ;
        RECT  48.528 36.528 48.552 36.72 ;
    END
  END dq[363]
  PIN dq[364]
    DIRECTION OUTPUT ;
    USE SIGNAL ;
    PORT
      LAYER M3 ;
        RECT  48.636 36.576 48.654 36.72 ;
    END
  END dq[364]
  PIN dq[365]
    DIRECTION OUTPUT ;
    USE SIGNAL ;
    PORT
      LAYER M5 ;
        RECT  48.768 36.528 48.792 36.72 ;
    END
  END dq[365]
  PIN dq[366]
    DIRECTION OUTPUT ;
    USE SIGNAL ;
    PORT
      LAYER M3 ;
        RECT  48.888 36.576 48.906 36.72 ;
    END
  END dq[366]
  PIN dq[367]
    DIRECTION OUTPUT ;
    USE SIGNAL ;
    PORT
      LAYER M5 ;
        RECT  49.008 36.528 49.032 36.72 ;
    END
  END dq[367]
  PIN dq[368]
    DIRECTION OUTPUT ;
    USE SIGNAL ;
    PORT
      LAYER M3 ;
        RECT  49.14 36.576 49.158 36.72 ;
    END
  END dq[368]
  PIN dq[369]
    DIRECTION OUTPUT ;
    USE SIGNAL ;
    PORT
      LAYER M5 ;
        RECT  49.248 36.528 49.272 36.72 ;
    END
  END dq[369]
  PIN dq[36]
    DIRECTION OUTPUT ;
    USE SIGNAL ;
    PORT
      LAYER M3 ;
        RECT  8.748 36.576 8.766 36.72 ;
    END
  END dq[36]
  PIN dq[370]
    DIRECTION OUTPUT ;
    USE SIGNAL ;
    PORT
      LAYER M3 ;
        RECT  49.392 36.576 49.41 36.72 ;
    END
  END dq[370]
  PIN dq[371]
    DIRECTION OUTPUT ;
    USE SIGNAL ;
    PORT
      LAYER M5 ;
        RECT  49.488 36.528 49.512 36.72 ;
    END
  END dq[371]
  PIN dq[372]
    DIRECTION OUTPUT ;
    USE SIGNAL ;
    PORT
      LAYER M3 ;
        RECT  49.608 36.576 49.626 36.72 ;
    END
  END dq[372]
  PIN dq[373]
    DIRECTION OUTPUT ;
    USE SIGNAL ;
    PORT
      LAYER M5 ;
        RECT  49.728 36.528 49.752 36.72 ;
    END
  END dq[373]
  PIN dq[374]
    DIRECTION OUTPUT ;
    USE SIGNAL ;
    PORT
      LAYER M3 ;
        RECT  49.86 36.576 49.878 36.72 ;
    END
  END dq[374]
  PIN dq[375]
    DIRECTION OUTPUT ;
    USE SIGNAL ;
    PORT
      LAYER M5 ;
        RECT  49.968 36.528 49.992 36.72 ;
    END
  END dq[375]
  PIN dq[376]
    DIRECTION OUTPUT ;
    USE SIGNAL ;
    PORT
      LAYER M3 ;
        RECT  50.112 36.576 50.13 36.72 ;
    END
  END dq[376]
  PIN dq[377]
    DIRECTION OUTPUT ;
    USE SIGNAL ;
    PORT
      LAYER M5 ;
        RECT  50.208 36.528 50.232 36.72 ;
    END
  END dq[377]
  PIN dq[378]
    DIRECTION OUTPUT ;
    USE SIGNAL ;
    PORT
      LAYER M3 ;
        RECT  50.364 36.576 50.382 36.72 ;
    END
  END dq[378]
  PIN dq[379]
    DIRECTION OUTPUT ;
    USE SIGNAL ;
    PORT
      LAYER M5 ;
        RECT  50.448 36.528 50.472 36.72 ;
    END
  END dq[379]
  PIN dq[37]
    DIRECTION OUTPUT ;
    USE SIGNAL ;
    PORT
      LAYER M5 ;
        RECT  8.88 36.528 8.904 36.72 ;
    END
  END dq[37]
  PIN dq[380]
    DIRECTION OUTPUT ;
    USE SIGNAL ;
    PORT
      LAYER M3 ;
        RECT  50.58 36.576 50.598 36.72 ;
    END
  END dq[380]
  PIN dq[381]
    DIRECTION OUTPUT ;
    USE SIGNAL ;
    PORT
      LAYER M5 ;
        RECT  50.688 36.528 50.712 36.72 ;
    END
  END dq[381]
  PIN dq[382]
    DIRECTION OUTPUT ;
    USE SIGNAL ;
    PORT
      LAYER M3 ;
        RECT  50.832 36.576 50.85 36.72 ;
    END
  END dq[382]
  PIN dq[383]
    DIRECTION OUTPUT ;
    USE SIGNAL ;
    PORT
      LAYER M5 ;
        RECT  50.976 36.528 51 36.72 ;
    END
  END dq[383]
  PIN dq[384]
    DIRECTION OUTPUT ;
    USE SIGNAL ;
    PORT
      LAYER M3 ;
        RECT  51.084 36.576 51.102 36.72 ;
    END
  END dq[384]
  PIN dq[385]
    DIRECTION OUTPUT ;
    USE SIGNAL ;
    PORT
      LAYER M5 ;
        RECT  51.216 36.528 51.24 36.72 ;
    END
  END dq[385]
  PIN dq[386]
    DIRECTION OUTPUT ;
    USE SIGNAL ;
    PORT
      LAYER M3 ;
        RECT  51.336 36.576 51.354 36.72 ;
    END
  END dq[386]
  PIN dq[387]
    DIRECTION OUTPUT ;
    USE SIGNAL ;
    PORT
      LAYER M5 ;
        RECT  51.456 36.528 51.48 36.72 ;
    END
  END dq[387]
  PIN dq[388]
    DIRECTION OUTPUT ;
    USE SIGNAL ;
    PORT
      LAYER M3 ;
        RECT  51.552 36.576 51.57 36.72 ;
    END
  END dq[388]
  PIN dq[389]
    DIRECTION OUTPUT ;
    USE SIGNAL ;
    PORT
      LAYER M5 ;
        RECT  51.696 36.528 51.72 36.72 ;
    END
  END dq[389]
  PIN dq[38]
    DIRECTION OUTPUT ;
    USE SIGNAL ;
    PORT
      LAYER M3 ;
        RECT  9 36.576 9.018 36.72 ;
    END
  END dq[38]
  PIN dq[390]
    DIRECTION OUTPUT ;
    USE SIGNAL ;
    PORT
      LAYER M3 ;
        RECT  51.804 36.576 51.822 36.72 ;
    END
  END dq[390]
  PIN dq[391]
    DIRECTION OUTPUT ;
    USE SIGNAL ;
    PORT
      LAYER M5 ;
        RECT  51.936 36.528 51.96 36.72 ;
    END
  END dq[391]
  PIN dq[392]
    DIRECTION OUTPUT ;
    USE SIGNAL ;
    PORT
      LAYER M3 ;
        RECT  52.056 36.576 52.074 36.72 ;
    END
  END dq[392]
  PIN dq[393]
    DIRECTION OUTPUT ;
    USE SIGNAL ;
    PORT
      LAYER M5 ;
        RECT  52.176 36.528 52.2 36.72 ;
    END
  END dq[393]
  PIN dq[394]
    DIRECTION OUTPUT ;
    USE SIGNAL ;
    PORT
      LAYER M3 ;
        RECT  52.308 36.576 52.326 36.72 ;
    END
  END dq[394]
  PIN dq[395]
    DIRECTION OUTPUT ;
    USE SIGNAL ;
    PORT
      LAYER M5 ;
        RECT  52.416 36.528 52.44 36.72 ;
    END
  END dq[395]
  PIN dq[396]
    DIRECTION OUTPUT ;
    USE SIGNAL ;
    PORT
      LAYER M3 ;
        RECT  52.524 36.576 52.542 36.72 ;
    END
  END dq[396]
  PIN dq[397]
    DIRECTION OUTPUT ;
    USE SIGNAL ;
    PORT
      LAYER M5 ;
        RECT  52.656 36.528 52.68 36.72 ;
    END
  END dq[397]
  PIN dq[398]
    DIRECTION OUTPUT ;
    USE SIGNAL ;
    PORT
      LAYER M3 ;
        RECT  52.776 36.576 52.794 36.72 ;
    END
  END dq[398]
  PIN dq[399]
    DIRECTION OUTPUT ;
    USE SIGNAL ;
    PORT
      LAYER M5 ;
        RECT  52.896 36.528 52.92 36.72 ;
    END
  END dq[399]
  PIN dq[39]
    DIRECTION OUTPUT ;
    USE SIGNAL ;
    PORT
      LAYER M5 ;
        RECT  9.12 36.528 9.144 36.72 ;
    END
  END dq[39]
  PIN dq[3]
    DIRECTION OUTPUT ;
    USE SIGNAL ;
    PORT
      LAYER M5 ;
        RECT  4.752 36.528 4.776 36.72 ;
    END
  END dq[3]
  PIN dq[400]
    DIRECTION OUTPUT ;
    USE SIGNAL ;
    PORT
      LAYER M3 ;
        RECT  53.028 36.576 53.046 36.72 ;
    END
  END dq[400]
  PIN dq[401]
    DIRECTION OUTPUT ;
    USE SIGNAL ;
    PORT
      LAYER M5 ;
        RECT  53.136 36.528 53.16 36.72 ;
    END
  END dq[401]
  PIN dq[402]
    DIRECTION OUTPUT ;
    USE SIGNAL ;
    PORT
      LAYER M3 ;
        RECT  53.28 36.576 53.298 36.72 ;
    END
  END dq[402]
  PIN dq[403]
    DIRECTION OUTPUT ;
    USE SIGNAL ;
    PORT
      LAYER M5 ;
        RECT  53.376 36.528 53.4 36.72 ;
    END
  END dq[403]
  PIN dq[404]
    DIRECTION OUTPUT ;
    USE SIGNAL ;
    PORT
      LAYER M3 ;
        RECT  53.496 36.576 53.514 36.72 ;
    END
  END dq[404]
  PIN dq[405]
    DIRECTION OUTPUT ;
    USE SIGNAL ;
    PORT
      LAYER M5 ;
        RECT  53.616 36.528 53.64 36.72 ;
    END
  END dq[405]
  PIN dq[406]
    DIRECTION OUTPUT ;
    USE SIGNAL ;
    PORT
      LAYER M3 ;
        RECT  53.748 36.576 53.766 36.72 ;
    END
  END dq[406]
  PIN dq[407]
    DIRECTION OUTPUT ;
    USE SIGNAL ;
    PORT
      LAYER M5 ;
        RECT  53.856 36.528 53.88 36.72 ;
    END
  END dq[407]
  PIN dq[408]
    DIRECTION OUTPUT ;
    USE SIGNAL ;
    PORT
      LAYER M3 ;
        RECT  54 36.576 54.018 36.72 ;
    END
  END dq[408]
  PIN dq[409]
    DIRECTION OUTPUT ;
    USE SIGNAL ;
    PORT
      LAYER M5 ;
        RECT  54.096 36.528 54.12 36.72 ;
    END
  END dq[409]
  PIN dq[40]
    DIRECTION OUTPUT ;
    USE SIGNAL ;
    PORT
      LAYER M3 ;
        RECT  9.252 36.576 9.27 36.72 ;
    END
  END dq[40]
  PIN dq[410]
    DIRECTION OUTPUT ;
    USE SIGNAL ;
    PORT
      LAYER M3 ;
        RECT  54.252 36.576 54.27 36.72 ;
    END
  END dq[410]
  PIN dq[411]
    DIRECTION OUTPUT ;
    USE SIGNAL ;
    PORT
      LAYER M5 ;
        RECT  54.336 36.528 54.36 36.72 ;
    END
  END dq[411]
  PIN dq[412]
    DIRECTION OUTPUT ;
    USE SIGNAL ;
    PORT
      LAYER M3 ;
        RECT  54.468 36.576 54.486 36.72 ;
    END
  END dq[412]
  PIN dq[413]
    DIRECTION OUTPUT ;
    USE SIGNAL ;
    PORT
      LAYER M5 ;
        RECT  54.624 36.528 54.648 36.72 ;
    END
  END dq[413]
  PIN dq[414]
    DIRECTION OUTPUT ;
    USE SIGNAL ;
    PORT
      LAYER M3 ;
        RECT  54.72 36.576 54.738 36.72 ;
    END
  END dq[414]
  PIN dq[415]
    DIRECTION OUTPUT ;
    USE SIGNAL ;
    PORT
      LAYER M5 ;
        RECT  54.864 36.528 54.888 36.72 ;
    END
  END dq[415]
  PIN dq[416]
    DIRECTION OUTPUT ;
    USE SIGNAL ;
    PORT
      LAYER M3 ;
        RECT  54.972 36.576 54.99 36.72 ;
    END
  END dq[416]
  PIN dq[417]
    DIRECTION OUTPUT ;
    USE SIGNAL ;
    PORT
      LAYER M5 ;
        RECT  55.104 36.528 55.128 36.72 ;
    END
  END dq[417]
  PIN dq[418]
    DIRECTION OUTPUT ;
    USE SIGNAL ;
    PORT
      LAYER M3 ;
        RECT  55.224 36.576 55.242 36.72 ;
    END
  END dq[418]
  PIN dq[419]
    DIRECTION OUTPUT ;
    USE SIGNAL ;
    PORT
      LAYER M5 ;
        RECT  55.344 36.528 55.368 36.72 ;
    END
  END dq[419]
  PIN dq[41]
    DIRECTION OUTPUT ;
    USE SIGNAL ;
    PORT
      LAYER M5 ;
        RECT  9.36 36.528 9.384 36.72 ;
    END
  END dq[41]
  PIN dq[420]
    DIRECTION OUTPUT ;
    USE SIGNAL ;
    PORT
      LAYER M3 ;
        RECT  55.44 36.576 55.458 36.72 ;
    END
  END dq[420]
  PIN dq[421]
    DIRECTION OUTPUT ;
    USE SIGNAL ;
    PORT
      LAYER M5 ;
        RECT  55.584 36.528 55.608 36.72 ;
    END
  END dq[421]
  PIN dq[422]
    DIRECTION OUTPUT ;
    USE SIGNAL ;
    PORT
      LAYER M3 ;
        RECT  55.692 36.576 55.71 36.72 ;
    END
  END dq[422]
  PIN dq[423]
    DIRECTION OUTPUT ;
    USE SIGNAL ;
    PORT
      LAYER M5 ;
        RECT  55.824 36.528 55.848 36.72 ;
    END
  END dq[423]
  PIN dq[424]
    DIRECTION OUTPUT ;
    USE SIGNAL ;
    PORT
      LAYER M3 ;
        RECT  55.944 36.576 55.962 36.72 ;
    END
  END dq[424]
  PIN dq[425]
    DIRECTION OUTPUT ;
    USE SIGNAL ;
    PORT
      LAYER M5 ;
        RECT  56.064 36.528 56.088 36.72 ;
    END
  END dq[425]
  PIN dq[426]
    DIRECTION OUTPUT ;
    USE SIGNAL ;
    PORT
      LAYER M3 ;
        RECT  56.196 36.576 56.214 36.72 ;
    END
  END dq[426]
  PIN dq[427]
    DIRECTION OUTPUT ;
    USE SIGNAL ;
    PORT
      LAYER M5 ;
        RECT  56.304 36.528 56.328 36.72 ;
    END
  END dq[427]
  PIN dq[428]
    DIRECTION OUTPUT ;
    USE SIGNAL ;
    PORT
      LAYER M3 ;
        RECT  56.412 36.576 56.43 36.72 ;
    END
  END dq[428]
  PIN dq[429]
    DIRECTION OUTPUT ;
    USE SIGNAL ;
    PORT
      LAYER M5 ;
        RECT  56.544 36.528 56.568 36.72 ;
    END
  END dq[429]
  PIN dq[42]
    DIRECTION OUTPUT ;
    USE SIGNAL ;
    PORT
      LAYER M3 ;
        RECT  9.468 36.576 9.486 36.72 ;
    END
  END dq[42]
  PIN dq[430]
    DIRECTION OUTPUT ;
    USE SIGNAL ;
    PORT
      LAYER M3 ;
        RECT  56.664 36.576 56.682 36.72 ;
    END
  END dq[430]
  PIN dq[431]
    DIRECTION OUTPUT ;
    USE SIGNAL ;
    PORT
      LAYER M5 ;
        RECT  56.784 36.528 56.808 36.72 ;
    END
  END dq[431]
  PIN dq[432]
    DIRECTION OUTPUT ;
    USE SIGNAL ;
    PORT
      LAYER M3 ;
        RECT  56.916 36.576 56.934 36.72 ;
    END
  END dq[432]
  PIN dq[433]
    DIRECTION OUTPUT ;
    USE SIGNAL ;
    PORT
      LAYER M5 ;
        RECT  57.024 36.528 57.048 36.72 ;
    END
  END dq[433]
  PIN dq[434]
    DIRECTION OUTPUT ;
    USE SIGNAL ;
    PORT
      LAYER M3 ;
        RECT  57.168 36.576 57.186 36.72 ;
    END
  END dq[434]
  PIN dq[435]
    DIRECTION OUTPUT ;
    USE SIGNAL ;
    PORT
      LAYER M5 ;
        RECT  57.264 36.528 57.288 36.72 ;
    END
  END dq[435]
  PIN dq[436]
    DIRECTION OUTPUT ;
    USE SIGNAL ;
    PORT
      LAYER M3 ;
        RECT  57.42 36.576 57.438 36.72 ;
    END
  END dq[436]
  PIN dq[437]
    DIRECTION OUTPUT ;
    USE SIGNAL ;
    PORT
      LAYER M5 ;
        RECT  57.504 36.528 57.528 36.72 ;
    END
  END dq[437]
  PIN dq[438]
    DIRECTION OUTPUT ;
    USE SIGNAL ;
    PORT
      LAYER M3 ;
        RECT  57.636 36.576 57.654 36.72 ;
    END
  END dq[438]
  PIN dq[439]
    DIRECTION OUTPUT ;
    USE SIGNAL ;
    PORT
      LAYER M5 ;
        RECT  57.744 36.528 57.768 36.72 ;
    END
  END dq[439]
  PIN dq[43]
    DIRECTION OUTPUT ;
    USE SIGNAL ;
    PORT
      LAYER M5 ;
        RECT  9.6 36.528 9.624 36.72 ;
    END
  END dq[43]
  PIN dq[440]
    DIRECTION OUTPUT ;
    USE SIGNAL ;
    PORT
      LAYER M3 ;
        RECT  57.888 36.576 57.906 36.72 ;
    END
  END dq[440]
  PIN dq[441]
    DIRECTION OUTPUT ;
    USE SIGNAL ;
    PORT
      LAYER M5 ;
        RECT  58.032 36.528 58.056 36.72 ;
    END
  END dq[441]
  PIN dq[442]
    DIRECTION OUTPUT ;
    USE SIGNAL ;
    PORT
      LAYER M3 ;
        RECT  58.14 36.576 58.158 36.72 ;
    END
  END dq[442]
  PIN dq[443]
    DIRECTION OUTPUT ;
    USE SIGNAL ;
    PORT
      LAYER M5 ;
        RECT  58.272 36.528 58.296 36.72 ;
    END
  END dq[443]
  PIN dq[444]
    DIRECTION OUTPUT ;
    USE SIGNAL ;
    PORT
      LAYER M3 ;
        RECT  58.392 36.576 58.41 36.72 ;
    END
  END dq[444]
  PIN dq[445]
    DIRECTION OUTPUT ;
    USE SIGNAL ;
    PORT
      LAYER M5 ;
        RECT  58.512 36.528 58.536 36.72 ;
    END
  END dq[445]
  PIN dq[446]
    DIRECTION OUTPUT ;
    USE SIGNAL ;
    PORT
      LAYER M3 ;
        RECT  58.608 36.576 58.626 36.72 ;
    END
  END dq[446]
  PIN dq[447]
    DIRECTION OUTPUT ;
    USE SIGNAL ;
    PORT
      LAYER M5 ;
        RECT  58.752 36.528 58.776 36.72 ;
    END
  END dq[447]
  PIN dq[448]
    DIRECTION OUTPUT ;
    USE SIGNAL ;
    PORT
      LAYER M3 ;
        RECT  58.86 36.576 58.878 36.72 ;
    END
  END dq[448]
  PIN dq[449]
    DIRECTION OUTPUT ;
    USE SIGNAL ;
    PORT
      LAYER M5 ;
        RECT  58.992 36.528 59.016 36.72 ;
    END
  END dq[449]
  PIN dq[44]
    DIRECTION OUTPUT ;
    USE SIGNAL ;
    PORT
      LAYER M3 ;
        RECT  9.72 36.576 9.738 36.72 ;
    END
  END dq[44]
  PIN dq[450]
    DIRECTION OUTPUT ;
    USE SIGNAL ;
    PORT
      LAYER M3 ;
        RECT  59.112 36.576 59.13 36.72 ;
    END
  END dq[450]
  PIN dq[451]
    DIRECTION OUTPUT ;
    USE SIGNAL ;
    PORT
      LAYER M5 ;
        RECT  59.232 36.528 59.256 36.72 ;
    END
  END dq[451]
  PIN dq[452]
    DIRECTION OUTPUT ;
    USE SIGNAL ;
    PORT
      LAYER M3 ;
        RECT  59.364 36.576 59.382 36.72 ;
    END
  END dq[452]
  PIN dq[453]
    DIRECTION OUTPUT ;
    USE SIGNAL ;
    PORT
      LAYER M5 ;
        RECT  59.472 36.528 59.496 36.72 ;
    END
  END dq[453]
  PIN dq[454]
    DIRECTION OUTPUT ;
    USE SIGNAL ;
    PORT
      LAYER M3 ;
        RECT  59.58 36.576 59.598 36.72 ;
    END
  END dq[454]
  PIN dq[455]
    DIRECTION OUTPUT ;
    USE SIGNAL ;
    PORT
      LAYER M5 ;
        RECT  59.712 36.528 59.736 36.72 ;
    END
  END dq[455]
  PIN dq[456]
    DIRECTION OUTPUT ;
    USE SIGNAL ;
    PORT
      LAYER M3 ;
        RECT  59.832 36.576 59.85 36.72 ;
    END
  END dq[456]
  PIN dq[457]
    DIRECTION OUTPUT ;
    USE SIGNAL ;
    PORT
      LAYER M5 ;
        RECT  59.952 36.528 59.976 36.72 ;
    END
  END dq[457]
  PIN dq[458]
    DIRECTION OUTPUT ;
    USE SIGNAL ;
    PORT
      LAYER M3 ;
        RECT  60.084 36.576 60.102 36.72 ;
    END
  END dq[458]
  PIN dq[459]
    DIRECTION OUTPUT ;
    USE SIGNAL ;
    PORT
      LAYER M5 ;
        RECT  60.192 36.528 60.216 36.72 ;
    END
  END dq[459]
  PIN dq[45]
    DIRECTION OUTPUT ;
    USE SIGNAL ;
    PORT
      LAYER M5 ;
        RECT  9.84 36.528 9.864 36.72 ;
    END
  END dq[45]
  PIN dq[460]
    DIRECTION OUTPUT ;
    USE SIGNAL ;
    PORT
      LAYER M3 ;
        RECT  60.336 36.576 60.354 36.72 ;
    END
  END dq[460]
  PIN dq[461]
    DIRECTION OUTPUT ;
    USE SIGNAL ;
    PORT
      LAYER M5 ;
        RECT  60.432 36.528 60.456 36.72 ;
    END
  END dq[461]
  PIN dq[462]
    DIRECTION OUTPUT ;
    USE SIGNAL ;
    PORT
      LAYER M3 ;
        RECT  60.552 36.576 60.57 36.72 ;
    END
  END dq[462]
  PIN dq[463]
    DIRECTION OUTPUT ;
    USE SIGNAL ;
    PORT
      LAYER M5 ;
        RECT  60.672 36.528 60.696 36.72 ;
    END
  END dq[463]
  PIN dq[464]
    DIRECTION OUTPUT ;
    USE SIGNAL ;
    PORT
      LAYER M3 ;
        RECT  60.804 36.576 60.822 36.72 ;
    END
  END dq[464]
  PIN dq[465]
    DIRECTION OUTPUT ;
    USE SIGNAL ;
    PORT
      LAYER M5 ;
        RECT  60.912 36.528 60.936 36.72 ;
    END
  END dq[465]
  PIN dq[466]
    DIRECTION OUTPUT ;
    USE SIGNAL ;
    PORT
      LAYER M3 ;
        RECT  61.056 36.576 61.074 36.72 ;
    END
  END dq[466]
  PIN dq[467]
    DIRECTION OUTPUT ;
    USE SIGNAL ;
    PORT
      LAYER M5 ;
        RECT  61.152 36.528 61.176 36.72 ;
    END
  END dq[467]
  PIN dq[468]
    DIRECTION OUTPUT ;
    USE SIGNAL ;
    PORT
      LAYER M3 ;
        RECT  61.308 36.576 61.326 36.72 ;
    END
  END dq[468]
  PIN dq[469]
    DIRECTION OUTPUT ;
    USE SIGNAL ;
    PORT
      LAYER M5 ;
        RECT  61.392 36.528 61.416 36.72 ;
    END
  END dq[469]
  PIN dq[46]
    DIRECTION OUTPUT ;
    USE SIGNAL ;
    PORT
      LAYER M3 ;
        RECT  9.972 36.576 9.99 36.72 ;
    END
  END dq[46]
  PIN dq[470]
    DIRECTION OUTPUT ;
    USE SIGNAL ;
    PORT
      LAYER M3 ;
        RECT  61.524 36.576 61.542 36.72 ;
    END
  END dq[470]
  PIN dq[471]
    DIRECTION OUTPUT ;
    USE SIGNAL ;
    PORT
      LAYER M5 ;
        RECT  61.68 36.528 61.704 36.72 ;
    END
  END dq[471]
  PIN dq[472]
    DIRECTION OUTPUT ;
    USE SIGNAL ;
    PORT
      LAYER M3 ;
        RECT  61.776 36.576 61.794 36.72 ;
    END
  END dq[472]
  PIN dq[473]
    DIRECTION OUTPUT ;
    USE SIGNAL ;
    PORT
      LAYER M5 ;
        RECT  61.92 36.528 61.944 36.72 ;
    END
  END dq[473]
  PIN dq[474]
    DIRECTION OUTPUT ;
    USE SIGNAL ;
    PORT
      LAYER M3 ;
        RECT  62.028 36.576 62.046 36.72 ;
    END
  END dq[474]
  PIN dq[475]
    DIRECTION OUTPUT ;
    USE SIGNAL ;
    PORT
      LAYER M5 ;
        RECT  62.16 36.528 62.184 36.72 ;
    END
  END dq[475]
  PIN dq[476]
    DIRECTION OUTPUT ;
    USE SIGNAL ;
    PORT
      LAYER M3 ;
        RECT  62.28 36.576 62.298 36.72 ;
    END
  END dq[476]
  PIN dq[477]
    DIRECTION OUTPUT ;
    USE SIGNAL ;
    PORT
      LAYER M5 ;
        RECT  62.4 36.528 62.424 36.72 ;
    END
  END dq[477]
  PIN dq[478]
    DIRECTION OUTPUT ;
    USE SIGNAL ;
    PORT
      LAYER M3 ;
        RECT  62.496 36.576 62.514 36.72 ;
    END
  END dq[478]
  PIN dq[479]
    DIRECTION OUTPUT ;
    USE SIGNAL ;
    PORT
      LAYER M5 ;
        RECT  62.64 36.528 62.664 36.72 ;
    END
  END dq[479]
  PIN dq[47]
    DIRECTION OUTPUT ;
    USE SIGNAL ;
    PORT
      LAYER M5 ;
        RECT  10.08 36.528 10.104 36.72 ;
    END
  END dq[47]
  PIN dq[480]
    DIRECTION OUTPUT ;
    USE SIGNAL ;
    PORT
      LAYER M3 ;
        RECT  62.748 36.576 62.766 36.72 ;
    END
  END dq[480]
  PIN dq[481]
    DIRECTION OUTPUT ;
    USE SIGNAL ;
    PORT
      LAYER M5 ;
        RECT  62.88 36.528 62.904 36.72 ;
    END
  END dq[481]
  PIN dq[482]
    DIRECTION OUTPUT ;
    USE SIGNAL ;
    PORT
      LAYER M3 ;
        RECT  63 36.576 63.018 36.72 ;
    END
  END dq[482]
  PIN dq[483]
    DIRECTION OUTPUT ;
    USE SIGNAL ;
    PORT
      LAYER M5 ;
        RECT  63.12 36.528 63.144 36.72 ;
    END
  END dq[483]
  PIN dq[484]
    DIRECTION OUTPUT ;
    USE SIGNAL ;
    PORT
      LAYER M3 ;
        RECT  63.252 36.576 63.27 36.72 ;
    END
  END dq[484]
  PIN dq[485]
    DIRECTION OUTPUT ;
    USE SIGNAL ;
    PORT
      LAYER M5 ;
        RECT  63.36 36.528 63.384 36.72 ;
    END
  END dq[485]
  PIN dq[486]
    DIRECTION OUTPUT ;
    USE SIGNAL ;
    PORT
      LAYER M3 ;
        RECT  63.468 36.576 63.486 36.72 ;
    END
  END dq[486]
  PIN dq[487]
    DIRECTION OUTPUT ;
    USE SIGNAL ;
    PORT
      LAYER M5 ;
        RECT  63.6 36.528 63.624 36.72 ;
    END
  END dq[487]
  PIN dq[488]
    DIRECTION OUTPUT ;
    USE SIGNAL ;
    PORT
      LAYER M3 ;
        RECT  63.72 36.576 63.738 36.72 ;
    END
  END dq[488]
  PIN dq[489]
    DIRECTION OUTPUT ;
    USE SIGNAL ;
    PORT
      LAYER M5 ;
        RECT  63.84 36.528 63.864 36.72 ;
    END
  END dq[489]
  PIN dq[48]
    DIRECTION OUTPUT ;
    USE SIGNAL ;
    PORT
      LAYER M3 ;
        RECT  10.224 36.576 10.242 36.72 ;
    END
  END dq[48]
  PIN dq[490]
    DIRECTION OUTPUT ;
    USE SIGNAL ;
    PORT
      LAYER M3 ;
        RECT  63.972 36.576 63.99 36.72 ;
    END
  END dq[490]
  PIN dq[491]
    DIRECTION OUTPUT ;
    USE SIGNAL ;
    PORT
      LAYER M5 ;
        RECT  64.08 36.528 64.104 36.72 ;
    END
  END dq[491]
  PIN dq[492]
    DIRECTION OUTPUT ;
    USE SIGNAL ;
    PORT
      LAYER M3 ;
        RECT  64.224 36.576 64.242 36.72 ;
    END
  END dq[492]
  PIN dq[493]
    DIRECTION OUTPUT ;
    USE SIGNAL ;
    PORT
      LAYER M5 ;
        RECT  64.32 36.528 64.344 36.72 ;
    END
  END dq[493]
  PIN dq[494]
    DIRECTION OUTPUT ;
    USE SIGNAL ;
    PORT
      LAYER M3 ;
        RECT  64.44 36.576 64.458 36.72 ;
    END
  END dq[494]
  PIN dq[495]
    DIRECTION OUTPUT ;
    USE SIGNAL ;
    PORT
      LAYER M5 ;
        RECT  64.56 36.528 64.584 36.72 ;
    END
  END dq[495]
  PIN dq[496]
    DIRECTION OUTPUT ;
    USE SIGNAL ;
    PORT
      LAYER M3 ;
        RECT  64.692 36.576 64.71 36.72 ;
    END
  END dq[496]
  PIN dq[497]
    DIRECTION OUTPUT ;
    USE SIGNAL ;
    PORT
      LAYER M5 ;
        RECT  64.8 36.528 64.824 36.72 ;
    END
  END dq[497]
  PIN dq[498]
    DIRECTION OUTPUT ;
    USE SIGNAL ;
    PORT
      LAYER M3 ;
        RECT  64.944 36.576 64.962 36.72 ;
    END
  END dq[498]
  PIN dq[499]
    DIRECTION OUTPUT ;
    USE SIGNAL ;
    PORT
      LAYER M5 ;
        RECT  65.04 36.528 65.064 36.72 ;
    END
  END dq[499]
  PIN dq[49]
    DIRECTION OUTPUT ;
    USE SIGNAL ;
    PORT
      LAYER M5 ;
        RECT  10.32 36.528 10.344 36.72 ;
    END
  END dq[49]
  PIN dq[4]
    DIRECTION OUTPUT ;
    USE SIGNAL ;
    PORT
      LAYER M3 ;
        RECT  4.86 36.576 4.878 36.72 ;
    END
  END dq[4]
  PIN dq[500]
    DIRECTION OUTPUT ;
    USE SIGNAL ;
    PORT
      LAYER M3 ;
        RECT  65.196 36.576 65.214 36.72 ;
    END
  END dq[500]
  PIN dq[501]
    DIRECTION OUTPUT ;
    USE SIGNAL ;
    PORT
      LAYER M5 ;
        RECT  65.328 36.528 65.352 36.72 ;
    END
  END dq[501]
  PIN dq[502]
    DIRECTION OUTPUT ;
    USE SIGNAL ;
    PORT
      LAYER M3 ;
        RECT  65.448 36.576 65.466 36.72 ;
    END
  END dq[502]
  PIN dq[503]
    DIRECTION OUTPUT ;
    USE SIGNAL ;
    PORT
      LAYER M5 ;
        RECT  65.568 36.528 65.592 36.72 ;
    END
  END dq[503]
  PIN dq[504]
    DIRECTION OUTPUT ;
    USE SIGNAL ;
    PORT
      LAYER M3 ;
        RECT  65.664 36.576 65.682 36.72 ;
    END
  END dq[504]
  PIN dq[505]
    DIRECTION OUTPUT ;
    USE SIGNAL ;
    PORT
      LAYER M5 ;
        RECT  65.808 36.528 65.832 36.72 ;
    END
  END dq[505]
  PIN dq[506]
    DIRECTION OUTPUT ;
    USE SIGNAL ;
    PORT
      LAYER M3 ;
        RECT  65.916 36.576 65.934 36.72 ;
    END
  END dq[506]
  PIN dq[507]
    DIRECTION OUTPUT ;
    USE SIGNAL ;
    PORT
      LAYER M5 ;
        RECT  66.048 36.528 66.072 36.72 ;
    END
  END dq[507]
  PIN dq[508]
    DIRECTION OUTPUT ;
    USE SIGNAL ;
    PORT
      LAYER M3 ;
        RECT  66.168 36.576 66.186 36.72 ;
    END
  END dq[508]
  PIN dq[509]
    DIRECTION OUTPUT ;
    USE SIGNAL ;
    PORT
      LAYER M5 ;
        RECT  66.288 36.528 66.312 36.72 ;
    END
  END dq[509]
  PIN dq[50]
    DIRECTION OUTPUT ;
    USE SIGNAL ;
    PORT
      LAYER M3 ;
        RECT  10.44 36.576 10.458 36.72 ;
    END
  END dq[50]
  PIN dq[510]
    DIRECTION OUTPUT ;
    USE SIGNAL ;
    PORT
      LAYER M3 ;
        RECT  66.42 36.576 66.438 36.72 ;
    END
  END dq[510]
  PIN dq[511]
    DIRECTION OUTPUT ;
    USE SIGNAL ;
    PORT
      LAYER M5 ;
        RECT  66.528 36.528 66.552 36.72 ;
    END
  END dq[511]
  PIN dq[512]
    DIRECTION OUTPUT ;
    USE SIGNAL ;
    PORT
      LAYER M3 ;
        RECT  66.636 36.576 66.654 36.72 ;
    END
  END dq[512]
  PIN dq[513]
    DIRECTION OUTPUT ;
    USE SIGNAL ;
    PORT
      LAYER M5 ;
        RECT  66.768 36.528 66.792 36.72 ;
    END
  END dq[513]
  PIN dq[514]
    DIRECTION OUTPUT ;
    USE SIGNAL ;
    PORT
      LAYER M3 ;
        RECT  66.888 36.576 66.906 36.72 ;
    END
  END dq[514]
  PIN dq[51]
    DIRECTION OUTPUT ;
    USE SIGNAL ;
    PORT
      LAYER M5 ;
        RECT  10.56 36.528 10.584 36.72 ;
    END
  END dq[51]
  PIN dq[52]
    DIRECTION OUTPUT ;
    USE SIGNAL ;
    PORT
      LAYER M3 ;
        RECT  10.692 36.576 10.71 36.72 ;
    END
  END dq[52]
  PIN dq[53]
    DIRECTION OUTPUT ;
    USE SIGNAL ;
    PORT
      LAYER M5 ;
        RECT  10.8 36.528 10.824 36.72 ;
    END
  END dq[53]
  PIN dq[54]
    DIRECTION OUTPUT ;
    USE SIGNAL ;
    PORT
      LAYER M3 ;
        RECT  10.944 36.576 10.962 36.72 ;
    END
  END dq[54]
  PIN dq[55]
    DIRECTION OUTPUT ;
    USE SIGNAL ;
    PORT
      LAYER M5 ;
        RECT  11.04 36.528 11.064 36.72 ;
    END
  END dq[55]
  PIN dq[56]
    DIRECTION OUTPUT ;
    USE SIGNAL ;
    PORT
      LAYER M3 ;
        RECT  11.196 36.576 11.214 36.72 ;
    END
  END dq[56]
  PIN dq[57]
    DIRECTION OUTPUT ;
    USE SIGNAL ;
    PORT
      LAYER M5 ;
        RECT  11.28 36.528 11.304 36.72 ;
    END
  END dq[57]
  PIN dq[58]
    DIRECTION OUTPUT ;
    USE SIGNAL ;
    PORT
      LAYER M3 ;
        RECT  11.412 36.576 11.43 36.72 ;
    END
  END dq[58]
  PIN dq[59]
    DIRECTION OUTPUT ;
    USE SIGNAL ;
    PORT
      LAYER M5 ;
        RECT  11.568 36.528 11.592 36.72 ;
    END
  END dq[59]
  PIN dq[5]
    DIRECTION OUTPUT ;
    USE SIGNAL ;
    PORT
      LAYER M5 ;
        RECT  4.992 36.528 5.016 36.72 ;
    END
  END dq[5]
  PIN dq[60]
    DIRECTION OUTPUT ;
    USE SIGNAL ;
    PORT
      LAYER M3 ;
        RECT  11.664 36.576 11.682 36.72 ;
    END
  END dq[60]
  PIN dq[61]
    DIRECTION OUTPUT ;
    USE SIGNAL ;
    PORT
      LAYER M5 ;
        RECT  11.808 36.528 11.832 36.72 ;
    END
  END dq[61]
  PIN dq[62]
    DIRECTION OUTPUT ;
    USE SIGNAL ;
    PORT
      LAYER M3 ;
        RECT  11.916 36.576 11.934 36.72 ;
    END
  END dq[62]
  PIN dq[63]
    DIRECTION OUTPUT ;
    USE SIGNAL ;
    PORT
      LAYER M5 ;
        RECT  12.048 36.528 12.072 36.72 ;
    END
  END dq[63]
  PIN dq[64]
    DIRECTION OUTPUT ;
    USE SIGNAL ;
    PORT
      LAYER M3 ;
        RECT  12.168 36.576 12.186 36.72 ;
    END
  END dq[64]
  PIN dq[65]
    DIRECTION OUTPUT ;
    USE SIGNAL ;
    PORT
      LAYER M5 ;
        RECT  12.288 36.528 12.312 36.72 ;
    END
  END dq[65]
  PIN dq[66]
    DIRECTION OUTPUT ;
    USE SIGNAL ;
    PORT
      LAYER M3 ;
        RECT  12.384 36.576 12.402 36.72 ;
    END
  END dq[66]
  PIN dq[67]
    DIRECTION OUTPUT ;
    USE SIGNAL ;
    PORT
      LAYER M5 ;
        RECT  12.528 36.528 12.552 36.72 ;
    END
  END dq[67]
  PIN dq[68]
    DIRECTION OUTPUT ;
    USE SIGNAL ;
    PORT
      LAYER M3 ;
        RECT  12.636 36.576 12.654 36.72 ;
    END
  END dq[68]
  PIN dq[69]
    DIRECTION OUTPUT ;
    USE SIGNAL ;
    PORT
      LAYER M5 ;
        RECT  12.768 36.528 12.792 36.72 ;
    END
  END dq[69]
  PIN dq[6]
    DIRECTION OUTPUT ;
    USE SIGNAL ;
    PORT
      LAYER M3 ;
        RECT  5.112 36.576 5.13 36.72 ;
    END
  END dq[6]
  PIN dq[70]
    DIRECTION OUTPUT ;
    USE SIGNAL ;
    PORT
      LAYER M3 ;
        RECT  12.888 36.576 12.906 36.72 ;
    END
  END dq[70]
  PIN dq[71]
    DIRECTION OUTPUT ;
    USE SIGNAL ;
    PORT
      LAYER M5 ;
        RECT  13.008 36.528 13.032 36.72 ;
    END
  END dq[71]
  PIN dq[72]
    DIRECTION OUTPUT ;
    USE SIGNAL ;
    PORT
      LAYER M3 ;
        RECT  13.14 36.576 13.158 36.72 ;
    END
  END dq[72]
  PIN dq[73]
    DIRECTION OUTPUT ;
    USE SIGNAL ;
    PORT
      LAYER M5 ;
        RECT  13.248 36.528 13.272 36.72 ;
    END
  END dq[73]
  PIN dq[74]
    DIRECTION OUTPUT ;
    USE SIGNAL ;
    PORT
      LAYER M3 ;
        RECT  13.356 36.576 13.374 36.72 ;
    END
  END dq[74]
  PIN dq[75]
    DIRECTION OUTPUT ;
    USE SIGNAL ;
    PORT
      LAYER M5 ;
        RECT  13.488 36.528 13.512 36.72 ;
    END
  END dq[75]
  PIN dq[76]
    DIRECTION OUTPUT ;
    USE SIGNAL ;
    PORT
      LAYER M3 ;
        RECT  13.608 36.576 13.626 36.72 ;
    END
  END dq[76]
  PIN dq[77]
    DIRECTION OUTPUT ;
    USE SIGNAL ;
    PORT
      LAYER M5 ;
        RECT  13.728 36.528 13.752 36.72 ;
    END
  END dq[77]
  PIN dq[78]
    DIRECTION OUTPUT ;
    USE SIGNAL ;
    PORT
      LAYER M3 ;
        RECT  13.86 36.576 13.878 36.72 ;
    END
  END dq[78]
  PIN dq[79]
    DIRECTION OUTPUT ;
    USE SIGNAL ;
    PORT
      LAYER M5 ;
        RECT  13.968 36.528 13.992 36.72 ;
    END
  END dq[79]
  PIN dq[7]
    DIRECTION OUTPUT ;
    USE SIGNAL ;
    PORT
      LAYER M5 ;
        RECT  5.232 36.528 5.256 36.72 ;
    END
  END dq[7]
  PIN dq[80]
    DIRECTION OUTPUT ;
    USE SIGNAL ;
    PORT
      LAYER M3 ;
        RECT  14.112 36.576 14.13 36.72 ;
    END
  END dq[80]
  PIN dq[81]
    DIRECTION OUTPUT ;
    USE SIGNAL ;
    PORT
      LAYER M5 ;
        RECT  14.208 36.528 14.232 36.72 ;
    END
  END dq[81]
  PIN dq[82]
    DIRECTION OUTPUT ;
    USE SIGNAL ;
    PORT
      LAYER M3 ;
        RECT  14.328 36.576 14.346 36.72 ;
    END
  END dq[82]
  PIN dq[83]
    DIRECTION OUTPUT ;
    USE SIGNAL ;
    PORT
      LAYER M5 ;
        RECT  14.448 36.528 14.472 36.72 ;
    END
  END dq[83]
  PIN dq[84]
    DIRECTION OUTPUT ;
    USE SIGNAL ;
    PORT
      LAYER M3 ;
        RECT  14.58 36.576 14.598 36.72 ;
    END
  END dq[84]
  PIN dq[85]
    DIRECTION OUTPUT ;
    USE SIGNAL ;
    PORT
      LAYER M5 ;
        RECT  14.688 36.528 14.712 36.72 ;
    END
  END dq[85]
  PIN dq[86]
    DIRECTION OUTPUT ;
    USE SIGNAL ;
    PORT
      LAYER M3 ;
        RECT  14.832 36.576 14.85 36.72 ;
    END
  END dq[86]
  PIN dq[87]
    DIRECTION OUTPUT ;
    USE SIGNAL ;
    PORT
      LAYER M5 ;
        RECT  14.928 36.528 14.952 36.72 ;
    END
  END dq[87]
  PIN dq[88]
    DIRECTION OUTPUT ;
    USE SIGNAL ;
    PORT
      LAYER M3 ;
        RECT  15.084 36.576 15.102 36.72 ;
    END
  END dq[88]
  PIN dq[89]
    DIRECTION OUTPUT ;
    USE SIGNAL ;
    PORT
      LAYER M5 ;
        RECT  15.216 36.528 15.24 36.72 ;
    END
  END dq[89]
  PIN dq[8]
    DIRECTION OUTPUT ;
    USE SIGNAL ;
    PORT
      LAYER M3 ;
        RECT  5.328 36.576 5.346 36.72 ;
    END
  END dq[8]
  PIN dq[90]
    DIRECTION OUTPUT ;
    USE SIGNAL ;
    PORT
      LAYER M3 ;
        RECT  15.336 36.576 15.354 36.72 ;
    END
  END dq[90]
  PIN dq[91]
    DIRECTION OUTPUT ;
    USE SIGNAL ;
    PORT
      LAYER M5 ;
        RECT  15.456 36.528 15.48 36.72 ;
    END
  END dq[91]
  PIN dq[92]
    DIRECTION OUTPUT ;
    USE SIGNAL ;
    PORT
      LAYER M3 ;
        RECT  15.552 36.576 15.57 36.72 ;
    END
  END dq[92]
  PIN dq[93]
    DIRECTION OUTPUT ;
    USE SIGNAL ;
    PORT
      LAYER M5 ;
        RECT  15.696 36.528 15.72 36.72 ;
    END
  END dq[93]
  PIN dq[94]
    DIRECTION OUTPUT ;
    USE SIGNAL ;
    PORT
      LAYER M3 ;
        RECT  15.804 36.576 15.822 36.72 ;
    END
  END dq[94]
  PIN dq[95]
    DIRECTION OUTPUT ;
    USE SIGNAL ;
    PORT
      LAYER M5 ;
        RECT  15.936 36.528 15.96 36.72 ;
    END
  END dq[95]
  PIN dq[96]
    DIRECTION OUTPUT ;
    USE SIGNAL ;
    PORT
      LAYER M3 ;
        RECT  16.056 36.576 16.074 36.72 ;
    END
  END dq[96]
  PIN dq[97]
    DIRECTION OUTPUT ;
    USE SIGNAL ;
    PORT
      LAYER M5 ;
        RECT  16.176 36.528 16.2 36.72 ;
    END
  END dq[97]
  PIN dq[98]
    DIRECTION OUTPUT ;
    USE SIGNAL ;
    PORT
      LAYER M3 ;
        RECT  16.308 36.576 16.326 36.72 ;
    END
  END dq[98]
  PIN dq[99]
    DIRECTION OUTPUT ;
    USE SIGNAL ;
    PORT
      LAYER M5 ;
        RECT  16.416 36.528 16.44 36.72 ;
    END
  END dq[99]
  PIN dq[9]
    DIRECTION OUTPUT ;
    USE SIGNAL ;
    PORT
      LAYER M5 ;
        RECT  5.472 36.528 5.496 36.72 ;
    END
  END dq[9]
  PIN VDD
    DIRECTION INOUT ;
    USE POWER ;
    PORT
      LAYER M5 ;
        RECT  67.392 2.151 67.512 34.569 ;
        RECT  64.692 2.151 64.812 34.569 ;
        RECT  61.992 2.151 62.112 34.569 ;
        RECT  59.292 2.151 59.412 34.569 ;
        RECT  56.592 2.151 56.712 34.569 ;
        RECT  53.892 2.151 54.012 34.569 ;
        RECT  51.192 2.151 51.312 34.569 ;
        RECT  48.492 2.151 48.612 34.569 ;
        RECT  45.792 2.151 45.912 34.569 ;
        RECT  43.092 2.151 43.212 34.569 ;
        RECT  40.392 2.151 40.512 34.569 ;
        RECT  37.692 2.151 37.812 34.569 ;
        RECT  34.992 2.151 35.112 34.569 ;
        RECT  32.292 2.151 32.412 34.569 ;
        RECT  29.592 2.151 29.712 34.569 ;
        RECT  26.892 2.151 27.012 34.569 ;
        RECT  24.192 2.151 24.312 34.569 ;
        RECT  21.492 2.151 21.612 34.569 ;
        RECT  18.792 2.151 18.912 34.569 ;
        RECT  16.092 2.151 16.212 34.569 ;
        RECT  13.392 2.151 13.512 34.569 ;
        RECT  10.692 2.151 10.812 34.569 ;
        RECT  7.992 2.151 8.112 34.569 ;
        RECT  5.292 2.151 5.412 34.569 ;
        RECT  2.592 2.151 2.712 34.569 ;
    END
  END VDD
  PIN VSS
    DIRECTION INOUT ;
    USE GROUND ;
    PORT
      LAYER M5 ;
        RECT  67.2 2.137 67.32 34.583 ;
        RECT  64.5 2.137 64.62 34.583 ;
        RECT  61.8 2.137 61.92 34.583 ;
        RECT  59.1 2.137 59.22 34.583 ;
        RECT  56.4 2.137 56.52 34.583 ;
        RECT  53.7 2.137 53.82 34.583 ;
        RECT  51 2.137 51.12 34.583 ;
        RECT  48.3 2.137 48.42 34.583 ;
        RECT  45.6 2.137 45.72 34.583 ;
        RECT  42.9 2.137 43.02 34.583 ;
        RECT  40.2 2.137 40.32 34.583 ;
        RECT  37.5 2.137 37.62 34.583 ;
        RECT  34.8 2.137 34.92 34.583 ;
        RECT  32.1 2.137 32.22 34.583 ;
        RECT  29.4 2.137 29.52 34.583 ;
        RECT  26.7 2.137 26.82 34.583 ;
        RECT  24 2.137 24.12 34.583 ;
        RECT  21.3 2.137 21.42 34.583 ;
        RECT  18.6 2.137 18.72 34.583 ;
        RECT  15.9 2.137 16.02 34.583 ;
        RECT  13.2 2.137 13.32 34.583 ;
        RECT  10.5 2.137 10.62 34.583 ;
        RECT  7.8 2.137 7.92 34.583 ;
        RECT  5.1 2.137 5.22 34.583 ;
        RECT  2.4 2.137 2.52 34.583 ;
    END
  END VSS
  # OT_OBS_CLOSED layer=M5 d_um=1.536 added=100
  OBS
    LAYER RVTN ;
     RECT  2.16 2.16 69.12 2.295 ;
     RECT  2.16 2.565 69.12 2.835 ;
     RECT  2.16 3.105 69.12 3.375 ;
     RECT  2.16 3.645 69.12 3.915 ;
     RECT  2.16 4.185 69.12 4.455 ;
     RECT  2.16 4.725 69.12 4.995 ;
     RECT  2.16 5.265 69.12 5.535 ;
     RECT  2.16 5.805 69.12 6.075 ;
     RECT  2.16 6.345 69.12 6.615 ;
     RECT  2.16 6.885 69.12 7.155 ;
     RECT  2.16 7.425 69.12 7.695 ;
     RECT  2.16 7.965 69.12 8.235 ;
     RECT  2.16 8.505 69.12 8.775 ;
     RECT  2.16 9.045 69.12 9.315 ;
     RECT  2.16 9.585 69.12 9.855 ;
     RECT  2.16 10.125 69.12 10.395 ;
     RECT  2.16 10.665 69.12 10.935 ;
     RECT  2.16 11.205 69.12 11.475 ;
     RECT  2.16 11.745 69.12 12.015 ;
     RECT  2.16 12.285 69.12 12.555 ;
     RECT  2.16 12.825 69.12 13.095 ;
     RECT  2.16 13.365 69.12 13.635 ;
     RECT  2.16 13.905 69.12 14.175 ;
     RECT  2.16 14.445 69.12 14.715 ;
     RECT  2.16 14.985 69.12 15.255 ;
     RECT  2.16 15.525 69.12 15.795 ;
     RECT  2.16 16.065 69.12 16.335 ;
     RECT  2.16 16.605 69.12 16.875 ;
     RECT  2.16 17.145 69.12 17.415 ;
     RECT  2.16 17.685 69.12 17.955 ;
     RECT  2.16 18.225 69.12 18.495 ;
     RECT  2.16 18.765 69.12 19.035 ;
     RECT  2.16 19.305 69.12 19.575 ;
     RECT  2.16 19.845 69.12 20.115 ;
     RECT  2.16 20.385 69.12 20.655 ;
     RECT  2.16 20.925 69.12 21.195 ;
     RECT  2.16 21.465 69.12 21.735 ;
     RECT  2.16 22.005 69.12 22.275 ;
     RECT  2.16 22.545 69.12 22.815 ;
     RECT  2.16 23.085 69.12 23.355 ;
     RECT  2.16 23.625 69.12 23.895 ;
     RECT  2.16 24.165 69.12 24.435 ;
     RECT  2.16 24.705 69.12 24.975 ;
     RECT  2.16 25.245 69.12 25.515 ;
     RECT  2.16 25.785 69.12 26.055 ;
     RECT  2.16 26.325 69.12 26.595 ;
     RECT  2.16 26.865 69.12 27.135 ;
     RECT  2.16 27.405 69.12 27.675 ;
     RECT  2.16 27.945 69.12 28.215 ;
     RECT  2.16 28.485 69.12 28.755 ;
     RECT  2.16 29.025 69.12 29.295 ;
     RECT  2.16 29.565 69.12 29.835 ;
     RECT  2.16 30.105 69.12 30.375 ;
     RECT  2.16 30.645 69.12 30.915 ;
     RECT  2.16 31.185 69.12 31.455 ;
     RECT  2.16 31.725 69.12 31.995 ;
     RECT  2.16 32.265 69.12 32.535 ;
     RECT  2.16 32.805 69.12 33.075 ;
     RECT  2.16 33.345 69.12 33.615 ;
     RECT  2.16 33.885 69.12 34.155 ;
     RECT  2.16 34.425 69.12 34.56 ;
    LAYER RVTP ;
     RECT  2.16 2.295 69.12 2.565 ;
     RECT  2.16 2.835 69.12 3.105 ;
     RECT  2.16 3.375 69.12 3.645 ;
     RECT  2.16 3.915 69.12 4.185 ;
     RECT  2.16 4.455 69.12 4.725 ;
     RECT  2.16 4.995 69.12 5.265 ;
     RECT  2.16 5.535 69.12 5.805 ;
     RECT  2.16 6.075 69.12 6.345 ;
     RECT  2.16 6.615 69.12 6.885 ;
     RECT  2.16 7.155 69.12 7.425 ;
     RECT  2.16 7.695 69.12 7.965 ;
     RECT  2.16 8.235 69.12 8.505 ;
     RECT  2.16 8.775 69.12 9.045 ;
     RECT  2.16 9.315 69.12 9.585 ;
     RECT  2.16 9.855 69.12 10.125 ;
     RECT  2.16 10.395 69.12 10.665 ;
     RECT  2.16 10.935 69.12 11.205 ;
     RECT  2.16 11.475 69.12 11.745 ;
     RECT  2.16 12.015 69.12 12.285 ;
     RECT  2.16 12.555 69.12 12.825 ;
     RECT  2.16 13.095 69.12 13.365 ;
     RECT  2.16 13.635 69.12 13.905 ;
     RECT  2.16 14.175 69.12 14.445 ;
     RECT  2.16 14.715 69.12 14.985 ;
     RECT  2.16 15.255 69.12 15.525 ;
     RECT  2.16 15.795 69.12 16.065 ;
     RECT  2.16 16.335 69.12 16.605 ;
     RECT  2.16 16.875 69.12 17.145 ;
     RECT  2.16 17.415 69.12 17.685 ;
     RECT  2.16 17.955 69.12 18.225 ;
     RECT  2.16 18.495 69.12 18.765 ;
     RECT  2.16 19.035 69.12 19.305 ;
     RECT  2.16 19.575 69.12 19.845 ;
     RECT  2.16 20.115 69.12 20.385 ;
     RECT  2.16 20.655 69.12 20.925 ;
     RECT  2.16 21.195 69.12 21.465 ;
     RECT  2.16 21.735 69.12 22.005 ;
     RECT  2.16 22.275 69.12 22.545 ;
     RECT  2.16 22.815 69.12 23.085 ;
     RECT  2.16 23.355 69.12 23.625 ;
     RECT  2.16 23.895 69.12 24.165 ;
     RECT  2.16 24.435 69.12 24.705 ;
     RECT  2.16 24.975 69.12 25.245 ;
     RECT  2.16 25.515 69.12 25.785 ;
     RECT  2.16 26.055 69.12 26.325 ;
     RECT  2.16 26.595 69.12 26.865 ;
     RECT  2.16 27.135 69.12 27.405 ;
     RECT  2.16 27.675 69.12 27.945 ;
     RECT  2.16 28.215 69.12 28.485 ;
     RECT  2.16 28.755 69.12 29.025 ;
     RECT  2.16 29.295 69.12 29.565 ;
     RECT  2.16 29.835 69.12 30.105 ;
     RECT  2.16 30.375 69.12 30.645 ;
     RECT  2.16 30.915 69.12 31.185 ;
     RECT  2.16 31.455 69.12 31.725 ;
     RECT  2.16 31.995 69.12 32.265 ;
     RECT  2.16 32.535 69.12 32.805 ;
     RECT  2.16 33.075 69.12 33.345 ;
     RECT  2.16 33.615 69.12 33.885 ;
     RECT  2.16 34.155 69.12 34.425 ;
    LAYER M1 ;
     RECT  2.16 2.151 69.12 34.569 ;
    LAYER M2 ;
     RECT  2.16 2.151 4.135 34.569 ;
     RECT  4.135 2.106 4.243 34.569 ;
     RECT  4.243 2.106 4.927 34.794 ;
     RECT  4.927 2.106 5.099 34.839 ;
     RECT  5.099 2.151 5.135 34.839 ;
     RECT  5.035 0.144 5.351 0.162 ;
     RECT  6.295 0.144 6.395 0.162 ;
     RECT  5.135 2.151 7.771 34.569 ;
     RECT  8.023 0.144 8.159 0.162 ;
     RECT  7.771 1.728 8.699 34.569 ;
     RECT  8.699 2.151 9.247 34.569 ;
     RECT  9.247 2.151 9.463 34.794 ;
     RECT  9.463 0.144 9.563 0.162 ;
     RECT  9.463 2.151 9.599 34.839 ;
     RECT  9.599 2.151 10.175 34.794 ;
     RECT  10.175 2.151 10.939 34.569 ;
     RECT  10.687 1.116 11.435 1.134 ;
     RECT  11.407 0.144 11.507 0.162 ;
     RECT  10.687 35.946 11.543 35.964 ;
     RECT  10.939 2.151 11.659 34.794 ;
     RECT  11.659 2.151 11.939 34.839 ;
     RECT  11.911 35.901 12.379 35.919 ;
     RECT  11.939 2.151 12.515 34.794 ;
     RECT  12.379 35.901 12.515 36 ;
     RECT  12.515 35.901 12.623 35.919 ;
     RECT  12.515 2.151 13.351 34.569 ;
     RECT  13.351 2.151 13.531 34.794 ;
     RECT  13.531 2.106 13.559 34.794 ;
     RECT  13.559 2.106 14.423 34.569 ;
     RECT  14.423 2.151 14.827 34.569 ;
     RECT  14.827 2.151 17.015 34.794 ;
     RECT  17.015 2.151 17.275 34.569 ;
     RECT  17.275 1.728 17.771 34.569 ;
     RECT  17.743 0.144 17.843 0.162 ;
     RECT  17.771 2.151 18.463 34.569 ;
     RECT  18.463 2.151 18.599 34.839 ;
     RECT  18.571 0.144 18.743 0.162 ;
     RECT  18.643 36.558 18.743 36.648 ;
     RECT  18.743 36.63 18.779 36.648 ;
     RECT  18.599 2.151 19.219 34.794 ;
     RECT  19.219 1.728 19.751 34.794 ;
     RECT  19.751 1.728 20.723 34.569 ;
     RECT  20.723 2.151 21.271 34.569 ;
     RECT  21.271 2.151 21.407 34.794 ;
     RECT  21.407 2.151 22.055 34.758 ;
     RECT  22.055 2.151 22.855 34.569 ;
     RECT  21.379 0.144 24.179 0.162 ;
     RECT  22.855 2.151 24.179 34.794 ;
     RECT  25.411 0.144 25.547 0.162 ;
     RECT  26.275 0.144 26.483 0.162 ;
     RECT  24.179 2.151 26.599 34.569 ;
     RECT  26.599 2.151 26.743 34.65 ;
     RECT  26.743 1.728 26.771 34.65 ;
     RECT  26.771 1.728 27.743 34.569 ;
     RECT  27.715 0.144 27.815 0.162 ;
     RECT  27.743 1.8 28.427 34.569 ;
     RECT  28.427 2.151 29.299 34.569 ;
     RECT  29.335 0.144 29.759 0.162 ;
     RECT  29.299 2.151 29.759 34.794 ;
     RECT  30.379 35.946 31.055 35.964 ;
     RECT  29.759 2.151 31.351 34.569 ;
     RECT  32.107 0.144 32.459 0.162 ;
     RECT  31.351 2.151 32.927 34.794 ;
     RECT  33.079 35.982 33.611 36 ;
     RECT  33.799 1.152 33.899 1.17 ;
     RECT  34.951 0.144 35.051 0.162 ;
     RECT  32.927 2.151 35.491 34.569 ;
     RECT  35.275 35.901 35.699 35.919 ;
     RECT  35.491 1.728 36.599 34.569 ;
     RECT  36.463 35.901 36.779 35.919 ;
     RECT  37.219 36.558 37.255 36.576 ;
     RECT  37.255 36.558 37.355 36.648 ;
     RECT  36.599 2.151 37.435 34.569 ;
     RECT  37.435 1.728 37.687 34.569 ;
     RECT  37.687 0.144 37.939 0.162 ;
     RECT  37.939 0.144 38.147 0.234 ;
     RECT  37.687 1.728 38.543 34.794 ;
     RECT  38.147 0.144 38.759 0.162 ;
     RECT  38.543 1.728 39.083 34.569 ;
     RECT  39.083 2.151 39.379 34.569 ;
     RECT  39.379 2.151 40.099 34.758 ;
     RECT  40.099 2.151 40.135 34.794 ;
     RECT  40.135 2.151 40.235 34.956 ;
     RECT  40.235 2.151 40.415 34.884 ;
     RECT  40.415 2.151 40.567 34.794 ;
     RECT  40.567 2.106 40.919 34.794 ;
     RECT  40.919 2.151 42.071 34.794 ;
     RECT  42.079 0.144 42.179 0.162 ;
     RECT  42.071 2.151 42.331 34.569 ;
     RECT  42.331 1.728 43.295 34.569 ;
     RECT  43.295 1.8 43.475 34.569 ;
     RECT  43.475 2.151 44.023 34.569 ;
     RECT  44.023 2.151 44.375 34.794 ;
     RECT  44.375 2.151 44.995 34.569 ;
     RECT  44.995 1.728 45.347 34.569 ;
     RECT  45.347 2.151 45.715 34.569 ;
     RECT  45.715 0.144 45.959 0.162 ;
     RECT  45.967 0.216 46.067 0.234 ;
     RECT  45.715 2.151 46.579 34.794 ;
     RECT  46.579 2.151 46.715 34.839 ;
     RECT  46.715 2.151 47.011 34.794 ;
     RECT  46.939 0.144 47.255 0.162 ;
     RECT  47.011 2.106 47.291 34.794 ;
     RECT  47.291 2.151 47.983 34.794 ;
     RECT  47.983 2.151 48.091 34.839 ;
     RECT  48.091 2.151 48.443 34.884 ;
     RECT  48.443 2.151 48.739 34.794 ;
     RECT  48.631 35.901 48.883 35.919 ;
     RECT  48.739 2.106 49.019 34.794 ;
     RECT  48.883 35.901 49.019 36.036 ;
     RECT  48.415 0.576 49.091 0.594 ;
     RECT  49.019 2.106 49.387 34.569 ;
     RECT  49.019 35.901 50.315 35.919 ;
     RECT  49.387 1.728 50.359 34.569 ;
     RECT  50.359 1.728 51.611 34.794 ;
     RECT  51.547 35.901 51.799 35.919 ;
     RECT  51.611 2.151 51.827 34.794 ;
     RECT  51.799 35.901 52.007 35.964 ;
     RECT  52.007 35.901 52.943 35.919 ;
     RECT  51.827 2.151 53.743 34.569 ;
     RECT  53.275 0.144 53.879 0.162 ;
     RECT  53.743 2.151 53.879 34.65 ;
     RECT  53.879 2.151 53.995 34.569 ;
     RECT  53.995 1.728 54.383 34.569 ;
     RECT  55.435 35.982 55.687 36 ;
     RECT  55.687 35.982 55.715 36.072 ;
     RECT  55.715 36.054 56.255 36.072 ;
     RECT  54.383 2.151 56.263 34.569 ;
     RECT  56.191 1.152 56.291 1.17 ;
     RECT  55.435 0.144 56.435 0.162 ;
     RECT  56.263 2.151 56.435 34.65 ;
     RECT  56.435 2.151 56.911 34.569 ;
     RECT  56.659 35.901 57.407 35.964 ;
     RECT  57.407 35.946 57.515 35.964 ;
     RECT  56.911 1.728 57.883 34.569 ;
     RECT  57.883 1.152 57.983 34.569 ;
     RECT  57.983 1.728 58.055 34.569 ;
     RECT  58.055 2.151 58.963 34.569 ;
     RECT  58.963 2.151 59.135 34.65 ;
     RECT  59.107 0.144 59.459 0.162 ;
     RECT  59.575 35.901 59.827 35.919 ;
     RECT  59.827 35.901 60.251 35.964 ;
     RECT  60.251 35.901 60.539 35.919 ;
     RECT  59.135 2.151 61.267 34.569 ;
     RECT  60.799 0.144 61.547 0.162 ;
     RECT  61.267 2.106 62.023 34.569 ;
     RECT  61.771 35.901 62.159 35.919 ;
     RECT  62.023 1.728 62.627 34.569 ;
     RECT  62.627 1.8 62.915 34.569 ;
     RECT  63.715 35.901 63.887 35.919 ;
     RECT  64.687 0.144 65.219 0.162 ;
     RECT  64.939 35.901 65.291 35.919 ;
     RECT  62.915 2.151 65.659 34.569 ;
     RECT  65.659 2.151 65.911 34.794 ;
     RECT  65.911 1.728 66.047 34.839 ;
     RECT  66.047 1.728 66.299 34.569 ;
     RECT  66.883 0.144 66.983 0.162 ;
     RECT  66.299 2.151 69.12 34.569 ;
    LAYER M3 ;
     RECT  4.374 0.108 4.608 0.139 ;
     RECT  4.626 0.108 4.86 0.139 ;
     RECT  4.878 0.108 5.112 0.139 ;
     RECT  5.13 0.108 5.328 0.139 ;
     RECT  5.346 0.108 5.58 0.139 ;
     RECT  5.598 0.108 5.832 0.139 ;
     RECT  5.85 0.108 6.084 0.139 ;
     RECT  6.102 0.108 6.3 0.139 ;
     RECT  6.318 0.108 6.552 0.139 ;
     RECT  6.57 0.108 6.804 0.139 ;
     RECT  6.822 0.108 7.056 0.139 ;
     RECT  7.074 0.108 7.308 0.139 ;
     RECT  7.326 0.108 7.524 0.139 ;
     RECT  7.542 0.108 7.776 0.139 ;
     RECT  7.794 0.108 8.028 0.139 ;
     RECT  8.046 0.108 8.28 0.139 ;
     RECT  8.298 0.108 8.496 0.139 ;
     RECT  8.514 0.108 8.748 0.139 ;
     RECT  8.766 0.108 9 0.139 ;
     RECT  9.018 0.108 9.252 0.139 ;
     RECT  9.27 0.108 9.468 0.139 ;
     RECT  9.486 0.108 9.72 0.139 ;
     RECT  9.738 0.108 9.972 0.139 ;
     RECT  9.99 0.108 10.224 0.139 ;
     RECT  10.242 0.108 10.44 0.139 ;
     RECT  10.458 0.108 10.692 0.139 ;
     RECT  10.71 0.108 10.944 0.139 ;
     RECT  10.962 0.108 11.196 0.139 ;
     RECT  11.214 0.108 11.412 0.139 ;
     RECT  11.43 0.108 11.664 0.139 ;
     RECT  11.682 0.108 11.916 0.139 ;
     RECT  11.934 0.108 12.168 0.139 ;
     RECT  12.186 0.108 12.384 0.139 ;
     RECT  12.402 0.108 12.636 0.139 ;
     RECT  12.654 0.108 12.888 0.139 ;
     RECT  12.906 0.108 13.14 0.139 ;
     RECT  13.158 0.108 13.356 0.139 ;
     RECT  13.374 0.108 13.608 0.139 ;
     RECT  13.626 0.108 13.86 0.139 ;
     RECT  13.878 0.108 14.112 0.139 ;
     RECT  14.13 0.108 14.328 0.139 ;
     RECT  14.346 0.108 14.58 0.139 ;
     RECT  14.598 0.108 14.832 0.139 ;
     RECT  14.85 0.108 15.084 0.139 ;
     RECT  15.102 0.108 15.336 0.139 ;
     RECT  15.354 0.108 15.552 0.139 ;
     RECT  15.57 0.108 15.804 0.139 ;
     RECT  15.822 0.108 16.056 0.139 ;
     RECT  16.074 0.108 16.308 0.139 ;
     RECT  16.326 0.108 16.524 0.139 ;
     RECT  16.542 0.108 16.776 0.139 ;
     RECT  16.794 0.108 17.028 0.139 ;
     RECT  17.046 0.108 17.28 0.139 ;
     RECT  17.298 0.108 17.496 0.139 ;
     RECT  17.514 0.108 17.748 0.139 ;
     RECT  17.766 0.108 18 0.139 ;
     RECT  18.018 0.108 18.252 0.139 ;
     RECT  18.27 0.108 18.468 0.139 ;
     RECT  18.486 0.108 18.72 0.139 ;
     RECT  18.738 0.108 18.972 0.139 ;
     RECT  18.99 0.108 19.224 0.139 ;
     RECT  19.242 0.108 19.44 0.139 ;
     RECT  19.458 0.108 19.692 0.139 ;
     RECT  19.71 0.108 19.944 0.139 ;
     RECT  19.962 0.108 20.196 0.139 ;
     RECT  20.214 0.108 20.412 0.139 ;
     RECT  20.43 0.108 20.664 0.139 ;
     RECT  20.682 0.108 20.916 0.139 ;
     RECT  20.934 0.108 21.168 0.139 ;
     RECT  21.186 0.108 21.384 0.139 ;
     RECT  21.402 0.108 21.636 0.139 ;
     RECT  21.654 0.108 21.888 0.139 ;
     RECT  21.906 0.108 22.14 0.139 ;
     RECT  22.158 0.108 22.356 0.139 ;
     RECT  22.374 0.108 22.608 0.139 ;
     RECT  22.626 0.108 22.86 0.139 ;
     RECT  22.878 0.108 23.112 0.139 ;
     RECT  23.13 0.108 23.364 0.139 ;
     RECT  23.382 0.108 23.58 0.139 ;
     RECT  23.598 0.108 23.832 0.139 ;
     RECT  23.85 0.108 24.084 0.139 ;
     RECT  24.102 0.108 24.336 0.139 ;
     RECT  24.354 0.108 24.552 0.139 ;
     RECT  24.57 0.108 24.804 0.139 ;
     RECT  24.822 0.108 25.056 0.139 ;
     RECT  25.074 0.108 25.308 0.139 ;
     RECT  25.326 0.108 25.524 0.139 ;
     RECT  25.542 0.108 25.776 0.139 ;
     RECT  25.794 0.108 26.028 0.139 ;
     RECT  26.046 0.108 26.28 0.139 ;
     RECT  26.298 0.108 26.496 0.139 ;
     RECT  26.514 0.108 26.748 0.139 ;
     RECT  26.766 0.108 27 0.139 ;
     RECT  27.018 0.108 27.252 0.139 ;
     RECT  27.27 0.108 27.468 0.139 ;
     RECT  27.486 0.108 27.72 0.139 ;
     RECT  27.738 0.108 27.972 0.139 ;
     RECT  27.99 0.108 28.224 0.139 ;
     RECT  28.242 0.108 28.44 0.139 ;
     RECT  28.458 0.108 28.692 0.139 ;
     RECT  28.71 0.108 28.944 0.139 ;
     RECT  28.962 0.108 29.196 0.139 ;
     RECT  29.214 0.108 29.412 0.139 ;
     RECT  29.43 0.108 29.664 0.139 ;
     RECT  29.682 0.108 29.916 0.139 ;
     RECT  29.934 0.108 30.168 0.139 ;
     RECT  30.186 0.108 30.384 0.139 ;
     RECT  30.402 0.108 30.636 0.139 ;
     RECT  30.654 0.108 30.888 0.139 ;
     RECT  30.906 0.108 31.14 0.139 ;
     RECT  31.158 0.108 31.356 0.139 ;
     RECT  31.374 0.108 31.608 0.139 ;
     RECT  31.626 0.108 31.86 0.139 ;
     RECT  31.878 0.108 32.112 0.139 ;
     RECT  32.13 0.108 32.364 0.139 ;
     RECT  32.382 0.108 32.58 0.139 ;
     RECT  32.598 0.108 32.832 0.139 ;
     RECT  32.85 0.108 33.084 0.139 ;
     RECT  33.102 0.108 33.336 0.139 ;
     RECT  33.354 0.108 33.552 0.139 ;
     RECT  33.57 0.108 33.804 0.139 ;
     RECT  33.822 0.108 34.056 0.139 ;
     RECT  34.074 0.108 34.308 0.139 ;
     RECT  34.326 0.108 34.524 0.139 ;
     RECT  34.542 0.108 34.776 0.139 ;
     RECT  34.794 0.108 35.028 0.139 ;
     RECT  35.046 0.108 35.28 0.139 ;
     RECT  35.298 0.108 35.496 0.139 ;
     RECT  35.514 0.108 35.748 0.139 ;
     RECT  35.766 0.108 36 0.139 ;
     RECT  36.018 0.108 36.252 0.139 ;
     RECT  36.27 0.108 36.468 0.139 ;
     RECT  36.486 0.108 36.72 0.139 ;
     RECT  36.738 0.108 36.972 0.139 ;
     RECT  36.99 0.108 37.224 0.139 ;
     RECT  37.242 0.108 37.44 0.139 ;
     RECT  37.458 0.108 37.692 0.139 ;
     RECT  37.71 0.108 37.944 0.139 ;
     RECT  37.962 0.108 38.196 0.139 ;
     RECT  38.214 0.108 38.412 0.139 ;
     RECT  38.43 0.108 38.664 0.139 ;
     RECT  38.682 0.108 38.916 0.139 ;
     RECT  38.934 0.108 39.168 0.139 ;
     RECT  39.186 0.108 39.384 0.139 ;
     RECT  39.402 0.108 39.636 0.139 ;
     RECT  39.654 0.108 39.888 0.139 ;
     RECT  39.906 0.108 40.14 0.139 ;
     RECT  40.158 0.108 40.392 0.139 ;
     RECT  40.41 0.108 40.608 0.139 ;
     RECT  40.626 0.108 40.86 0.139 ;
     RECT  40.878 0.108 41.112 0.139 ;
     RECT  41.13 0.108 41.364 0.139 ;
     RECT  41.382 0.108 41.58 0.139 ;
     RECT  41.598 0.108 41.832 0.139 ;
     RECT  41.85 0.108 42.084 0.139 ;
     RECT  42.102 0.108 42.336 0.139 ;
     RECT  42.354 0.108 42.552 0.139 ;
     RECT  42.57 0.108 42.804 0.139 ;
     RECT  42.822 0.108 43.056 0.139 ;
     RECT  43.074 0.108 43.308 0.139 ;
     RECT  43.326 0.108 43.524 0.139 ;
     RECT  43.542 0.108 43.776 0.139 ;
     RECT  43.794 0.108 44.028 0.139 ;
     RECT  44.046 0.108 44.28 0.139 ;
     RECT  44.298 0.108 44.496 0.139 ;
     RECT  44.514 0.108 44.748 0.139 ;
     RECT  44.766 0.108 45 0.139 ;
     RECT  45.018 0.108 45.252 0.139 ;
     RECT  45.27 0.108 45.468 0.139 ;
     RECT  45.486 0.108 45.72 0.139 ;
     RECT  45.738 0.108 45.972 0.139 ;
     RECT  45.99 0.108 46.224 0.139 ;
     RECT  46.242 0.108 46.44 0.139 ;
     RECT  46.458 0.108 46.692 0.139 ;
     RECT  46.71 0.108 46.944 0.139 ;
     RECT  46.962 0.108 47.196 0.139 ;
     RECT  47.214 0.108 47.412 0.139 ;
     RECT  47.43 0.108 47.664 0.139 ;
     RECT  47.682 0.108 47.916 0.139 ;
     RECT  47.934 0.108 48.168 0.139 ;
     RECT  48.186 0.108 48.42 0.139 ;
     RECT  48.438 0.108 48.636 0.139 ;
     RECT  48.654 0.108 48.888 0.139 ;
     RECT  48.906 0.108 49.14 0.139 ;
     RECT  49.158 0.108 49.392 0.139 ;
     RECT  49.41 0.108 49.608 0.139 ;
     RECT  49.626 0.108 49.86 0.139 ;
     RECT  49.878 0.108 50.112 0.139 ;
     RECT  50.13 0.108 50.364 0.139 ;
     RECT  50.382 0.108 50.58 0.139 ;
     RECT  50.598 0.108 50.832 0.139 ;
     RECT  50.85 0.108 51.084 0.139 ;
     RECT  51.102 0.108 51.336 0.139 ;
     RECT  51.354 0.108 51.552 0.139 ;
     RECT  51.57 0.108 51.804 0.139 ;
     RECT  51.822 0.108 52.056 0.139 ;
     RECT  52.074 0.108 52.308 0.139 ;
     RECT  52.326 0.108 52.524 0.139 ;
     RECT  52.542 0.108 52.776 0.139 ;
     RECT  52.794 0.108 53.028 0.139 ;
     RECT  53.046 0.108 53.28 0.139 ;
     RECT  53.298 0.108 53.496 0.139 ;
     RECT  53.514 0.108 53.748 0.139 ;
     RECT  53.766 0.108 54 0.139 ;
     RECT  54.018 0.108 54.252 0.139 ;
     RECT  54.27 0.108 54.468 0.139 ;
     RECT  54.486 0.108 54.72 0.139 ;
     RECT  54.738 0.108 54.972 0.139 ;
     RECT  54.99 0.108 55.224 0.139 ;
     RECT  55.242 0.108 55.44 0.139 ;
     RECT  55.458 0.108 55.692 0.139 ;
     RECT  55.71 0.108 55.944 0.139 ;
     RECT  55.962 0.108 56.196 0.139 ;
     RECT  56.214 0.108 56.412 0.139 ;
     RECT  56.43 0.108 56.664 0.139 ;
     RECT  56.682 0.108 56.916 0.139 ;
     RECT  56.934 0.108 57.168 0.139 ;
     RECT  57.186 0.108 57.42 0.139 ;
     RECT  57.438 0.108 57.636 0.139 ;
     RECT  57.654 0.108 57.888 0.139 ;
     RECT  57.906 0.108 58.14 0.139 ;
     RECT  58.158 0.108 58.392 0.139 ;
     RECT  58.41 0.108 58.608 0.139 ;
     RECT  58.626 0.108 58.86 0.139 ;
     RECT  58.878 0.108 59.112 0.139 ;
     RECT  59.13 0.108 59.364 0.139 ;
     RECT  59.382 0.108 59.58 0.139 ;
     RECT  59.598 0.108 59.832 0.139 ;
     RECT  59.85 0.108 60.084 0.139 ;
     RECT  60.102 0.108 60.336 0.139 ;
     RECT  60.354 0.108 60.552 0.139 ;
     RECT  60.57 0.108 60.804 0.139 ;
     RECT  60.822 0.108 61.056 0.139 ;
     RECT  61.074 0.108 61.308 0.139 ;
     RECT  61.326 0.108 61.524 0.139 ;
     RECT  61.542 0.108 61.776 0.139 ;
     RECT  61.794 0.108 62.028 0.139 ;
     RECT  62.046 0.108 62.28 0.139 ;
     RECT  62.298 0.108 62.496 0.139 ;
     RECT  62.514 0.108 62.748 0.139 ;
     RECT  62.766 0.108 63 0.139 ;
     RECT  63.018 0.108 63.252 0.139 ;
     RECT  63.27 0.108 63.468 0.139 ;
     RECT  63.486 0.108 63.72 0.139 ;
     RECT  63.738 0.108 63.972 0.139 ;
     RECT  63.99 0.108 64.224 0.139 ;
     RECT  64.242 0.108 64.44 0.139 ;
     RECT  64.458 0.108 64.692 0.139 ;
     RECT  64.71 0.108 64.944 0.139 ;
     RECT  64.962 0.108 65.196 0.139 ;
     RECT  65.214 0.108 65.448 0.139 ;
     RECT  65.466 0.108 65.664 0.139 ;
     RECT  65.682 0.108 65.916 0.139 ;
     RECT  65.934 0.108 66.168 0.139 ;
     RECT  66.186 0.108 66.42 0.139 ;
     RECT  66.438 0.108 66.636 0.139 ;
     RECT  66.654 0.108 66.888 0.139 ;
     RECT  4.374 0.139 4.608 0.144 ;
     RECT  4.626 0.139 4.86 0.144 ;
     RECT  4.878 0.139 5.112 0.144 ;
     RECT  5.13 0.139 5.328 0.144 ;
     RECT  5.346 0.139 5.58 0.144 ;
     RECT  5.598 0.139 5.832 0.144 ;
     RECT  5.85 0.139 6.084 0.144 ;
     RECT  6.102 0.139 6.3 0.144 ;
     RECT  6.318 0.139 6.552 0.144 ;
     RECT  6.57 0.139 6.804 0.144 ;
     RECT  6.822 0.139 7.056 0.144 ;
     RECT  7.074 0.139 7.308 0.144 ;
     RECT  7.326 0.139 7.524 0.144 ;
     RECT  7.542 0.139 7.776 0.144 ;
     RECT  7.794 0.139 8.028 0.144 ;
     RECT  8.046 0.139 8.28 0.144 ;
     RECT  8.298 0.139 8.496 0.144 ;
     RECT  8.514 0.139 8.748 0.144 ;
     RECT  8.766 0.139 9 0.144 ;
     RECT  9.018 0.139 9.252 0.144 ;
     RECT  9.27 0.139 9.468 0.144 ;
     RECT  9.486 0.139 9.72 0.144 ;
     RECT  9.738 0.139 9.972 0.144 ;
     RECT  9.99 0.139 10.224 0.144 ;
     RECT  10.242 0.139 10.44 0.144 ;
     RECT  10.458 0.139 10.692 0.144 ;
     RECT  10.71 0.139 10.944 0.144 ;
     RECT  10.962 0.139 11.196 0.144 ;
     RECT  11.214 0.139 11.412 0.144 ;
     RECT  11.43 0.139 11.664 0.144 ;
     RECT  11.682 0.139 11.916 0.144 ;
     RECT  11.934 0.139 12.168 0.144 ;
     RECT  12.186 0.139 12.384 0.144 ;
     RECT  12.402 0.139 12.636 0.144 ;
     RECT  12.654 0.139 12.888 0.144 ;
     RECT  12.906 0.139 13.14 0.144 ;
     RECT  13.158 0.139 13.356 0.144 ;
     RECT  13.374 0.139 13.608 0.144 ;
     RECT  13.626 0.139 13.86 0.144 ;
     RECT  13.878 0.139 14.112 0.144 ;
     RECT  14.13 0.139 14.328 0.144 ;
     RECT  14.346 0.139 14.58 0.144 ;
     RECT  14.598 0.139 14.832 0.144 ;
     RECT  14.85 0.139 15.084 0.144 ;
     RECT  15.102 0.139 15.336 0.144 ;
     RECT  15.354 0.139 15.552 0.144 ;
     RECT  15.57 0.139 15.804 0.144 ;
     RECT  15.822 0.139 16.056 0.144 ;
     RECT  16.074 0.139 16.308 0.144 ;
     RECT  16.326 0.139 16.524 0.144 ;
     RECT  16.542 0.139 16.776 0.144 ;
     RECT  16.794 0.139 17.028 0.144 ;
     RECT  17.046 0.139 17.28 0.144 ;
     RECT  17.298 0.139 17.496 0.144 ;
     RECT  17.514 0.139 17.748 0.144 ;
     RECT  17.766 0.139 18 0.144 ;
     RECT  18.018 0.139 18.252 0.144 ;
     RECT  18.27 0.139 18.468 0.144 ;
     RECT  18.486 0.139 18.72 0.144 ;
     RECT  18.738 0.139 18.972 0.144 ;
     RECT  18.99 0.139 19.224 0.144 ;
     RECT  19.242 0.139 19.44 0.144 ;
     RECT  19.458 0.139 19.692 0.144 ;
     RECT  19.71 0.139 19.944 0.144 ;
     RECT  19.962 0.139 20.196 0.144 ;
     RECT  20.214 0.139 20.412 0.144 ;
     RECT  20.43 0.139 20.664 0.144 ;
     RECT  20.682 0.139 20.916 0.144 ;
     RECT  20.934 0.139 21.168 0.144 ;
     RECT  21.186 0.139 21.384 0.144 ;
     RECT  21.402 0.139 21.636 0.144 ;
     RECT  21.654 0.139 21.888 0.144 ;
     RECT  21.906 0.139 22.14 0.144 ;
     RECT  22.158 0.139 22.356 0.144 ;
     RECT  22.374 0.139 22.608 0.144 ;
     RECT  22.626 0.139 22.86 0.144 ;
     RECT  22.878 0.139 23.112 0.144 ;
     RECT  23.13 0.139 23.364 0.144 ;
     RECT  23.382 0.139 23.58 0.144 ;
     RECT  23.598 0.139 23.832 0.144 ;
     RECT  23.85 0.139 24.084 0.144 ;
     RECT  24.102 0.139 24.336 0.144 ;
     RECT  24.354 0.139 24.552 0.144 ;
     RECT  24.57 0.139 24.804 0.144 ;
     RECT  24.822 0.139 25.056 0.144 ;
     RECT  25.074 0.139 25.308 0.144 ;
     RECT  25.326 0.139 25.524 0.144 ;
     RECT  25.542 0.139 25.776 0.144 ;
     RECT  25.794 0.139 26.028 0.144 ;
     RECT  26.046 0.139 26.28 0.144 ;
     RECT  26.298 0.139 26.496 0.144 ;
     RECT  26.514 0.139 26.748 0.144 ;
     RECT  26.766 0.139 27 0.144 ;
     RECT  27.018 0.139 27.252 0.144 ;
     RECT  27.27 0.139 27.468 0.144 ;
     RECT  27.486 0.139 27.72 0.144 ;
     RECT  27.738 0.139 27.972 0.144 ;
     RECT  27.99 0.139 28.224 0.144 ;
     RECT  28.242 0.139 28.44 0.144 ;
     RECT  28.458 0.139 28.692 0.144 ;
     RECT  28.71 0.139 28.944 0.144 ;
     RECT  28.962 0.139 29.196 0.144 ;
     RECT  29.214 0.139 29.412 0.144 ;
     RECT  29.43 0.139 29.664 0.144 ;
     RECT  29.682 0.139 29.916 0.144 ;
     RECT  29.934 0.139 30.168 0.144 ;
     RECT  30.186 0.139 30.384 0.144 ;
     RECT  30.402 0.139 30.636 0.144 ;
     RECT  30.654 0.139 30.888 0.144 ;
     RECT  30.906 0.139 31.14 0.144 ;
     RECT  31.158 0.139 31.356 0.144 ;
     RECT  31.374 0.139 31.608 0.144 ;
     RECT  31.626 0.139 31.86 0.144 ;
     RECT  31.878 0.139 32.112 0.144 ;
     RECT  32.13 0.139 32.364 0.144 ;
     RECT  32.382 0.139 32.58 0.144 ;
     RECT  32.598 0.139 32.832 0.144 ;
     RECT  32.85 0.139 33.084 0.144 ;
     RECT  33.102 0.139 33.336 0.144 ;
     RECT  33.354 0.139 33.552 0.144 ;
     RECT  33.57 0.139 33.804 0.144 ;
     RECT  33.822 0.139 34.056 0.144 ;
     RECT  34.074 0.139 34.308 0.144 ;
     RECT  34.326 0.139 34.524 0.144 ;
     RECT  34.542 0.139 34.776 0.144 ;
     RECT  34.794 0.139 35.028 0.144 ;
     RECT  35.046 0.139 35.28 0.144 ;
     RECT  35.298 0.139 35.496 0.144 ;
     RECT  35.514 0.139 35.748 0.144 ;
     RECT  35.766 0.139 36 0.144 ;
     RECT  36.018 0.139 36.252 0.144 ;
     RECT  36.27 0.139 36.468 0.144 ;
     RECT  36.486 0.139 36.72 0.144 ;
     RECT  36.738 0.139 36.972 0.144 ;
     RECT  36.99 0.139 37.224 0.144 ;
     RECT  37.242 0.139 37.44 0.144 ;
     RECT  37.458 0.139 37.692 0.144 ;
     RECT  37.71 0.139 37.944 0.144 ;
     RECT  37.962 0.139 38.196 0.144 ;
     RECT  38.214 0.139 38.412 0.144 ;
     RECT  38.43 0.139 38.664 0.144 ;
     RECT  38.682 0.139 38.916 0.144 ;
     RECT  38.934 0.139 39.168 0.144 ;
     RECT  39.186 0.139 39.384 0.144 ;
     RECT  39.402 0.139 39.636 0.144 ;
     RECT  39.654 0.139 39.888 0.144 ;
     RECT  39.906 0.139 40.14 0.144 ;
     RECT  40.158 0.139 40.392 0.144 ;
     RECT  40.41 0.139 40.608 0.144 ;
     RECT  40.626 0.139 40.86 0.144 ;
     RECT  40.878 0.139 41.112 0.144 ;
     RECT  41.13 0.139 41.364 0.144 ;
     RECT  41.382 0.139 41.58 0.144 ;
     RECT  41.598 0.139 41.832 0.144 ;
     RECT  41.85 0.139 42.084 0.144 ;
     RECT  42.102 0.139 42.336 0.144 ;
     RECT  42.354 0.139 42.552 0.144 ;
     RECT  42.57 0.139 42.804 0.144 ;
     RECT  42.822 0.139 43.056 0.144 ;
     RECT  43.074 0.139 43.308 0.144 ;
     RECT  43.326 0.139 43.524 0.144 ;
     RECT  43.542 0.139 43.776 0.144 ;
     RECT  43.794 0.139 44.028 0.144 ;
     RECT  44.046 0.139 44.28 0.144 ;
     RECT  44.298 0.139 44.496 0.144 ;
     RECT  44.514 0.139 44.748 0.144 ;
     RECT  44.766 0.139 45 0.144 ;
     RECT  45.018 0.139 45.252 0.144 ;
     RECT  45.27 0.139 45.468 0.144 ;
     RECT  45.486 0.139 45.72 0.144 ;
     RECT  45.738 0.139 45.972 0.144 ;
     RECT  45.99 0.139 46.224 0.144 ;
     RECT  46.242 0.139 46.44 0.144 ;
     RECT  46.458 0.139 46.692 0.144 ;
     RECT  46.71 0.139 46.944 0.144 ;
     RECT  46.962 0.139 47.196 0.144 ;
     RECT  47.214 0.139 47.412 0.144 ;
     RECT  47.43 0.139 47.664 0.144 ;
     RECT  47.682 0.139 47.916 0.144 ;
     RECT  47.934 0.139 48.168 0.144 ;
     RECT  48.186 0.139 48.42 0.144 ;
     RECT  48.438 0.139 48.636 0.144 ;
     RECT  48.654 0.139 48.888 0.144 ;
     RECT  48.906 0.139 49.14 0.144 ;
     RECT  49.158 0.139 49.392 0.144 ;
     RECT  49.41 0.139 49.608 0.144 ;
     RECT  49.626 0.139 49.86 0.144 ;
     RECT  49.878 0.139 50.112 0.144 ;
     RECT  50.13 0.139 50.364 0.144 ;
     RECT  50.382 0.139 50.58 0.144 ;
     RECT  50.598 0.139 50.832 0.144 ;
     RECT  50.85 0.139 51.084 0.144 ;
     RECT  51.102 0.139 51.336 0.144 ;
     RECT  51.354 0.139 51.552 0.144 ;
     RECT  51.57 0.139 51.804 0.144 ;
     RECT  51.822 0.139 52.056 0.144 ;
     RECT  52.074 0.139 52.308 0.144 ;
     RECT  52.326 0.139 52.524 0.144 ;
     RECT  52.542 0.139 52.776 0.144 ;
     RECT  52.794 0.139 53.028 0.144 ;
     RECT  53.046 0.139 53.28 0.144 ;
     RECT  53.298 0.139 53.496 0.144 ;
     RECT  53.514 0.139 53.748 0.144 ;
     RECT  53.766 0.139 54 0.144 ;
     RECT  54.018 0.139 54.252 0.144 ;
     RECT  54.27 0.139 54.468 0.144 ;
     RECT  54.486 0.139 54.72 0.144 ;
     RECT  54.738 0.139 54.972 0.144 ;
     RECT  54.99 0.139 55.224 0.144 ;
     RECT  55.242 0.139 55.44 0.144 ;
     RECT  55.458 0.139 55.692 0.144 ;
     RECT  55.71 0.139 55.944 0.144 ;
     RECT  55.962 0.139 56.196 0.144 ;
     RECT  56.214 0.139 56.412 0.144 ;
     RECT  56.43 0.139 56.664 0.144 ;
     RECT  56.682 0.139 56.916 0.144 ;
     RECT  56.934 0.139 57.168 0.144 ;
     RECT  57.186 0.139 57.42 0.144 ;
     RECT  57.438 0.139 57.636 0.144 ;
     RECT  57.654 0.139 57.888 0.144 ;
     RECT  57.906 0.139 58.14 0.144 ;
     RECT  58.158 0.139 58.392 0.144 ;
     RECT  58.41 0.139 58.608 0.144 ;
     RECT  58.626 0.139 58.86 0.144 ;
     RECT  58.878 0.139 59.112 0.144 ;
     RECT  59.13 0.139 59.364 0.144 ;
     RECT  59.382 0.139 59.58 0.144 ;
     RECT  59.598 0.139 59.832 0.144 ;
     RECT  59.85 0.139 60.084 0.144 ;
     RECT  60.102 0.139 60.336 0.144 ;
     RECT  60.354 0.139 60.552 0.144 ;
     RECT  60.57 0.139 60.804 0.144 ;
     RECT  60.822 0.139 61.056 0.144 ;
     RECT  61.074 0.139 61.308 0.144 ;
     RECT  61.326 0.139 61.524 0.144 ;
     RECT  61.542 0.139 61.776 0.144 ;
     RECT  61.794 0.139 62.028 0.144 ;
     RECT  62.046 0.139 62.28 0.144 ;
     RECT  62.298 0.139 62.496 0.144 ;
     RECT  62.514 0.139 62.748 0.144 ;
     RECT  62.766 0.139 63 0.144 ;
     RECT  63.018 0.139 63.252 0.144 ;
     RECT  63.27 0.139 63.468 0.144 ;
     RECT  63.486 0.139 63.72 0.144 ;
     RECT  63.738 0.139 63.972 0.144 ;
     RECT  63.99 0.139 64.224 0.144 ;
     RECT  64.242 0.139 64.44 0.144 ;
     RECT  64.458 0.139 64.692 0.144 ;
     RECT  64.71 0.139 64.944 0.144 ;
     RECT  64.962 0.139 65.196 0.144 ;
     RECT  65.214 0.139 65.448 0.144 ;
     RECT  65.466 0.139 65.664 0.144 ;
     RECT  65.682 0.139 65.916 0.144 ;
     RECT  65.934 0.139 66.168 0.144 ;
     RECT  66.186 0.139 66.42 0.144 ;
     RECT  66.438 0.139 66.636 0.144 ;
     RECT  66.654 0.139 66.888 0.144 ;
     RECT  66.906 0.139 66.978 0.144 ;
     RECT  4.356 0.144 66.978 0.173 ;
     RECT  4.356 0.173 51.57 0.557 ;
     RECT  4.356 0.557 46.458 1.723 ;
     RECT  47.196 0.557 51.57 1.723 ;
     RECT  52.524 0.173 52.542 1.723 ;
     RECT  53.352 0.173 66.978 1.723 ;
     RECT  4.356 1.723 51.606 1.771 ;
     RECT  52.452 1.723 52.542 1.771 ;
     RECT  4.356 1.771 52.542 2.101 ;
     RECT  53.28 1.723 66.978 2.143 ;
     RECT  4.14 2.101 52.542 2.191 ;
     RECT  53.28 2.143 67.305 2.191 ;
     RECT  4.14 2.191 67.698 2.251 ;
     RECT  4.14 2.251 68.022 2.371 ;
     RECT  2.415 2.143 2.505 2.413 ;
     RECT  4.068 2.371 68.022 2.641 ;
     RECT  4.032 2.641 68.202 2.767 ;
     RECT  4.032 2.767 68.598 2.911 ;
     RECT  4.032 2.911 68.706 3.307 ;
     RECT  3.96 3.307 68.706 3.847 ;
     RECT  3.96 3.847 68.994 4.013 ;
     RECT  4.608 4.013 68.994 4.261 ;
     RECT  4.608 4.261 69.03 10.085 ;
     RECT  4.716 10.085 69.03 11.237 ;
     RECT  4.716 11.237 68.778 16.799 ;
     RECT  4.932 16.799 68.778 17.141 ;
     RECT  4.932 17.141 68.562 17.339 ;
     RECT  52.236 17.339 68.562 17.519 ;
     RECT  52.236 17.519 68.49 17.609 ;
     RECT  4.968 17.339 51.498 18.805 ;
     RECT  52.272 17.609 68.49 18.805 ;
     RECT  4.14 16.951 4.158 19.805 ;
     RECT  4.968 18.805 68.49 19.921 ;
     RECT  4.248 19.921 68.49 20.075 ;
     RECT  4.248 20.075 67.986 20.147 ;
     RECT  4.248 20.147 67.95 22.081 ;
     RECT  3.744 22.081 67.95 22.109 ;
     RECT  3.744 22.109 3.978 22.235 ;
     RECT  4.788 22.109 67.95 22.235 ;
     RECT  4.896 22.235 67.95 22.613 ;
     RECT  4.896 22.613 67.77 22.775 ;
     RECT  3.96 22.235 3.978 29.525 ;
     RECT  4.896 22.775 67.554 29.605 ;
     RECT  4.248 29.605 67.554 29.795 ;
     RECT  2.415 2.413 2.697 34.307 ;
     RECT  4.248 29.795 67.497 34.307 ;
     RECT  2.415 34.307 2.505 34.577 ;
     RECT  4.248 34.307 67.305 34.577 ;
     RECT  4.248 34.577 66.906 34.733 ;
     RECT  4.248 34.733 56.43 34.799 ;
     RECT  4.356 34.799 56.43 35.896 ;
     RECT  57.168 34.733 66.906 35.896 ;
     RECT  4.356 35.896 66.906 36.576 ;
     RECT  4.374 36.576 4.608 36.588 ;
     RECT  4.626 36.576 4.86 36.588 ;
     RECT  4.878 36.576 5.112 36.588 ;
     RECT  5.13 36.576 5.328 36.588 ;
     RECT  5.346 36.576 5.58 36.588 ;
     RECT  5.598 36.576 5.832 36.588 ;
     RECT  5.85 36.576 6.084 36.588 ;
     RECT  6.102 36.576 6.3 36.588 ;
     RECT  6.318 36.576 6.552 36.588 ;
     RECT  6.57 36.576 6.804 36.588 ;
     RECT  6.822 36.576 7.056 36.588 ;
     RECT  7.074 36.576 7.308 36.588 ;
     RECT  7.326 36.576 7.524 36.588 ;
     RECT  7.542 36.576 7.776 36.588 ;
     RECT  7.794 36.576 8.028 36.588 ;
     RECT  8.046 36.576 8.28 36.588 ;
     RECT  8.298 36.576 8.496 36.588 ;
     RECT  8.514 36.576 8.748 36.588 ;
     RECT  8.766 36.576 9 36.588 ;
     RECT  9.018 36.576 9.252 36.588 ;
     RECT  9.27 36.576 9.468 36.588 ;
     RECT  9.486 36.576 9.72 36.588 ;
     RECT  9.738 36.576 9.972 36.588 ;
     RECT  9.99 36.576 10.224 36.588 ;
     RECT  10.242 36.576 10.44 36.588 ;
     RECT  10.458 36.576 10.692 36.588 ;
     RECT  10.71 36.576 10.944 36.588 ;
     RECT  10.962 36.576 11.196 36.588 ;
     RECT  11.214 36.576 11.412 36.588 ;
     RECT  11.43 36.576 11.664 36.588 ;
     RECT  11.682 36.576 11.916 36.588 ;
     RECT  11.934 36.576 12.168 36.588 ;
     RECT  12.186 36.576 12.384 36.588 ;
     RECT  12.402 36.576 12.636 36.588 ;
     RECT  12.654 36.576 12.888 36.588 ;
     RECT  12.906 36.576 13.14 36.588 ;
     RECT  13.158 36.576 13.356 36.588 ;
     RECT  13.374 36.576 13.608 36.588 ;
     RECT  13.626 36.576 13.86 36.588 ;
     RECT  13.878 36.576 14.112 36.588 ;
     RECT  14.13 36.576 14.328 36.588 ;
     RECT  14.346 36.576 14.58 36.588 ;
     RECT  14.598 36.576 14.832 36.588 ;
     RECT  14.85 36.576 15.084 36.588 ;
     RECT  15.102 36.576 15.336 36.588 ;
     RECT  15.354 36.576 15.552 36.588 ;
     RECT  15.57 36.576 15.804 36.588 ;
     RECT  15.822 36.576 16.056 36.588 ;
     RECT  16.074 36.576 16.308 36.588 ;
     RECT  16.326 36.576 16.524 36.588 ;
     RECT  16.542 36.576 16.776 36.588 ;
     RECT  16.794 36.576 17.028 36.588 ;
     RECT  17.046 36.576 17.28 36.588 ;
     RECT  17.298 36.576 17.496 36.588 ;
     RECT  17.514 36.576 17.748 36.588 ;
     RECT  17.766 36.576 18 36.588 ;
     RECT  18.018 36.576 18.252 36.588 ;
     RECT  18.27 36.576 18.468 36.588 ;
     RECT  18.486 36.576 18.72 36.588 ;
     RECT  18.738 36.576 18.972 36.588 ;
     RECT  18.99 36.576 19.224 36.588 ;
     RECT  19.242 36.576 19.44 36.588 ;
     RECT  19.458 36.576 19.692 36.588 ;
     RECT  19.71 36.576 19.944 36.588 ;
     RECT  19.962 36.576 20.196 36.588 ;
     RECT  20.214 36.576 20.412 36.588 ;
     RECT  20.43 36.576 20.664 36.588 ;
     RECT  20.682 36.576 20.916 36.588 ;
     RECT  20.934 36.576 21.168 36.588 ;
     RECT  21.186 36.576 21.384 36.588 ;
     RECT  21.402 36.576 21.636 36.588 ;
     RECT  21.654 36.576 21.888 36.588 ;
     RECT  21.906 36.576 22.14 36.588 ;
     RECT  22.158 36.576 22.356 36.588 ;
     RECT  22.374 36.576 22.608 36.588 ;
     RECT  22.626 36.576 22.86 36.588 ;
     RECT  22.878 36.576 23.112 36.588 ;
     RECT  23.13 36.576 23.364 36.588 ;
     RECT  23.382 36.576 23.58 36.588 ;
     RECT  23.598 36.576 23.832 36.588 ;
     RECT  23.85 36.576 24.084 36.588 ;
     RECT  24.102 36.576 24.336 36.588 ;
     RECT  24.354 36.576 24.552 36.588 ;
     RECT  24.57 36.576 24.804 36.588 ;
     RECT  24.822 36.576 25.056 36.588 ;
     RECT  25.074 36.576 25.308 36.588 ;
     RECT  25.326 36.576 25.524 36.588 ;
     RECT  25.542 36.576 25.776 36.588 ;
     RECT  25.794 36.576 26.028 36.588 ;
     RECT  26.046 36.576 26.28 36.588 ;
     RECT  26.298 36.576 26.496 36.588 ;
     RECT  26.514 36.576 26.748 36.588 ;
     RECT  26.766 36.576 27 36.588 ;
     RECT  27.018 36.576 27.252 36.588 ;
     RECT  27.27 36.576 27.468 36.588 ;
     RECT  27.486 36.576 27.72 36.588 ;
     RECT  27.738 36.576 27.972 36.588 ;
     RECT  27.99 36.576 28.224 36.588 ;
     RECT  28.242 36.576 28.44 36.588 ;
     RECT  28.458 36.576 28.692 36.588 ;
     RECT  28.71 36.576 28.944 36.588 ;
     RECT  28.962 36.576 29.196 36.588 ;
     RECT  29.214 36.576 29.412 36.588 ;
     RECT  29.43 36.576 29.664 36.588 ;
     RECT  29.682 36.576 29.916 36.588 ;
     RECT  29.934 36.576 30.168 36.588 ;
     RECT  30.186 36.576 30.384 36.588 ;
     RECT  30.402 36.576 30.636 36.588 ;
     RECT  30.654 36.576 30.888 36.588 ;
     RECT  30.906 36.576 31.14 36.588 ;
     RECT  31.158 36.576 31.356 36.588 ;
     RECT  31.374 36.576 31.608 36.588 ;
     RECT  31.626 36.576 31.86 36.588 ;
     RECT  31.878 36.576 32.112 36.588 ;
     RECT  32.13 36.576 32.364 36.588 ;
     RECT  32.382 36.576 32.58 36.588 ;
     RECT  32.598 36.576 32.832 36.588 ;
     RECT  32.85 36.576 33.084 36.588 ;
     RECT  33.102 36.576 33.336 36.588 ;
     RECT  33.354 36.576 33.552 36.588 ;
     RECT  33.57 36.576 33.804 36.588 ;
     RECT  33.822 36.576 34.056 36.588 ;
     RECT  34.074 36.576 34.308 36.588 ;
     RECT  34.326 36.576 34.524 36.588 ;
     RECT  34.542 36.576 34.776 36.588 ;
     RECT  34.794 36.576 35.028 36.588 ;
     RECT  35.046 36.576 35.28 36.588 ;
     RECT  35.298 36.576 35.496 36.588 ;
     RECT  35.514 36.576 35.748 36.588 ;
     RECT  35.766 36.576 36 36.588 ;
     RECT  36.018 36.576 36.252 36.588 ;
     RECT  36.27 36.576 36.468 36.588 ;
     RECT  36.486 36.576 36.72 36.588 ;
     RECT  36.738 36.576 36.972 36.588 ;
     RECT  36.99 36.576 37.224 36.588 ;
     RECT  37.242 36.576 37.44 36.588 ;
     RECT  37.458 36.576 37.692 36.588 ;
     RECT  37.71 36.576 37.944 36.588 ;
     RECT  37.962 36.576 38.196 36.588 ;
     RECT  38.214 36.576 38.412 36.588 ;
     RECT  38.43 36.576 38.664 36.588 ;
     RECT  38.682 36.576 38.916 36.588 ;
     RECT  38.934 36.576 39.168 36.588 ;
     RECT  39.186 36.576 39.384 36.588 ;
     RECT  39.402 36.576 39.636 36.588 ;
     RECT  39.654 36.576 39.888 36.588 ;
     RECT  39.906 36.576 40.14 36.588 ;
     RECT  40.158 36.576 40.392 36.588 ;
     RECT  40.41 36.576 40.608 36.588 ;
     RECT  40.626 36.576 40.86 36.588 ;
     RECT  40.878 36.576 41.112 36.588 ;
     RECT  41.13 36.576 41.364 36.588 ;
     RECT  41.382 36.576 41.58 36.588 ;
     RECT  41.598 36.576 41.832 36.588 ;
     RECT  41.85 36.576 42.084 36.588 ;
     RECT  42.102 36.576 42.336 36.588 ;
     RECT  42.354 36.576 42.552 36.588 ;
     RECT  42.57 36.576 42.804 36.588 ;
     RECT  42.822 36.576 43.056 36.588 ;
     RECT  43.074 36.576 43.308 36.588 ;
     RECT  43.326 36.576 43.524 36.588 ;
     RECT  43.542 36.576 43.776 36.588 ;
     RECT  43.794 36.576 44.028 36.588 ;
     RECT  44.046 36.576 44.28 36.588 ;
     RECT  44.298 36.576 44.496 36.588 ;
     RECT  44.514 36.576 44.748 36.588 ;
     RECT  44.766 36.576 45 36.588 ;
     RECT  45.018 36.576 45.252 36.588 ;
     RECT  45.27 36.576 45.468 36.588 ;
     RECT  45.486 36.576 45.72 36.588 ;
     RECT  45.738 36.576 45.972 36.588 ;
     RECT  45.99 36.576 46.224 36.588 ;
     RECT  46.242 36.576 46.44 36.588 ;
     RECT  46.458 36.576 46.692 36.588 ;
     RECT  46.71 36.576 46.944 36.588 ;
     RECT  46.962 36.576 47.196 36.588 ;
     RECT  47.214 36.576 47.412 36.588 ;
     RECT  47.43 36.576 47.664 36.588 ;
     RECT  47.682 36.576 47.916 36.588 ;
     RECT  47.934 36.576 48.168 36.588 ;
     RECT  48.186 36.576 48.42 36.588 ;
     RECT  48.438 36.576 48.636 36.588 ;
     RECT  48.654 36.576 48.888 36.588 ;
     RECT  48.906 36.576 49.14 36.588 ;
     RECT  49.158 36.576 49.392 36.588 ;
     RECT  49.41 36.576 49.608 36.588 ;
     RECT  49.626 36.576 49.86 36.588 ;
     RECT  49.878 36.576 50.112 36.588 ;
     RECT  50.13 36.576 50.364 36.588 ;
     RECT  50.382 36.576 50.58 36.588 ;
     RECT  50.598 36.576 50.832 36.588 ;
     RECT  50.85 36.576 51.084 36.588 ;
     RECT  51.102 36.576 51.336 36.588 ;
     RECT  51.354 36.576 51.552 36.588 ;
     RECT  51.57 36.576 51.804 36.588 ;
     RECT  51.822 36.576 52.056 36.588 ;
     RECT  52.074 36.576 52.308 36.588 ;
     RECT  52.326 36.576 52.524 36.588 ;
     RECT  52.542 36.576 52.776 36.588 ;
     RECT  52.794 36.576 53.028 36.588 ;
     RECT  53.046 36.576 53.28 36.588 ;
     RECT  53.298 36.576 53.496 36.588 ;
     RECT  53.514 36.576 53.748 36.588 ;
     RECT  53.766 36.576 54 36.588 ;
     RECT  54.018 36.576 54.252 36.588 ;
     RECT  54.27 36.576 54.468 36.588 ;
     RECT  54.486 36.576 54.72 36.588 ;
     RECT  54.738 36.576 54.972 36.588 ;
     RECT  54.99 36.576 55.224 36.588 ;
     RECT  55.242 36.576 55.44 36.588 ;
     RECT  55.458 36.576 55.692 36.588 ;
     RECT  55.71 36.576 55.944 36.588 ;
     RECT  55.962 36.576 56.196 36.588 ;
     RECT  56.214 36.576 56.412 36.588 ;
     RECT  56.43 36.576 56.664 36.588 ;
     RECT  56.682 36.576 56.916 36.588 ;
     RECT  56.934 36.576 57.168 36.588 ;
     RECT  57.186 36.576 57.42 36.588 ;
     RECT  57.438 36.576 57.636 36.588 ;
     RECT  57.654 36.576 57.888 36.588 ;
     RECT  57.906 36.576 58.14 36.588 ;
     RECT  58.158 36.576 58.392 36.588 ;
     RECT  58.41 36.576 58.608 36.588 ;
     RECT  58.626 36.576 58.86 36.588 ;
     RECT  58.878 36.576 59.112 36.588 ;
     RECT  59.13 36.576 59.364 36.588 ;
     RECT  59.382 36.576 59.58 36.588 ;
     RECT  59.598 36.576 59.832 36.588 ;
     RECT  59.85 36.576 60.084 36.588 ;
     RECT  60.102 36.576 60.336 36.588 ;
     RECT  60.354 36.576 60.552 36.588 ;
     RECT  60.57 36.576 60.804 36.588 ;
     RECT  60.822 36.576 61.056 36.588 ;
     RECT  61.074 36.576 61.308 36.588 ;
     RECT  61.326 36.576 61.524 36.588 ;
     RECT  61.542 36.576 61.776 36.588 ;
     RECT  61.794 36.576 62.028 36.588 ;
     RECT  62.046 36.576 62.28 36.588 ;
     RECT  62.298 36.576 62.496 36.588 ;
     RECT  62.514 36.576 62.748 36.588 ;
     RECT  62.766 36.576 63 36.588 ;
     RECT  63.018 36.576 63.252 36.588 ;
     RECT  63.27 36.576 63.468 36.588 ;
     RECT  63.486 36.576 63.72 36.588 ;
     RECT  63.738 36.576 63.972 36.588 ;
     RECT  63.99 36.576 64.224 36.588 ;
     RECT  64.242 36.576 64.44 36.588 ;
     RECT  64.458 36.576 64.692 36.588 ;
     RECT  64.71 36.576 64.944 36.588 ;
     RECT  64.962 36.576 65.196 36.588 ;
     RECT  65.214 36.576 65.448 36.588 ;
     RECT  65.466 36.576 65.664 36.588 ;
     RECT  65.682 36.576 65.916 36.588 ;
     RECT  65.934 36.576 66.168 36.588 ;
     RECT  66.186 36.576 66.42 36.588 ;
     RECT  66.438 36.576 66.636 36.588 ;
     RECT  66.654 36.576 66.888 36.588 ;
     RECT  37.26 36.588 37.35 36.653 ;
    LAYER M4 ;
     RECT  0.229 6.816 2.408 6.84 ;
     RECT  2.408 2.148 2.512 34.572 ;
     RECT  2.512 2.418 2.704 34.302 ;
     RECT  4.481 34.752 4.565 34.776 ;
     RECT  3.949 3.984 4.705 4.008 ;
     RECT  4.741 29.376 4.981 29.4 ;
     RECT  4.481 1.728 5.108 1.752 ;
     RECT  4.705 3.984 5.108 5.112 ;
     RECT  2.704 6.816 5.108 6.84 ;
     RECT  4.981 29.376 5.108 29.64 ;
     RECT  5.108 1.728 5.404 34.728 ;
     RECT  5.404 1.728 5.545 1.8 ;
     RECT  5.545 1.728 5.669 1.752 ;
     RECT  5.404 34.224 5.717 34.728 ;
     RECT  5.669 1.152 5.753 1.752 ;
     RECT  5.404 4.224 5.861 6.84 ;
     RECT  5.461 35.904 5.933 35.928 ;
     RECT  5.717 34.224 6.227 34.392 ;
     RECT  5.861 4.56 6.901 6.84 ;
     RECT  5.404 2.88 7.369 2.904 ;
     RECT  6.901 3.936 7.369 6.84 ;
     RECT  6.227 34.224 7.621 34.344 ;
     RECT  7.621 34.224 7.669 34.392 ;
     RECT  5.753 1.728 7.808 1.752 ;
     RECT  7.369 2.88 7.808 6.84 ;
     RECT  6.421 29.04 7.808 29.064 ;
     RECT  7.669 34.224 7.808 34.728 ;
     RECT  7.808 1.728 7.955 34.728 ;
     RECT  7.955 1.728 8.104 34.68 ;
     RECT  8.149 0.192 8.291 0.216 ;
     RECT  8.104 33.648 8.291 34.68 ;
     RECT  8.104 2.88 8.345 3.624 ;
     RECT  8.104 29.04 8.381 29.064 ;
     RECT  8.291 33.648 9.109 34.248 ;
     RECT  9.109 33.6 9.137 34.248 ;
     RECT  9.137 33.6 9.353 33.624 ;
     RECT  9.341 3.984 9.425 4.008 ;
     RECT  8.104 5.04 9.493 6.84 ;
     RECT  8.345 2.88 10.069 2.904 ;
     RECT  9.493 4.944 10.069 6.84 ;
     RECT  9.589 34.752 10.261 34.776 ;
     RECT  10.261 34.704 10.309 34.824 ;
     RECT  10.309 34.176 10.357 34.824 ;
     RECT  8.104 1.728 10.508 1.752 ;
     RECT  10.069 2.88 10.508 3.624 ;
     RECT  10.069 4.944 10.508 7.08 ;
     RECT  10.069 29.52 10.508 29.544 ;
     RECT  9.349 31.296 10.508 31.32 ;
     RECT  10.357 34.176 10.508 34.872 ;
     RECT  10.508 1.728 10.595 34.872 ;
     RECT  10.595 1.728 10.804 34.824 ;
     RECT  10.357 0.288 10.835 0.312 ;
     RECT  10.804 34.752 10.835 34.824 ;
     RECT  10.804 29.52 10.937 29.544 ;
     RECT  10.804 2.88 11.297 6.936 ;
     RECT  10.804 33.6 11.333 33.624 ;
     RECT  11.297 2.88 11.369 2.904 ;
     RECT  11.297 3.936 11.657 6.936 ;
     RECT  10.804 1.728 11.797 1.752 ;
     RECT  11.833 19.584 11.981 19.608 ;
     RECT  10.835 34.752 12.037 34.776 ;
     RECT  11.996 0.528 12.083 0.552 ;
     RECT  11.797 35.904 12.413 35.928 ;
     RECT  11.797 1.728 12.757 1.8 ;
     RECT  12.409 2.88 13.057 2.904 ;
     RECT  11.657 3.936 13.057 6.648 ;
     RECT  12.757 1.728 13.208 1.848 ;
     RECT  13.057 2.88 13.208 6.648 ;
     RECT  12.037 34.176 13.208 34.776 ;
     RECT  13.208 1.728 13.237 34.776 ;
     RECT  13.237 1.728 13.477 34.872 ;
     RECT  13.477 1.728 13.504 34.968 ;
     RECT  13.093 0.192 13.619 0.216 ;
     RECT  13.504 1.728 13.667 7.224 ;
     RECT  13.504 34.176 13.667 34.968 ;
     RECT  13.667 3.024 13.709 7.224 ;
     RECT  13.709 3.648 13.9 7.224 ;
     RECT  13.9 3.648 14.243 5.544 ;
     RECT  13.667 34.176 14.249 34.776 ;
     RECT  14.677 30.768 14.821 30.792 ;
     RECT  14.821 30.768 14.861 30.888 ;
     RECT  13.9 6.624 14.893 7.224 ;
     RECT  13.667 1.728 15.037 1.8 ;
     RECT  14.249 34.752 15.781 34.776 ;
     RECT  15.037 1.728 15.908 2.28 ;
     RECT  14.243 4.08 15.908 5.544 ;
     RECT  14.893 6.528 15.908 7.224 ;
     RECT  14.861 30.864 15.908 30.888 ;
     RECT  15.205 33.6 15.908 33.624 ;
     RECT  15.781 34.752 15.908 34.872 ;
     RECT  15.908 1.728 16.204 34.872 ;
     RECT  16.204 2.832 16.265 6.936 ;
     RECT  16.165 0.192 16.355 0.216 ;
     RECT  16.204 34.656 16.355 34.872 ;
     RECT  16.355 34.656 16.481 34.776 ;
     RECT  16.481 34.704 16.985 34.776 ;
     RECT  17.197 0.528 17.891 0.552 ;
     RECT  16.204 1.728 18.037 1.8 ;
     RECT  18.037 1.632 18.053 1.8 ;
     RECT  16.265 2.832 18.053 6.84 ;
     RECT  16.985 34.752 18.085 34.776 ;
     RECT  18.277 9.072 18.421 9.096 ;
     RECT  16.204 29.04 18.469 29.064 ;
     RECT  18.085 34.656 18.469 34.776 ;
     RECT  18.053 1.632 18.497 6.84 ;
     RECT  18.497 1.728 18.608 6.84 ;
     RECT  18.421 8.544 18.608 9.096 ;
     RECT  18.469 29.04 18.608 29.64 ;
     RECT  17.605 31.296 18.608 31.32 ;
     RECT  18.469 34.656 18.608 34.824 ;
     RECT  18.608 1.728 18.904 34.824 ;
     RECT  18.853 0.192 19.043 0.216 ;
     RECT  18.904 34.656 19.043 34.824 ;
     RECT  18.904 1.728 19.153 6.888 ;
     RECT  19.153 3.936 19.235 6.888 ;
     RECT  18.904 29.616 19.541 29.64 ;
     RECT  19.153 1.728 19.619 2.904 ;
     RECT  18.904 8.544 19.715 8.568 ;
     RECT  19.235 4.08 19.955 6.888 ;
     RECT  19.619 1.728 20.081 1.752 ;
     RECT  19.333 35.904 20.369 35.928 ;
     RECT  19.619 2.736 20.54 2.904 ;
     RECT  19.955 4.08 20.54 6.648 ;
     RECT  20.54 2.736 20.917 6.648 ;
     RECT  20.917 2.256 20.941 6.648 ;
     RECT  21.109 0.288 21.157 0.312 ;
     RECT  19.043 34.656 21.157 34.776 ;
     RECT  21.157 34.656 21.299 34.872 ;
     RECT  20.941 2.256 21.308 6.84 ;
     RECT  21.013 7.824 21.308 7.848 ;
     RECT  20.197 11.424 21.308 11.448 ;
     RECT  21.013 29.616 21.308 29.64 ;
     RECT  18.904 33.6 21.308 33.624 ;
     RECT  21.299 34.656 21.308 34.776 ;
     RECT  21.157 0.192 21.539 0.312 ;
     RECT  21.308 2.148 21.604 34.776 ;
     RECT  21.604 2.148 21.733 6.84 ;
     RECT  21.733 1.728 21.971 6.84 ;
     RECT  21.493 35.904 21.989 35.928 ;
     RECT  21.604 34.656 22.241 34.776 ;
     RECT  21.604 33.6 22.745 33.624 ;
     RECT  21.604 8.544 22.853 8.568 ;
     RECT  21.971 1.728 22.94 6.744 ;
     RECT  22.94 1.728 23.027 6.84 ;
     RECT  21.836 0.144 23.171 0.168 ;
     RECT  21.604 29.616 23.221 29.64 ;
     RECT  22.241 34.752 23.701 34.776 ;
     RECT  23.701 34.656 23.941 34.776 ;
     RECT  23.027 1.728 24.008 6.744 ;
     RECT  24.001 8.736 24.008 8.76 ;
     RECT  22.981 10.272 24.008 10.296 ;
     RECT  23.221 29.376 24.008 29.64 ;
     RECT  23.941 34.656 24.008 34.872 ;
     RECT  24.008 1.728 24.181 34.872 ;
     RECT  24.181 1.728 24.304 34.92 ;
     RECT  24.181 0.288 24.419 0.312 ;
     RECT  24.304 1.728 24.419 6.84 ;
     RECT  24.304 8.736 24.419 8.76 ;
     RECT  24.304 34.224 24.419 34.92 ;
     RECT  24.419 34.224 24.515 34.872 ;
     RECT  24.304 29.472 24.653 30.504 ;
     RECT  24.304 33.072 25.187 33.096 ;
     RECT  24.653 29.472 25.193 29.64 ;
     RECT  24.661 35.904 25.265 35.928 ;
     RECT  24.515 34.224 25.58 34.248 ;
     RECT  24.419 1.728 25.667 6.696 ;
     RECT  25.667 2.88 26.581 6.696 ;
     RECT  25.58 34.224 26.588 34.344 ;
     RECT  26.588 34.224 26.675 34.728 ;
     RECT  25.667 1.728 26.708 1.752 ;
     RECT  26.581 2.88 26.708 6.84 ;
     RECT  26.549 7.968 26.708 7.992 ;
     RECT  26.089 10.272 26.708 10.296 ;
     RECT  26.305 26.784 26.708 26.808 ;
     RECT  25.193 29.616 26.708 29.64 ;
     RECT  26.675 34.224 26.708 34.68 ;
     RECT  26.708 1.728 27.004 34.68 ;
     RECT  26.869 0.288 27.109 0.312 ;
     RECT  27.109 0.192 27.155 0.312 ;
     RECT  27.155 0.192 27.251 0.216 ;
     RECT  27.004 1.728 27.251 6.696 ;
     RECT  27.004 34.224 27.353 34.68 ;
     RECT  27.004 29.76 27.641 29.784 ;
     RECT  27.589 35.904 27.785 35.928 ;
     RECT  27.251 1.728 27.875 1.848 ;
     RECT  27.251 2.88 27.929 6.696 ;
     RECT  27.929 2.88 28.037 6.6 ;
     RECT  28.172 0.144 28.259 0.168 ;
     RECT  28.037 2.88 28.421 2.904 ;
     RECT  27.875 1.728 28.897 1.8 ;
     RECT  28.421 2.832 28.897 2.904 ;
     RECT  27.353 34.224 28.997 34.296 ;
     RECT  28.037 3.936 29.029 6.6 ;
     RECT  28.897 1.728 29.173 2.904 ;
     RECT  29.029 3.888 29.173 6.6 ;
     RECT  28.997 34.224 29.221 34.344 ;
     RECT  29.173 1.728 29.408 6.6 ;
     RECT  29.257 26.784 29.408 26.808 ;
     RECT  28.789 29.04 29.408 29.064 ;
     RECT  29.221 34.224 29.408 34.872 ;
     RECT  29.408 1.728 29.603 34.872 ;
     RECT  29.603 1.728 29.704 34.776 ;
     RECT  29.704 1.728 30.025 6.84 ;
     RECT  29.704 8.544 30.493 8.568 ;
     RECT  29.704 10.848 30.563 10.872 ;
     RECT  29.704 34.656 30.757 34.776 ;
     RECT  30.757 0.192 30.899 0.216 ;
     RECT  30.757 34.656 30.899 34.824 ;
     RECT  30.757 36.48 30.899 36.504 ;
     RECT  30.899 34.656 30.997 34.776 ;
     RECT  30.025 3.312 31.133 6.84 ;
     RECT  30.025 1.728 31.141 2.328 ;
     RECT  31.133 3.312 31.141 5.304 ;
     RECT  31.1 0.144 31.187 0.168 ;
     RECT  30.997 34.608 31.909 34.776 ;
     RECT  31.909 34.608 31.916 34.872 ;
     RECT  31.141 1.728 32.108 5.304 ;
     RECT  31.133 6.288 32.108 6.84 ;
     RECT  29.704 29.04 32.108 29.064 ;
     RECT  31.237 30.816 32.108 30.84 ;
     RECT  31.916 33.648 32.108 34.872 ;
     RECT  31.909 0.288 32.243 0.312 ;
     RECT  32.108 1.728 32.243 34.872 ;
     RECT  32.243 1.728 32.404 34.776 ;
     RECT  32.404 1.728 32.501 6.84 ;
     RECT  32.501 1.728 32.533 1.752 ;
     RECT  32.533 1.104 32.723 1.752 ;
     RECT  32.404 34.176 33.005 34.776 ;
     RECT  32.501 2.88 33.011 6.84 ;
     RECT  33.005 34.224 33.077 34.776 ;
     RECT  32.437 35.904 33.113 35.928 ;
     RECT  32.404 33.072 33.437 33.096 ;
     RECT  33.011 3.984 33.797 6.84 ;
     RECT  32.723 1.728 34.121 1.752 ;
     RECT  33.011 2.88 34.645 2.904 ;
     RECT  33.797 3.984 34.645 4.968 ;
     RECT  34.645 2.88 34.808 4.968 ;
     RECT  33.797 6.576 34.808 6.84 ;
     RECT  33.077 34.224 34.808 34.344 ;
     RECT  34.808 2.148 34.885 34.572 ;
     RECT  34.885 2.148 35.104 34.728 ;
     RECT  34.885 0.288 35.125 0.312 ;
     RECT  35.104 34.704 35.125 34.728 ;
     RECT  35.125 0.192 35.219 0.312 ;
     RECT  35.219 0.192 35.267 0.216 ;
     RECT  35.104 33.072 35.273 33.672 ;
     RECT  35.125 34.704 35.315 34.824 ;
     RECT  35.104 2.148 35.365 3.432 ;
     RECT  35.273 33.072 35.633 33.144 ;
     RECT  35.633 33.12 35.885 33.144 ;
     RECT  35.104 4.416 36.313 5.688 ;
     RECT  35.104 6.816 36.313 6.84 ;
     RECT  35.845 35.904 36.461 35.928 ;
     RECT  35.365 1.728 36.505 3.432 ;
     RECT  36.085 34.224 36.812 34.248 ;
     RECT  36.505 1.728 37.073 1.8 ;
     RECT  36.812 34.224 37.093 34.296 ;
     RECT  37.093 34.176 37.381 34.296 ;
     RECT  36.505 2.88 37.508 3.432 ;
     RECT  36.313 4.416 37.508 6.84 ;
     RECT  36.325 29.04 37.508 29.064 ;
     RECT  35.104 30.192 37.508 30.216 ;
     RECT  37.381 31.2 37.508 31.224 ;
     RECT  37.381 34.176 37.508 34.824 ;
     RECT  37.508 2.148 37.612 34.824 ;
     RECT  37.612 2.256 37.804 34.824 ;
     RECT  37.804 34.704 37.813 34.824 ;
     RECT  37.813 34.704 37.955 34.872 ;
     RECT  37.381 0.288 38.147 0.312 ;
     RECT  37.804 33.6 38.405 33.624 ;
     RECT  37.804 30.768 38.513 31.224 ;
     RECT  38.513 30.768 38.771 30.888 ;
     RECT  37.804 2.256 38.773 6.84 ;
     RECT  38.771 30.768 38.801 30.792 ;
     RECT  37.955 34.704 39.013 34.776 ;
     RECT  38.773 1.728 39.089 6.84 ;
     RECT  39.013 34.608 39.253 34.776 ;
     RECT  39.157 0.144 39.395 0.168 ;
     RECT  39.253 34.56 39.932 34.776 ;
     RECT  39.089 1.728 40.069 6.552 ;
     RECT  39.932 34.224 40.069 34.776 ;
     RECT  40.069 1.728 40.208 6.84 ;
     RECT  40.129 20.064 40.208 20.088 ;
     RECT  40.069 34.224 40.208 34.872 ;
     RECT  40.208 1.728 40.504 34.872 ;
     RECT  40.501 0.192 40.643 0.216 ;
     RECT  40.504 34.224 40.643 34.872 ;
     RECT  40.643 34.224 41.027 34.776 ;
     RECT  40.504 4.128 41.357 5.736 ;
     RECT  40.504 1.728 41.557 3 ;
     RECT  41.357 4.128 41.557 5.256 ;
     RECT  40.504 6.816 41.605 6.84 ;
     RECT  41.569 20.016 41.717 20.328 ;
     RECT  41.804 0.144 41.891 0.168 ;
     RECT  41.557 1.728 42.397 5.256 ;
     RECT  41.605 6.288 42.397 6.84 ;
     RECT  41.027 34.704 42.505 34.776 ;
     RECT  42.505 34.224 42.757 34.776 ;
     RECT  42.397 1.728 42.908 6.84 ;
     RECT  41.717 20.016 42.908 20.04 ;
     RECT  40.504 29.04 42.908 29.064 ;
     RECT  42.757 34.224 42.908 34.872 ;
     RECT  42.908 1.728 43.187 34.872 ;
     RECT  43.187 1.728 43.204 34.824 ;
     RECT  43.204 9.12 43.331 9.144 ;
     RECT  43.204 34.224 43.331 34.824 ;
     RECT  43.204 17.088 43.337 17.112 ;
     RECT  42.757 0.192 43.724 0.216 ;
     RECT  43.724 0.144 43.801 0.216 ;
     RECT  43.801 0.144 43.811 0.6 ;
     RECT  43.204 22.608 43.985 22.632 ;
     RECT  44.293 11.424 44.381 11.448 ;
     RECT  43.811 0.576 44.435 0.6 ;
     RECT  43.331 34.224 44.435 34.776 ;
     RECT  43.204 1.728 44.489 6.84 ;
     RECT  44.489 2.88 45.493 6.84 ;
     RECT  44.965 0.528 45.589 0.552 ;
     RECT  44.435 34.656 45.589 34.776 ;
     RECT  44.489 1.728 45.608 1.752 ;
     RECT  45.493 2.88 45.608 6.888 ;
     RECT  45.445 8.544 45.608 8.568 ;
     RECT  45.589 34.656 45.608 34.824 ;
     RECT  45.608 1.728 45.829 34.824 ;
     RECT  45.829 1.728 45.904 34.92 ;
     RECT  45.589 0.192 46.019 0.552 ;
     RECT  45.904 2.736 46.019 6.84 ;
     RECT  45.904 33.6 46.037 34.92 ;
     RECT  46.037 34.176 46.067 34.92 ;
     RECT  45.904 9.072 46.073 9.096 ;
     RECT  45.904 10.848 46.153 10.872 ;
     RECT  46.019 0.528 46.177 0.552 ;
     RECT  45.904 1.728 46.177 1.752 ;
     RECT  46.019 2.736 46.307 6.552 ;
     RECT  46.307 2.736 46.325 6.312 ;
     RECT  46.177 0.528 46.355 1.752 ;
     RECT  45.904 22.8 46.361 22.92 ;
     RECT  46.361 22.896 46.469 22.92 ;
     RECT  46.067 34.176 46.685 34.824 ;
     RECT  46.355 0.528 46.721 0.552 ;
     RECT  46.685 34.176 46.721 34.776 ;
     RECT  46.721 34.704 47.297 34.776 ;
     RECT  47.029 30.192 47.317 30.216 ;
     RECT  46.325 2.736 47.333 5.88 ;
     RECT  46.355 1.728 47.513 1.752 ;
     RECT  47.333 2.832 47.545 5.88 ;
     RECT  47.317 29.616 47.797 30.216 ;
     RECT  47.557 1.776 48.308 1.8 ;
     RECT  47.545 2.832 48.308 6.264 ;
     RECT  47.797 29.568 48.308 30.216 ;
     RECT  47.297 34.752 48.308 34.776 ;
     RECT  48.181 0.192 48.323 0.216 ;
     RECT  48.277 35.904 48.517 35.928 ;
     RECT  48.308 1.776 48.604 34.776 ;
     RECT  48.604 1.776 48.725 6.696 ;
     RECT  48.517 0.288 48.755 0.312 ;
     RECT  48.517 35.904 48.917 35.976 ;
     RECT  48.725 1.728 48.956 6.696 ;
     RECT  48.604 34.752 48.989 34.776 ;
     RECT  48.956 1.152 48.995 6.696 ;
     RECT  48.995 1.152 49.043 2.904 ;
     RECT  49.043 1.728 49.529 2.904 ;
     RECT  48.604 30.72 49.637 30.744 ;
     RECT  48.917 35.904 49.853 35.928 ;
     RECT  48.604 7.968 49.889 7.992 ;
     RECT  48.604 33.6 49.961 33.624 ;
     RECT  50.005 0.48 50.065 0.504 ;
     RECT  50.065 0.48 50.101 0.552 ;
     RECT  50.101 0.288 50.435 0.552 ;
     RECT  49.529 2.688 50.636 2.904 ;
     RECT  49.957 34.752 50.636 34.776 ;
     RECT  50.636 34.224 50.681 34.776 ;
     RECT  50.636 1.728 51.008 2.904 ;
     RECT  48.995 3.984 51.008 6.696 ;
     RECT  50.197 29.616 51.008 29.64 ;
     RECT  50.681 34.224 51.008 34.572 ;
     RECT  51.008 1.728 51.112 34.572 ;
     RECT  50.965 35.904 51.205 35.928 ;
     RECT  51.112 1.728 51.304 34.302 ;
     RECT  50.435 0.528 51.365 0.552 ;
     RECT  51.304 1.728 51.365 6.936 ;
     RECT  51.205 35.904 51.653 35.976 ;
     RECT  51.304 29.952 52.121 30.744 ;
     RECT  51.365 1.728 52.405 3.432 ;
     RECT  51.365 4.56 52.405 6.936 ;
     RECT  52.121 29.952 52.405 30.216 ;
     RECT  51.788 0.144 52.501 0.168 ;
     RECT  51.653 35.904 52.661 35.928 ;
     RECT  52.501 0.144 52.691 0.216 ;
     RECT  52.405 1.728 52.796 6.936 ;
     RECT  52.691 0.144 53.075 0.168 ;
     RECT  51.304 34.176 53.125 34.2 ;
     RECT  52.796 1.728 53.593 7.272 ;
     RECT  53.125 33.648 53.605 34.2 ;
     RECT  53.593 1.152 53.677 7.272 ;
     RECT  53.677 1.2 53.708 7.272 ;
     RECT  52.837 9.12 53.708 9.144 ;
     RECT  53.341 10.8 53.708 10.824 ;
     RECT  53.629 20.112 53.708 20.136 ;
     RECT  53.629 22.032 53.708 22.056 ;
     RECT  52.405 29.616 53.708 30.216 ;
     RECT  53.605 33.648 53.708 34.68 ;
     RECT  53.708 1.2 53.891 34.68 ;
     RECT  53.891 1.728 54.004 34.68 ;
     RECT  54.004 34.224 54.025 34.68 ;
     RECT  54.004 7.44 54.131 7.464 ;
     RECT  54.004 33.072 54.131 33.096 ;
     RECT  54.025 34.224 54.131 34.776 ;
     RECT  54.004 26.784 54.245 26.808 ;
     RECT  53.845 35.904 54.325 35.928 ;
     RECT  54.004 2.832 54.469 6.312 ;
     RECT  54.469 2.88 55.052 6.312 ;
     RECT  54.004 1.728 55.072 1.752 ;
     RECT  54.131 34.224 55.093 34.248 ;
     RECT  55.052 2.88 55.139 6.84 ;
     RECT  54.004 9.12 55.139 9.144 ;
     RECT  54.325 35.904 55.145 35.976 ;
     RECT  55.072 1.728 55.181 1.8 ;
     RECT  55.093 33.648 55.253 34.248 ;
     RECT  55.139 2.88 55.645 6.264 ;
     RECT  55.181 1.728 55.721 1.752 ;
     RECT  55.645 2.832 56.408 6.264 ;
     RECT  55.333 29.616 56.408 29.64 ;
     RECT  55.253 34.224 56.408 34.248 ;
     RECT  56.408 2.148 56.533 34.572 ;
     RECT  56.533 0.288 56.653 0.312 ;
     RECT  56.533 2.148 56.704 34.728 ;
     RECT  56.653 0.288 56.773 0.408 ;
     RECT  56.773 0.192 56.867 0.408 ;
     RECT  56.867 0.192 56.915 0.216 ;
     RECT  56.704 2.88 57.017 6.888 ;
     RECT  56.704 33.648 57.017 34.728 ;
     RECT  57.017 2.88 57.197 6.12 ;
     RECT  55.145 35.904 57.253 35.928 ;
     RECT  57.017 33.648 57.305 34.248 ;
     RECT  56.704 30.048 57.629 30.072 ;
     RECT  57.253 35.904 57.989 35.976 ;
     RECT  56.704 22.752 58.133 22.776 ;
     RECT  57.197 3.408 58.261 6.12 ;
     RECT  57.989 35.904 58.385 35.928 ;
     RECT  57.005 1.728 58.565 1.752 ;
     RECT  58.261 2.88 58.633 6.12 ;
     RECT  58.633 2.832 58.885 6.12 ;
     RECT  57.305 34.224 58.933 34.248 ;
     RECT  57.733 33.072 58.981 33.096 ;
     RECT  58.933 34.224 58.981 34.728 ;
     RECT  58.885 2.148 59.108 6.12 ;
     RECT  58.489 10.8 59.108 10.824 ;
     RECT  58.501 29.616 59.108 29.64 ;
     RECT  58.933 30.672 59.108 30.696 ;
     RECT  58.981 33.072 59.108 34.728 ;
     RECT  59.108 2.148 59.212 34.728 ;
     RECT  58.933 0.288 59.267 0.312 ;
     RECT  59.212 2.418 59.267 34.728 ;
     RECT  59.267 2.418 59.404 34.68 ;
     RECT  59.461 0.192 59.603 0.216 ;
     RECT  59.404 2.88 59.603 3.048 ;
     RECT  59.404 33.648 59.603 34.68 ;
     RECT  59.404 30.192 59.681 30.696 ;
     RECT  59.603 33.648 59.861 34.248 ;
     RECT  59.404 4.416 60.469 6.12 ;
     RECT  59.861 33.648 60.653 33.672 ;
     RECT  60.181 1.728 60.661 1.752 ;
     RECT  59.681 30.192 60.661 30.216 ;
     RECT  60.469 4.416 60.865 6.6 ;
     RECT  59.603 2.88 61.261 2.904 ;
     RECT  60.901 35.904 61.301 35.928 ;
     RECT  61.141 34.224 61.381 34.248 ;
     RECT  61.261 2.832 61.621 2.904 ;
     RECT  60.865 4.032 61.621 6.6 ;
     RECT  61.381 34.224 61.669 34.344 ;
     RECT  61.669 34.224 61.729 34.392 ;
     RECT  60.661 1.728 61.808 1.8 ;
     RECT  61.621 2.832 61.808 6.6 ;
     RECT  60.661 29.616 61.808 30.216 ;
     RECT  61.297 33.072 61.808 33.096 ;
     RECT  61.729 34.224 61.808 34.728 ;
     RECT  61.808 1.728 61.955 34.728 ;
     RECT  61.955 1.728 61.985 34.68 ;
     RECT  61.985 2.418 62.104 34.68 ;
     RECT  62.149 0.192 62.291 0.216 ;
     RECT  62.104 34.656 62.291 34.68 ;
     RECT  62.104 33.072 62.417 33.672 ;
     RECT  62.104 14.784 62.633 14.808 ;
     RECT  62.104 4.416 62.993 6.552 ;
     RECT  62.104 30.48 63.101 30.504 ;
     RECT  62.417 33.648 63.137 33.672 ;
     RECT  62.629 35.904 63.245 35.928 ;
     RECT  62.993 4.512 63.253 6.552 ;
     RECT  63.349 1.728 63.529 1.752 ;
     RECT  62.104 2.88 63.529 3.432 ;
     RECT  63.349 34.224 63.829 34.248 ;
     RECT  63.829 34.224 64.033 34.296 ;
     RECT  63.529 1.728 64.508 3.432 ;
     RECT  63.253 4.512 64.508 6.888 ;
     RECT  63.109 29.952 64.508 30.216 ;
     RECT  64.033 34.224 64.508 34.344 ;
     RECT  64.508 1.728 64.549 34.572 ;
     RECT  64.549 1.728 64.804 34.728 ;
     RECT  64.804 34.656 64.835 34.728 ;
     RECT  64.789 0.192 64.892 0.216 ;
     RECT  64.892 0.192 64.931 0.312 ;
     RECT  64.804 33.072 64.972 33.096 ;
     RECT  64.931 0.288 64.979 0.312 ;
     RECT  64.804 2.784 65.009 5.784 ;
     RECT  64.835 34.704 65.029 34.728 ;
     RECT  65.009 4.368 65.189 5.784 ;
     RECT  64.804 1.728 65.797 1.752 ;
     RECT  65.029 34.704 65.797 34.776 ;
     RECT  65.009 2.784 66.089 3.048 ;
     RECT  65.797 34.608 66.089 34.776 ;
     RECT  64.804 29.04 66.161 29.064 ;
     RECT  65.189 4.368 66.197 5.688 ;
     RECT  65.797 1.728 66.277 1.8 ;
     RECT  66.037 35.904 66.413 35.928 ;
     RECT  66.121 3.36 66.517 3.384 ;
     RECT  66.089 34.704 66.629 34.776 ;
     RECT  66.629 34.704 66.701 34.728 ;
     RECT  66.277 1.728 66.917 2.28 ;
     RECT  66.917 2.148 67.208 2.28 ;
     RECT  66.517 3.36 67.208 3.48 ;
     RECT  66.197 4.512 67.208 4.536 ;
     RECT  66.589 6 67.208 6.024 ;
     RECT  66.757 29.616 67.208 29.64 ;
     RECT  67.208 2.148 67.312 34.572 ;
     RECT  67.312 2.256 67.504 34.302 ;
     RECT  67.504 4.512 67.673 4.536 ;
     RECT  67.504 6 67.673 6.024 ;
     RECT  67.504 2.256 68.033 2.28 ;
    LAYER M5 ;
     RECT  21.888 0.133 21.984 0.144 ;
     RECT  22.008 0.133 22.272 0.144 ;
     RECT  22.296 0.133 22.512 0.144 ;
     RECT  22.536 0.133 22.752 0.144 ;
     RECT  22.776 0.133 22.992 0.144 ;
     RECT  23.016 0.133 23.16 0.144 ;
     RECT  28.224 0.133 28.248 0.144 ;
     RECT  31.152 0.133 31.176 0.144 ;
     RECT  39.36 0.133 39.384 0.144 ;
     RECT  41.856 0.133 41.88 0.144 ;
     RECT  43.776 0.133 43.8 0.144 ;
     RECT  51.84 0.133 51.936 0.144 ;
     RECT  51.96 0.133 52.176 0.144 ;
     RECT  52.2 0.133 52.416 0.144 ;
     RECT  52.44 0.133 52.656 0.144 ;
     RECT  52.68 0.133 52.896 0.144 ;
     RECT  52.92 0.133 53.064 0.144 ;
     RECT  4.536 0.144 4.752 0.192 ;
     RECT  4.776 0.144 4.992 0.192 ;
     RECT  5.016 0.144 5.232 0.192 ;
     RECT  5.256 0.144 5.472 0.192 ;
     RECT  5.496 0.144 5.712 0.192 ;
     RECT  5.736 0.144 5.952 0.192 ;
     RECT  5.976 0.144 6.192 0.192 ;
     RECT  6.216 0.144 6.432 0.192 ;
     RECT  6.456 0.144 6.672 0.192 ;
     RECT  6.696 0.144 6.912 0.192 ;
     RECT  6.936 0.144 7.152 0.192 ;
     RECT  7.176 0.144 7.392 0.192 ;
     RECT  7.416 0.144 7.632 0.192 ;
     RECT  7.656 0.144 7.92 0.192 ;
     RECT  7.944 0.144 8.16 0.192 ;
     RECT  8.184 0.144 8.4 0.192 ;
     RECT  8.424 0.144 8.64 0.192 ;
     RECT  8.664 0.144 8.88 0.192 ;
     RECT  8.904 0.144 9.12 0.192 ;
     RECT  9.144 0.144 9.36 0.192 ;
     RECT  9.384 0.144 9.6 0.192 ;
     RECT  9.624 0.144 9.84 0.192 ;
     RECT  9.864 0.144 10.08 0.192 ;
     RECT  10.104 0.144 10.32 0.192 ;
     RECT  10.344 0.144 10.56 0.192 ;
     RECT  10.584 0.144 10.8 0.192 ;
     RECT  10.824 0.144 11.04 0.192 ;
     RECT  11.064 0.144 11.28 0.192 ;
     RECT  11.304 0.144 11.568 0.192 ;
     RECT  11.592 0.144 11.808 0.192 ;
     RECT  11.832 0.144 12.048 0.192 ;
     RECT  12.072 0.144 12.288 0.192 ;
     RECT  12.312 0.144 12.528 0.192 ;
     RECT  12.552 0.144 12.768 0.192 ;
     RECT  12.792 0.144 13.008 0.192 ;
     RECT  13.032 0.144 13.248 0.192 ;
     RECT  13.272 0.144 13.488 0.192 ;
     RECT  13.512 0.144 13.728 0.192 ;
     RECT  13.752 0.144 13.968 0.192 ;
     RECT  13.992 0.144 14.208 0.192 ;
     RECT  14.232 0.144 14.448 0.192 ;
     RECT  14.472 0.144 14.688 0.192 ;
     RECT  14.712 0.144 14.928 0.192 ;
     RECT  14.952 0.144 15.216 0.192 ;
     RECT  15.24 0.144 15.456 0.192 ;
     RECT  15.48 0.144 15.696 0.192 ;
     RECT  15.72 0.144 15.936 0.192 ;
     RECT  15.96 0.144 16.176 0.192 ;
     RECT  16.2 0.144 16.416 0.192 ;
     RECT  16.44 0.144 16.656 0.192 ;
     RECT  16.68 0.144 16.896 0.192 ;
     RECT  16.92 0.144 17.136 0.192 ;
     RECT  17.16 0.144 17.376 0.192 ;
     RECT  17.4 0.144 17.616 0.192 ;
     RECT  17.64 0.144 17.856 0.192 ;
     RECT  17.88 0.144 18.096 0.192 ;
     RECT  18.12 0.144 18.336 0.192 ;
     RECT  18.36 0.144 18.576 0.192 ;
     RECT  18.6 0.144 18.864 0.192 ;
     RECT  18.888 0.144 19.104 0.192 ;
     RECT  19.128 0.144 19.344 0.192 ;
     RECT  19.368 0.144 19.584 0.192 ;
     RECT  19.608 0.144 19.824 0.192 ;
     RECT  19.848 0.144 20.064 0.192 ;
     RECT  20.088 0.144 20.304 0.192 ;
     RECT  20.328 0.144 20.544 0.192 ;
     RECT  20.568 0.144 20.784 0.192 ;
     RECT  20.808 0.144 21.024 0.192 ;
     RECT  21.048 0.144 21.264 0.192 ;
     RECT  21.288 0.144 21.504 0.192 ;
     RECT  21.528 0.144 21.744 0.192 ;
     RECT  21.768 0.144 21.984 0.192 ;
     RECT  22.008 0.144 22.272 0.192 ;
     RECT  22.296 0.144 22.512 0.192 ;
     RECT  22.536 0.144 22.752 0.192 ;
     RECT  22.776 0.144 22.992 0.192 ;
     RECT  23.016 0.144 23.232 0.192 ;
     RECT  23.256 0.144 23.472 0.192 ;
     RECT  23.496 0.144 23.712 0.192 ;
     RECT  23.736 0.144 23.952 0.192 ;
     RECT  23.976 0.144 24.192 0.192 ;
     RECT  24.216 0.144 24.432 0.192 ;
     RECT  24.456 0.144 24.672 0.192 ;
     RECT  24.696 0.144 24.912 0.192 ;
     RECT  24.936 0.144 25.152 0.192 ;
     RECT  25.176 0.144 25.392 0.192 ;
     RECT  25.416 0.144 25.632 0.192 ;
     RECT  25.656 0.144 25.92 0.192 ;
     RECT  25.944 0.144 26.16 0.192 ;
     RECT  26.184 0.144 26.4 0.192 ;
     RECT  26.424 0.144 26.64 0.192 ;
     RECT  26.664 0.144 26.88 0.192 ;
     RECT  26.904 0.144 27.12 0.192 ;
     RECT  27.144 0.144 27.36 0.192 ;
     RECT  27.384 0.144 27.6 0.192 ;
     RECT  27.624 0.144 27.84 0.192 ;
     RECT  27.864 0.144 28.08 0.192 ;
     RECT  28.104 0.144 28.32 0.192 ;
     RECT  28.344 0.144 28.56 0.192 ;
     RECT  28.584 0.144 28.8 0.192 ;
     RECT  28.824 0.144 29.04 0.192 ;
     RECT  29.064 0.144 29.28 0.192 ;
     RECT  29.304 0.144 29.568 0.192 ;
     RECT  29.592 0.144 29.808 0.192 ;
     RECT  29.832 0.144 30.048 0.192 ;
     RECT  30.072 0.144 30.288 0.192 ;
     RECT  30.312 0.144 30.528 0.192 ;
     RECT  30.552 0.144 30.768 0.192 ;
     RECT  30.792 0.144 31.008 0.192 ;
     RECT  31.032 0.144 31.248 0.192 ;
     RECT  31.272 0.144 31.488 0.192 ;
     RECT  31.512 0.144 31.728 0.192 ;
     RECT  31.752 0.144 31.968 0.192 ;
     RECT  31.992 0.144 32.208 0.192 ;
     RECT  32.232 0.144 32.448 0.192 ;
     RECT  32.472 0.144 32.688 0.192 ;
     RECT  32.712 0.144 32.976 0.192 ;
     RECT  33 0.144 33.216 0.192 ;
     RECT  33.24 0.144 33.456 0.192 ;
     RECT  33.48 0.144 33.696 0.192 ;
     RECT  33.72 0.144 33.936 0.192 ;
     RECT  33.96 0.144 34.176 0.192 ;
     RECT  34.2 0.144 34.416 0.192 ;
     RECT  34.44 0.144 34.656 0.192 ;
     RECT  34.68 0.144 34.896 0.192 ;
     RECT  34.92 0.144 35.136 0.192 ;
     RECT  35.16 0.144 35.376 0.192 ;
     RECT  35.4 0.144 35.616 0.192 ;
     RECT  35.64 0.144 35.856 0.192 ;
     RECT  35.88 0.144 36.096 0.192 ;
     RECT  36.12 0.144 36.336 0.192 ;
     RECT  36.36 0.144 36.624 0.192 ;
     RECT  36.648 0.144 36.864 0.192 ;
     RECT  36.888 0.144 37.104 0.192 ;
     RECT  37.128 0.144 37.344 0.192 ;
     RECT  37.368 0.144 37.584 0.192 ;
     RECT  37.608 0.144 37.824 0.192 ;
     RECT  37.848 0.144 38.064 0.192 ;
     RECT  38.088 0.144 38.304 0.192 ;
     RECT  38.328 0.144 38.544 0.192 ;
     RECT  38.568 0.144 38.784 0.192 ;
     RECT  38.808 0.144 39.024 0.192 ;
     RECT  39.048 0.144 39.264 0.192 ;
     RECT  39.288 0.144 39.504 0.192 ;
     RECT  39.528 0.144 39.744 0.192 ;
     RECT  39.768 0.144 39.984 0.192 ;
     RECT  40.008 0.144 40.272 0.192 ;
     RECT  40.296 0.144 40.512 0.192 ;
     RECT  40.536 0.144 40.752 0.192 ;
     RECT  40.776 0.144 40.992 0.192 ;
     RECT  41.016 0.144 41.232 0.192 ;
     RECT  41.256 0.144 41.472 0.192 ;
     RECT  41.496 0.144 41.712 0.192 ;
     RECT  41.736 0.144 41.952 0.192 ;
     RECT  41.976 0.144 42.192 0.192 ;
     RECT  42.216 0.144 42.432 0.192 ;
     RECT  42.456 0.144 42.672 0.192 ;
     RECT  42.696 0.144 42.912 0.192 ;
     RECT  42.936 0.144 43.152 0.192 ;
     RECT  43.176 0.144 43.392 0.192 ;
     RECT  43.416 0.144 43.632 0.192 ;
     RECT  43.656 0.144 43.92 0.192 ;
     RECT  43.944 0.144 44.16 0.192 ;
     RECT  44.184 0.144 44.4 0.192 ;
     RECT  44.424 0.144 44.64 0.192 ;
     RECT  44.664 0.144 44.88 0.192 ;
     RECT  44.904 0.144 45.12 0.192 ;
     RECT  45.144 0.144 45.36 0.192 ;
     RECT  45.384 0.144 45.6 0.192 ;
     RECT  45.624 0.144 45.84 0.192 ;
     RECT  45.864 0.144 46.08 0.192 ;
     RECT  46.104 0.144 46.32 0.192 ;
     RECT  46.344 0.144 46.56 0.192 ;
     RECT  46.584 0.144 46.8 0.192 ;
     RECT  46.824 0.144 47.04 0.192 ;
     RECT  47.064 0.144 47.328 0.192 ;
     RECT  47.352 0.144 47.568 0.192 ;
     RECT  47.592 0.144 47.808 0.192 ;
     RECT  47.832 0.144 48.048 0.192 ;
     RECT  48.072 0.144 48.288 0.192 ;
     RECT  48.312 0.144 48.528 0.192 ;
     RECT  48.552 0.144 48.768 0.192 ;
     RECT  48.792 0.144 49.008 0.192 ;
     RECT  49.032 0.144 49.248 0.192 ;
     RECT  49.272 0.144 49.488 0.192 ;
     RECT  49.512 0.144 49.728 0.192 ;
     RECT  49.752 0.144 49.968 0.192 ;
     RECT  49.992 0.144 50.208 0.192 ;
     RECT  50.232 0.144 50.448 0.192 ;
     RECT  50.472 0.144 50.688 0.192 ;
     RECT  50.712 0.144 50.976 0.192 ;
     RECT  51 0.144 51.216 0.192 ;
     RECT  51.24 0.144 51.456 0.192 ;
     RECT  51.48 0.144 51.696 0.192 ;
     RECT  51.72 0.144 51.936 0.192 ;
     RECT  51.96 0.144 52.176 0.192 ;
     RECT  52.2 0.144 52.416 0.192 ;
     RECT  52.44 0.144 52.656 0.192 ;
     RECT  52.68 0.144 52.896 0.192 ;
     RECT  52.92 0.144 53.136 0.192 ;
     RECT  53.16 0.144 53.376 0.192 ;
     RECT  53.4 0.144 53.616 0.192 ;
     RECT  53.64 0.144 53.856 0.192 ;
     RECT  53.88 0.144 54.096 0.192 ;
     RECT  54.12 0.144 54.336 0.192 ;
     RECT  54.36 0.144 54.624 0.192 ;
     RECT  54.648 0.144 54.864 0.192 ;
     RECT  54.888 0.144 55.104 0.192 ;
     RECT  55.128 0.144 55.344 0.192 ;
     RECT  55.368 0.144 55.584 0.192 ;
     RECT  55.608 0.144 55.824 0.192 ;
     RECT  55.848 0.144 56.064 0.192 ;
     RECT  56.088 0.144 56.304 0.192 ;
     RECT  56.328 0.144 56.544 0.192 ;
     RECT  56.568 0.144 56.784 0.192 ;
     RECT  56.808 0.144 57.024 0.192 ;
     RECT  57.048 0.144 57.264 0.192 ;
     RECT  57.288 0.144 57.504 0.192 ;
     RECT  57.528 0.144 57.744 0.192 ;
     RECT  57.768 0.144 58.032 0.192 ;
     RECT  58.056 0.144 58.272 0.192 ;
     RECT  58.296 0.144 58.512 0.192 ;
     RECT  58.536 0.144 58.752 0.192 ;
     RECT  58.776 0.144 58.992 0.192 ;
     RECT  59.016 0.144 59.232 0.192 ;
     RECT  59.256 0.144 59.472 0.192 ;
     RECT  59.496 0.144 59.712 0.192 ;
     RECT  59.736 0.144 59.952 0.192 ;
     RECT  59.976 0.144 60.192 0.192 ;
     RECT  60.216 0.144 60.432 0.192 ;
     RECT  60.456 0.144 60.672 0.192 ;
     RECT  60.696 0.144 60.912 0.192 ;
     RECT  60.936 0.144 61.152 0.192 ;
     RECT  61.176 0.144 61.392 0.192 ;
     RECT  61.416 0.144 61.68 0.192 ;
     RECT  61.704 0.144 61.92 0.192 ;
     RECT  61.944 0.144 62.16 0.192 ;
     RECT  62.184 0.144 62.4 0.192 ;
     RECT  62.424 0.144 62.64 0.192 ;
     RECT  62.664 0.144 62.88 0.192 ;
     RECT  62.904 0.144 63.12 0.192 ;
     RECT  63.144 0.144 63.36 0.192 ;
     RECT  63.384 0.144 63.6 0.192 ;
     RECT  63.624 0.144 63.84 0.192 ;
     RECT  63.864 0.144 64.08 0.192 ;
     RECT  64.104 0.144 64.32 0.192 ;
     RECT  64.344 0.144 64.56 0.192 ;
     RECT  64.584 0.144 64.8 0.192 ;
     RECT  64.824 0.144 65.04 0.192 ;
     RECT  65.064 0.144 65.328 0.192 ;
     RECT  65.352 0.144 65.568 0.192 ;
     RECT  65.592 0.144 65.808 0.192 ;
     RECT  65.832 0.144 66.048 0.192 ;
     RECT  66.072 0.144 66.288 0.192 ;
     RECT  66.312 0.144 66.528 0.192 ;
     RECT  66.552 0.144 66.768 0.192 ;
     RECT  4.512 0.192 66.792 1.763 ;
     RECT  5.1 1.763 13.992 1.811 ;
     RECT  15.072 1.763 66.792 1.811 ;
     RECT  12.768 1.811 13.656 1.859 ;
     RECT  55.824 1.811 66.792 2.137 ;
     RECT  2.4 2.137 2.52 2.151 ;
     RECT  55.824 2.137 67.32 2.151 ;
     RECT  55.824 2.151 67.512 2.821 ;
     RECT  5.1 1.811 11.304 2.915 ;
     RECT  15.072 1.811 54.648 2.915 ;
     RECT  55.776 2.821 67.512 2.915 ;
     RECT  34.656 2.915 54.456 2.963 ;
     RECT  34.656 2.963 44.376 3.011 ;
     RECT  34.656 3.011 40.512 3.059 ;
     RECT  58.656 2.915 59.592 3.059 ;
     RECT  9.36 2.915 11.064 3.347 ;
     RECT  7.392 2.915 8.112 3.443 ;
     RECT  10.368 3.347 11.064 3.443 ;
     RECT  34.8 3.059 40.512 3.443 ;
     RECT  55.776 2.915 57.528 3.443 ;
     RECT  61.632 2.915 65.496 3.443 ;
     RECT  66.528 2.915 67.512 3.443 ;
     RECT  10.368 3.443 10.812 3.635 ;
     RECT  13.104 1.859 13.656 3.637 ;
     RECT  15.072 2.915 27.336 3.637 ;
     RECT  13.104 3.637 27.336 3.925 ;
     RECT  45.456 2.963 54.456 3.925 ;
     RECT  9.36 3.347 9.384 4.019 ;
     RECT  28.464 2.915 33 4.019 ;
     RECT  12.24 3.925 27.336 4.115 ;
     RECT  58.656 3.059 59.412 4.163 ;
     RECT  41.568 3.011 44.376 4.261 ;
     RECT  45.408 3.925 54.456 4.261 ;
     RECT  58.704 4.163 59.412 4.405 ;
     RECT  55.776 3.443 57.288 4.501 ;
     RECT  7.632 3.443 8.112 4.549 ;
     RECT  41.568 4.261 54.456 4.595 ;
     RECT  50.016 4.595 54.456 4.643 ;
     RECT  64.08 3.443 65.496 4.691 ;
     RECT  50.112 4.643 54.456 4.883 ;
     RECT  9.504 4.933 9.528 5.029 ;
     RECT  10.5 3.635 10.812 5.029 ;
     RECT  55.488 4.501 57.288 5.029 ;
     RECT  12.24 4.115 14.52 5.171 ;
     RECT  15.9 4.115 27.336 5.171 ;
     RECT  28.464 4.019 32.412 5.171 ;
     RECT  37.5 3.443 40.512 5.171 ;
     RECT  41.568 4.595 48.984 5.171 ;
     RECT  55.488 5.029 57.672 5.171 ;
     RECT  29.04 5.171 32.412 5.315 ;
     RECT  34.8 3.443 35.256 5.315 ;
     RECT  40.08 5.171 40.512 5.507 ;
     RECT  9.504 5.029 10.812 5.509 ;
     RECT  12.24 5.171 13.848 5.555 ;
     RECT  6.912 4.549 8.112 5.747 ;
     RECT  9.504 5.509 11.208 5.747 ;
     RECT  13.2 5.555 13.848 5.747 ;
     RECT  15.9 5.171 16.824 5.747 ;
     RECT  29.04 5.315 30.552 5.747 ;
     RECT  36.432 3.443 36.456 5.747 ;
     RECT  58.704 4.405 59.688 5.747 ;
     RECT  17.856 5.171 27.012 5.795 ;
     RECT  61.632 3.443 62.112 5.795 ;
     RECT  64.5 4.691 64.92 5.795 ;
     RECT  7.008 5.747 8.112 5.891 ;
     RECT  55.536 5.171 57.672 5.987 ;
     RECT  47.664 5.171 48.984 6.035 ;
     RECT  13.2 5.747 13.608 6.131 ;
     RECT  48.3 6.035 48.984 6.229 ;
     RECT  9.504 5.747 10.812 6.275 ;
     RECT  55.536 5.987 57 6.275 ;
     RECT  17.856 5.795 25.08 6.323 ;
     RECT  31.968 5.315 32.412 6.323 ;
     RECT  41.856 5.171 46.296 6.323 ;
     RECT  50.88 4.883 54.456 6.323 ;
     RECT  29.28 5.747 30.552 6.371 ;
     RECT  50.88 6.323 54.12 6.371 ;
     RECT  24 6.323 25.08 6.419 ;
     RECT  29.4 6.371 30.552 6.421 ;
     RECT  18.48 6.323 23.016 6.515 ;
     RECT  40.2 5.507 40.512 6.517 ;
     RECT  37.5 5.171 38.664 6.563 ;
     RECT  42.192 6.323 43.32 6.563 ;
     RECT  45.456 6.323 46.296 6.563 ;
     RECT  29.4 6.421 30.648 6.611 ;
     RECT  15.9 5.747 16.632 6.851 ;
     RECT  37.5 6.563 37.944 6.851 ;
     RECT  40.08 6.517 40.512 6.851 ;
     RECT  56.4 6.275 57 6.899 ;
     RECT  63.264 5.893 63.288 6.899 ;
     RECT  51 6.371 54.12 6.947 ;
     RECT  10.08 6.275 10.812 7.091 ;
     RECT  52.848 6.947 54.12 7.475 ;
     RECT  48.3 6.229 49.368 8.003 ;
     RECT  18.48 6.515 21.96 8.579 ;
     RECT  45.456 6.563 46.104 8.579 ;
     RECT  24 6.419 24.408 8.771 ;
     RECT  42.9 6.563 43.32 9.155 ;
     RECT  52.848 7.475 54.012 9.155 ;
     RECT  55.104 6.805 55.128 9.155 ;
     RECT  22.992 6.515 23.016 10.307 ;
     RECT  26.112 5.795 27.012 10.307 ;
     RECT  29.4 6.611 30.552 10.883 ;
     RECT  45.6 8.579 46.104 10.883 ;
     RECT  20.208 8.579 21.612 11.459 ;
     RECT  44.304 6.323 44.328 11.459 ;
     RECT  0.24 6.805 0.264 18.419 ;
     RECT  7.8 5.891 8.112 29.029 ;
     RECT  15.9 6.851 16.212 29.029 ;
     RECT  29.4 10.883 29.712 29.029 ;
     RECT  40.2 6.851 40.512 29.029 ;
     RECT  64.5 5.795 64.812 29.029 ;
     RECT  5.1 2.915 5.412 29.365 ;
     RECT  24 8.771 24.312 29.365 ;
     RECT  10.5 7.091 10.812 29.509 ;
     RECT  48.3 8.003 48.612 29.557 ;
     RECT  18.6 8.579 18.912 29.605 ;
     RECT  21.3 11.459 21.612 29.605 ;
     RECT  23.232 29.365 24.312 29.605 ;
     RECT  47.808 29.557 48.612 29.605 ;
     RECT  51 6.947 51.312 29.605 ;
     RECT  53.7 9.155 54.012 29.605 ;
     RECT  56.4 6.899 56.712 29.605 ;
     RECT  59.1 5.747 59.412 29.605 ;
     RECT  67.2 3.443 67.512 29.605 ;
     RECT  50.208 29.605 51.312 29.941 ;
     RECT  52.416 29.605 54.012 29.941 ;
     RECT  34.8 5.315 35.112 30.181 ;
     RECT  47.328 29.605 48.612 30.181 ;
     RECT  58.512 29.605 59.412 30.181 ;
     RECT  60.672 29.605 60.696 30.181 ;
     RECT  63.12 29.941 63.144 30.181 ;
     RECT  64.5 29.029 65.352 30.181 ;
     RECT  61.8 5.795 62.112 30.469 ;
     RECT  63.12 30.181 65.352 30.469 ;
     RECT  47.04 30.181 48.612 30.709 ;
     RECT  50.208 29.941 54.012 30.709 ;
     RECT  37.5 6.851 37.812 30.757 ;
     RECT  28.8 29.029 30.312 30.805 ;
     RECT  32.1 6.323 32.412 30.805 ;
     RECT  37.5 30.757 38.76 30.899 ;
     RECT  37.5 30.899 38.088 31.189 ;
     RECT  10.08 29.509 10.812 31.285 ;
     RECT  15.9 29.029 17.16 31.285 ;
     RECT  18.48 29.605 18.912 31.285 ;
     RECT  22.752 29.605 24.936 33.061 ;
     RECT  28.8 30.805 32.412 33.061 ;
     RECT  34.8 30.181 35.208 33.061 ;
     RECT  36.336 29.029 36.36 33.061 ;
     RECT  47.04 30.709 54.012 33.061 ;
     RECT  58.512 30.181 60.696 33.061 ;
     RECT  9.36 31.285 10.812 33.589 ;
     RECT  14.688 30.757 14.712 33.589 ;
     RECT  15.9 31.285 18.912 33.589 ;
     RECT  21.024 29.605 21.612 33.589 ;
     RECT  22.752 33.061 25.176 33.589 ;
     RECT  37.392 31.189 38.088 33.589 ;
     RECT  45.6 10.883 45.912 33.589 ;
     RECT  7.68 29.029 8.112 33.637 ;
     RECT  9.12 33.589 11.064 33.637 ;
     RECT  55.344 29.605 56.712 33.637 ;
     RECT  57.744 33.061 60.696 33.637 ;
     RECT  13.2 6.131 13.512 34.165 ;
     RECT  14.688 33.589 19.032 34.165 ;
     RECT  34.8 33.061 36.36 34.165 ;
     RECT  37.392 33.589 38.328 34.165 ;
     RECT  45.6 33.589 46.008 34.165 ;
     RECT  47.04 33.061 54.12 34.165 ;
     RECT  4.752 29.365 5.412 34.213 ;
     RECT  6.432 29.029 6.456 34.213 ;
     RECT  7.68 33.637 11.064 34.213 ;
     RECT  12.048 34.165 12.072 34.213 ;
     RECT  13.2 34.165 19.032 34.213 ;
     RECT  20.064 33.589 25.176 34.213 ;
     RECT  26.7 10.307 27.012 34.213 ;
     RECT  28.8 33.061 33.24 34.213 ;
     RECT  34.8 34.165 38.328 34.213 ;
     RECT  40.2 29.029 41.256 34.213 ;
     RECT  42.9 9.155 43.212 34.213 ;
     RECT  45.6 34.165 54.12 34.213 ;
     RECT  55.104 33.637 60.696 34.213 ;
     RECT  61.8 30.469 65.352 34.213 ;
     RECT  20.064 34.213 38.328 34.549 ;
     RECT  39.984 34.213 41.256 34.549 ;
     RECT  2.4 2.151 2.712 34.569 ;
     RECT  66.768 29.605 67.512 34.569 ;
     RECT  2.4 34.569 2.52 34.583 ;
     RECT  66.768 34.569 67.32 34.583 ;
     RECT  45.6 34.213 65.352 34.597 ;
     RECT  66.768 34.583 66.792 34.597 ;
     RECT  12.048 34.213 19.032 34.645 ;
     RECT  20.064 34.549 41.256 34.645 ;
     RECT  42.672 34.213 44.424 34.645 ;
     RECT  45.6 34.597 66.792 34.645 ;
     RECT  12.048 34.645 41.256 34.693 ;
     RECT  42.672 34.645 66.792 34.693 ;
     RECT  4.752 34.213 11.064 34.741 ;
     RECT  12.048 34.693 66.792 34.741 ;
     RECT  4.512 34.741 66.792 36.528 ;
     RECT  4.536 36.528 4.752 36.56 ;
     RECT  4.776 36.528 4.992 36.56 ;
     RECT  5.016 36.528 5.232 36.56 ;
     RECT  5.256 36.528 5.472 36.56 ;
     RECT  5.496 36.528 5.712 36.56 ;
     RECT  5.736 36.528 5.952 36.56 ;
     RECT  5.976 36.528 6.192 36.56 ;
     RECT  6.216 36.528 6.432 36.56 ;
     RECT  6.456 36.528 6.672 36.56 ;
     RECT  6.696 36.528 6.912 36.56 ;
     RECT  6.936 36.528 7.152 36.56 ;
     RECT  7.176 36.528 7.392 36.56 ;
     RECT  7.416 36.528 7.632 36.56 ;
     RECT  7.656 36.528 7.92 36.56 ;
     RECT  7.944 36.528 8.16 36.56 ;
     RECT  8.184 36.528 8.4 36.56 ;
     RECT  8.424 36.528 8.64 36.56 ;
     RECT  8.664 36.528 8.88 36.56 ;
     RECT  8.904 36.528 9.12 36.56 ;
     RECT  9.144 36.528 9.36 36.56 ;
     RECT  9.384 36.528 9.6 36.56 ;
     RECT  9.624 36.528 9.84 36.56 ;
     RECT  9.864 36.528 10.08 36.56 ;
     RECT  10.104 36.528 10.32 36.56 ;
     RECT  10.344 36.528 10.56 36.56 ;
     RECT  10.584 36.528 10.8 36.56 ;
     RECT  10.824 36.528 11.04 36.56 ;
     RECT  11.064 36.528 11.28 36.56 ;
     RECT  11.304 36.528 11.568 36.56 ;
     RECT  11.592 36.528 11.808 36.56 ;
     RECT  11.832 36.528 12.048 36.56 ;
     RECT  12.072 36.528 12.288 36.56 ;
     RECT  12.312 36.528 12.528 36.56 ;
     RECT  12.552 36.528 12.768 36.56 ;
     RECT  12.792 36.528 13.008 36.56 ;
     RECT  13.032 36.528 13.248 36.56 ;
     RECT  13.272 36.528 13.488 36.56 ;
     RECT  13.512 36.528 13.728 36.56 ;
     RECT  13.752 36.528 13.968 36.56 ;
     RECT  13.992 36.528 14.208 36.56 ;
     RECT  14.232 36.528 14.448 36.56 ;
     RECT  14.472 36.528 14.688 36.56 ;
     RECT  14.712 36.528 14.928 36.56 ;
     RECT  14.952 36.528 15.216 36.56 ;
     RECT  15.24 36.528 15.456 36.56 ;
     RECT  15.48 36.528 15.696 36.56 ;
     RECT  15.72 36.528 15.936 36.56 ;
     RECT  15.96 36.528 16.176 36.56 ;
     RECT  16.2 36.528 16.416 36.56 ;
     RECT  16.44 36.528 16.656 36.56 ;
     RECT  16.68 36.528 16.896 36.56 ;
     RECT  16.92 36.528 17.136 36.56 ;
     RECT  17.16 36.528 17.376 36.56 ;
     RECT  17.4 36.528 17.616 36.56 ;
     RECT  17.64 36.528 17.856 36.56 ;
     RECT  17.88 36.528 18.096 36.56 ;
     RECT  18.12 36.528 18.336 36.56 ;
     RECT  18.36 36.528 18.576 36.56 ;
     RECT  18.6 36.528 18.864 36.56 ;
     RECT  18.888 36.528 19.104 36.56 ;
     RECT  19.128 36.528 19.344 36.56 ;
     RECT  19.368 36.528 19.584 36.56 ;
     RECT  19.608 36.528 19.824 36.56 ;
     RECT  19.848 36.528 20.064 36.56 ;
     RECT  20.088 36.528 20.304 36.56 ;
     RECT  20.328 36.528 20.544 36.56 ;
     RECT  20.568 36.528 20.784 36.56 ;
     RECT  20.808 36.528 21.024 36.56 ;
     RECT  21.048 36.528 21.264 36.56 ;
     RECT  21.288 36.528 21.504 36.56 ;
     RECT  21.528 36.528 21.744 36.56 ;
     RECT  21.768 36.528 21.984 36.56 ;
     RECT  22.008 36.528 22.272 36.56 ;
     RECT  22.296 36.528 22.512 36.56 ;
     RECT  22.536 36.528 22.752 36.56 ;
     RECT  22.776 36.528 22.992 36.56 ;
     RECT  23.016 36.528 23.232 36.56 ;
     RECT  23.256 36.528 23.472 36.56 ;
     RECT  23.496 36.528 23.712 36.56 ;
     RECT  23.736 36.528 23.952 36.56 ;
     RECT  23.976 36.528 24.192 36.56 ;
     RECT  24.216 36.528 24.432 36.56 ;
     RECT  24.456 36.528 24.672 36.56 ;
     RECT  24.696 36.528 24.912 36.56 ;
     RECT  24.936 36.528 25.152 36.56 ;
     RECT  25.176 36.528 25.392 36.56 ;
     RECT  25.416 36.528 25.632 36.56 ;
     RECT  25.656 36.528 25.92 36.56 ;
     RECT  25.944 36.528 26.16 36.56 ;
     RECT  26.184 36.528 26.4 36.56 ;
     RECT  26.424 36.528 26.64 36.56 ;
     RECT  26.664 36.528 26.88 36.56 ;
     RECT  26.904 36.528 27.12 36.56 ;
     RECT  27.144 36.528 27.36 36.56 ;
     RECT  27.384 36.528 27.6 36.56 ;
     RECT  27.624 36.528 27.84 36.56 ;
     RECT  27.864 36.528 28.08 36.56 ;
     RECT  28.104 36.528 28.32 36.56 ;
     RECT  28.344 36.528 28.56 36.56 ;
     RECT  28.584 36.528 28.8 36.56 ;
     RECT  28.824 36.528 29.04 36.56 ;
     RECT  29.064 36.528 29.28 36.56 ;
     RECT  29.304 36.528 29.568 36.56 ;
     RECT  29.592 36.528 29.808 36.56 ;
     RECT  29.832 36.528 30.048 36.56 ;
     RECT  30.072 36.528 30.288 36.56 ;
     RECT  30.312 36.528 30.528 36.56 ;
     RECT  30.552 36.528 30.768 36.56 ;
     RECT  30.792 36.528 31.008 36.56 ;
     RECT  31.032 36.528 31.248 36.56 ;
     RECT  31.272 36.528 31.488 36.56 ;
     RECT  31.512 36.528 31.728 36.56 ;
     RECT  31.752 36.528 31.968 36.56 ;
     RECT  31.992 36.528 32.208 36.56 ;
     RECT  32.232 36.528 32.448 36.56 ;
     RECT  32.472 36.528 32.688 36.56 ;
     RECT  32.712 36.528 32.976 36.56 ;
     RECT  33 36.528 33.216 36.56 ;
     RECT  33.24 36.528 33.456 36.56 ;
     RECT  33.48 36.528 33.696 36.56 ;
     RECT  33.72 36.528 33.936 36.56 ;
     RECT  33.96 36.528 34.176 36.56 ;
     RECT  34.2 36.528 34.416 36.56 ;
     RECT  34.44 36.528 34.656 36.56 ;
     RECT  34.68 36.528 34.896 36.56 ;
     RECT  34.92 36.528 35.136 36.56 ;
     RECT  35.16 36.528 35.376 36.56 ;
     RECT  35.4 36.528 35.616 36.56 ;
     RECT  35.64 36.528 35.856 36.56 ;
     RECT  35.88 36.528 36.096 36.56 ;
     RECT  36.12 36.528 36.336 36.56 ;
     RECT  36.36 36.528 36.624 36.56 ;
     RECT  36.648 36.528 36.864 36.56 ;
     RECT  36.888 36.528 37.104 36.56 ;
     RECT  37.128 36.528 37.344 36.56 ;
     RECT  37.368 36.528 37.584 36.56 ;
     RECT  37.608 36.528 37.824 36.56 ;
     RECT  37.848 36.528 38.064 36.56 ;
     RECT  38.088 36.528 38.304 36.56 ;
     RECT  38.328 36.528 38.544 36.56 ;
     RECT  38.568 36.528 38.784 36.56 ;
     RECT  38.808 36.528 39.024 36.56 ;
     RECT  39.048 36.528 39.264 36.56 ;
     RECT  39.288 36.528 39.504 36.56 ;
     RECT  39.528 36.528 39.744 36.56 ;
     RECT  39.768 36.528 39.984 36.56 ;
     RECT  40.008 36.528 40.272 36.56 ;
     RECT  40.296 36.528 40.512 36.56 ;
     RECT  40.536 36.528 40.752 36.56 ;
     RECT  40.776 36.528 40.992 36.56 ;
     RECT  41.016 36.528 41.232 36.56 ;
     RECT  41.256 36.528 41.472 36.56 ;
     RECT  41.496 36.528 41.712 36.56 ;
     RECT  41.736 36.528 41.952 36.56 ;
     RECT  41.976 36.528 42.192 36.56 ;
     RECT  42.216 36.528 42.432 36.56 ;
     RECT  42.456 36.528 42.672 36.56 ;
     RECT  42.696 36.528 42.912 36.56 ;
     RECT  42.936 36.528 43.152 36.56 ;
     RECT  43.176 36.528 43.392 36.56 ;
     RECT  43.416 36.528 43.632 36.56 ;
     RECT  43.656 36.528 43.92 36.56 ;
     RECT  43.944 36.528 44.16 36.56 ;
     RECT  44.184 36.528 44.4 36.56 ;
     RECT  44.424 36.528 44.64 36.56 ;
     RECT  44.664 36.528 44.88 36.56 ;
     RECT  44.904 36.528 45.12 36.56 ;
     RECT  45.144 36.528 45.36 36.56 ;
     RECT  45.384 36.528 45.6 36.56 ;
     RECT  45.624 36.528 45.84 36.56 ;
     RECT  45.864 36.528 46.08 36.56 ;
     RECT  46.104 36.528 46.32 36.56 ;
     RECT  46.344 36.528 46.56 36.56 ;
     RECT  46.584 36.528 46.8 36.56 ;
     RECT  46.824 36.528 47.04 36.56 ;
     RECT  47.064 36.528 47.328 36.56 ;
     RECT  47.352 36.528 47.568 36.56 ;
     RECT  47.592 36.528 47.808 36.56 ;
     RECT  47.832 36.528 48.048 36.56 ;
     RECT  48.072 36.528 48.288 36.56 ;
     RECT  48.312 36.528 48.528 36.56 ;
     RECT  48.552 36.528 48.768 36.56 ;
     RECT  48.792 36.528 49.008 36.56 ;
     RECT  49.032 36.528 49.248 36.56 ;
     RECT  49.272 36.528 49.488 36.56 ;
     RECT  49.512 36.528 49.728 36.56 ;
     RECT  49.752 36.528 49.968 36.56 ;
     RECT  49.992 36.528 50.208 36.56 ;
     RECT  50.232 36.528 50.448 36.56 ;
     RECT  50.472 36.528 50.688 36.56 ;
     RECT  50.712 36.528 50.976 36.56 ;
     RECT  51 36.528 51.216 36.56 ;
     RECT  51.24 36.528 51.456 36.56 ;
     RECT  51.48 36.528 51.696 36.56 ;
     RECT  51.72 36.528 51.936 36.56 ;
     RECT  51.96 36.528 52.176 36.56 ;
     RECT  52.2 36.528 52.416 36.56 ;
     RECT  52.44 36.528 52.656 36.56 ;
     RECT  52.68 36.528 52.896 36.56 ;
     RECT  52.92 36.528 53.136 36.56 ;
     RECT  53.16 36.528 53.376 36.56 ;
     RECT  53.4 36.528 53.616 36.56 ;
     RECT  53.64 36.528 53.856 36.56 ;
     RECT  53.88 36.528 54.096 36.56 ;
     RECT  54.12 36.528 54.336 36.56 ;
     RECT  54.36 36.528 54.624 36.56 ;
     RECT  54.648 36.528 54.864 36.56 ;
     RECT  54.888 36.528 55.104 36.56 ;
     RECT  55.128 36.528 55.344 36.56 ;
     RECT  55.368 36.528 55.584 36.56 ;
     RECT  55.608 36.528 55.824 36.56 ;
     RECT  55.848 36.528 56.064 36.56 ;
     RECT  56.088 36.528 56.304 36.56 ;
     RECT  56.328 36.528 56.544 36.56 ;
     RECT  56.568 36.528 56.784 36.56 ;
     RECT  56.808 36.528 57.024 36.56 ;
     RECT  57.048 36.528 57.264 36.56 ;
     RECT  57.288 36.528 57.504 36.56 ;
     RECT  57.528 36.528 57.744 36.56 ;
     RECT  57.768 36.528 58.032 36.56 ;
     RECT  58.056 36.528 58.272 36.56 ;
     RECT  58.296 36.528 58.512 36.56 ;
     RECT  58.536 36.528 58.752 36.56 ;
     RECT  58.776 36.528 58.992 36.56 ;
     RECT  59.016 36.528 59.232 36.56 ;
     RECT  59.256 36.528 59.472 36.56 ;
     RECT  59.496 36.528 59.712 36.56 ;
     RECT  59.736 36.528 59.952 36.56 ;
     RECT  59.976 36.528 60.192 36.56 ;
     RECT  60.216 36.528 60.432 36.56 ;
     RECT  60.456 36.528 60.672 36.56 ;
     RECT  60.696 36.528 60.912 36.56 ;
     RECT  60.936 36.528 61.152 36.56 ;
     RECT  61.176 36.528 61.392 36.56 ;
     RECT  61.416 36.528 61.68 36.56 ;
     RECT  61.704 36.528 61.92 36.56 ;
     RECT  61.944 36.528 62.16 36.56 ;
     RECT  62.184 36.528 62.4 36.56 ;
     RECT  62.424 36.528 62.64 36.56 ;
     RECT  62.664 36.528 62.88 36.56 ;
     RECT  62.904 36.528 63.12 36.56 ;
     RECT  63.144 36.528 63.36 36.56 ;
     RECT  63.384 36.528 63.6 36.56 ;
     RECT  63.624 36.528 63.84 36.56 ;
     RECT  63.864 36.528 64.08 36.56 ;
     RECT  64.104 36.528 64.32 36.56 ;
     RECT  64.344 36.528 64.56 36.56 ;
     RECT  64.584 36.528 64.8 36.56 ;
     RECT  64.824 36.528 65.04 36.56 ;
     RECT  65.064 36.528 65.328 36.56 ;
     RECT  65.352 36.528 65.568 36.56 ;
     RECT  65.592 36.528 65.808 36.56 ;
     RECT  65.832 36.528 66.048 36.56 ;
     RECT  66.072 36.528 66.288 36.56 ;
     RECT  66.312 36.528 66.528 36.56 ;
     RECT  66.552 36.528 66.768 36.56 ;
     RECT  13.992 1.763 15.072 1.811 ;
     RECT  11.304 1.811 12.768 1.859 ;
     RECT  13.656 1.811 15.072 3.637 ;
     RECT  54.648 1.811 55.824 2.821 ;
     RECT  54.648 2.821 55.776 2.915 ;
     RECT  8.112 2.915 9.36 4.019 ;
     RECT  11.064 2.915 11.304 3.443 ;
     RECT  27.336 2.915 28.464 5.171 ;
     RECT  54.456 2.915 55.776 4.501 ;
     RECT  57.528 2.915 58.656 3.443 ;
     RECT  59.592 2.915 59.688 3.059 ;
     RECT  65.496 2.915 66.528 3.443 ;
     RECT  44.376 2.963 45.456 3.925 ;
     RECT  40.512 3.011 41.568 5.171 ;
     RECT  59.412 3.059 59.688 4.405 ;
     RECT  9.384 3.347 10.368 3.635 ;
     RECT  7.392 3.443 7.632 4.549 ;
     RECT  10.812 3.443 11.304 3.925 ;
     RECT  35.256 3.443 36.432 5.315 ;
     RECT  36.456 3.443 37.5 5.747 ;
     RECT  57.288 3.443 58.656 4.163 ;
     RECT  9.384 3.635 10.5 4.019 ;
     RECT  10.812 3.925 12.24 5.509 ;
     RECT  44.376 3.925 45.408 4.261 ;
     RECT  8.112 4.019 10.5 4.933 ;
     RECT  14.52 4.115 15.9 5.171 ;
     RECT  57.288 4.163 58.704 5.029 ;
     RECT  54.456 4.501 55.488 5.171 ;
     RECT  5.412 4.549 6.912 5.747 ;
     RECT  48.984 4.595 50.016 4.643 ;
     RECT  48.984 4.643 50.112 4.883 ;
     RECT  64.08 4.691 64.5 5.893 ;
     RECT  48.984 4.883 50.88 6.229 ;
     RECT  8.112 4.933 9.504 6.275 ;
     RECT  9.528 4.933 10.5 5.029 ;
     RECT  57.672 5.029 58.704 5.747 ;
     RECT  16.824 5.171 17.856 5.747 ;
     RECT  38.664 5.171 40.08 5.507 ;
     RECT  40.512 5.171 41.856 6.323 ;
     RECT  46.296 5.171 47.664 6.035 ;
     RECT  54.456 5.171 55.536 6.275 ;
     RECT  30.552 5.315 31.968 6.323 ;
     RECT  35.112 5.315 36.432 5.747 ;
     RECT  38.664 5.507 40.2 6.517 ;
     RECT  11.208 5.509 12.24 5.555 ;
     RECT  16.632 5.747 17.856 6.323 ;
     RECT  57.672 5.747 59.1 5.987 ;
     RECT  25.08 5.795 26.112 6.419 ;
     RECT  62.112 5.893 63.264 6.899 ;
     RECT  63.288 5.893 64.5 6.899 ;
     RECT  49.368 6.229 50.88 6.371 ;
     RECT  54.456 6.275 56.4 6.323 ;
     RECT  23.016 6.323 24 10.307 ;
     RECT  30.552 6.323 32.1 6.421 ;
     RECT  43.32 6.323 44.304 9.155 ;
     RECT  44.328 6.323 45.456 8.579 ;
     RECT  54.12 6.323 56.4 6.805 ;
     RECT  30.648 6.421 32.1 6.611 ;
     RECT  21.96 6.515 22.992 8.579 ;
     RECT  38.664 6.517 40.08 6.563 ;
     RECT  54.12 6.805 55.104 7.475 ;
     RECT  55.128 6.805 56.4 9.155 ;
     RECT  54.012 7.475 55.104 9.155 ;
     RECT  18.912 8.579 20.208 11.459 ;
     RECT  21.612 8.579 22.992 10.307 ;
     RECT  44.328 8.579 45.6 11.459 ;
     RECT  43.212 9.155 44.304 11.459 ;
     RECT  5.412 29.029 6.432 34.213 ;
     RECT  6.456 29.029 7.68 34.213 ;
     RECT  17.16 29.029 18.6 29.605 ;
     RECT  35.112 29.029 36.336 30.181 ;
     RECT  36.36 29.029 37.5 31.189 ;
     RECT  17.16 29.605 18.48 31.285 ;
     RECT  21.612 29.605 22.752 33.589 ;
     RECT  45.912 29.605 47.328 30.181 ;
     RECT  51.312 29.605 52.416 29.941 ;
     RECT  54.012 29.605 55.344 33.061 ;
     RECT  59.412 29.605 60.672 30.181 ;
     RECT  60.696 29.605 61.8 34.213 ;
     RECT  65.352 29.605 66.768 34.597 ;
     RECT  62.112 29.941 63.12 30.469 ;
     RECT  63.144 29.941 64.5 30.181 ;
     RECT  35.208 30.181 36.336 33.061 ;
     RECT  45.912 30.181 47.04 33.589 ;
     RECT  13.512 30.757 14.688 34.165 ;
     RECT  14.712 30.757 15.9 33.589 ;
     RECT  38.76 30.757 40.2 30.899 ;
     RECT  36.36 31.189 37.392 34.165 ;
     RECT  8.112 31.285 9.36 33.589 ;
     RECT  25.176 33.061 26.7 34.213 ;
     RECT  54.12 33.061 55.344 33.637 ;
     RECT  56.712 33.061 57.744 33.637 ;
     RECT  8.112 33.589 9.12 33.637 ;
     RECT  19.032 33.589 20.064 34.645 ;
     RECT  46.008 33.589 47.04 34.165 ;
     RECT  54.12 33.637 55.104 34.213 ;
     RECT  11.064 34.165 12.048 34.741 ;
     RECT  12.072 34.165 13.2 34.213 ;
     RECT  41.256 34.213 42.672 34.693 ;
     RECT  44.424 34.213 45.6 34.645 ;
  END
END dsfd_hstnv_515
END LIBRARY
